VERSION 5.8 ;
BUSBITCHARS "[]" ;
DIVIDERCHAR "/" ;
UNITS
    DATABASE MICRONS 1000 ;
END UNITS

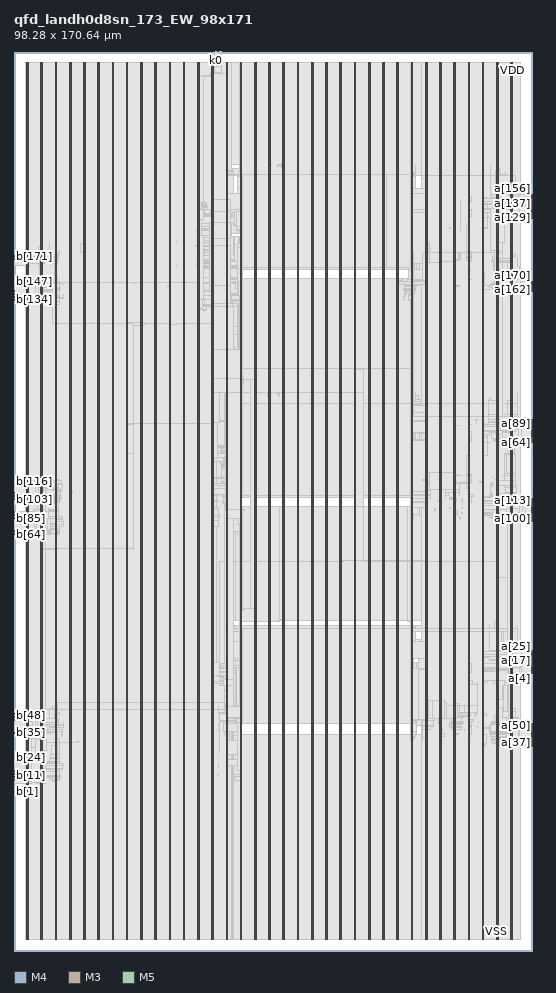
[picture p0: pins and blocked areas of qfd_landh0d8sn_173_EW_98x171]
MACRO qfd_landh0d8sn_173_EW_98x171
  FOREIGN qfd_landh0d8sn_173_EW_98x171 0 0 ;
  CLASS BLOCK ;
  SIZE 98.28 BY 170.64 ;
  PIN a[0]
    DIRECTION INPUT ;
    USE SIGNAL ;
    PORT
      LAYER M4 ;
        RECT  98.196 52.56 98.28 52.584 ;
    END
  END a[0]
  PIN a[100]
    DIRECTION INPUT ;
    USE SIGNAL ;
    PORT
      LAYER M4 ;
        RECT  98.196 81.936 98.28 81.96 ;
    END
  END a[100]
  PIN a[101]
    DIRECTION INPUT ;
    USE SIGNAL ;
    PORT
      LAYER M4 ;
        RECT  98.196 82.08 98.28 82.104 ;
    END
  END a[101]
  PIN a[102]
    DIRECTION INPUT ;
    USE SIGNAL ;
    PORT
      LAYER M4 ;
        RECT  98.196 82.224 98.28 82.248 ;
    END
  END a[102]
  PIN a[103]
    DIRECTION INPUT ;
    USE SIGNAL ;
    PORT
      LAYER M4 ;
        RECT  98.196 82.368 98.28 82.392 ;
    END
  END a[103]
  PIN a[104]
    DIRECTION INPUT ;
    USE SIGNAL ;
    PORT
      LAYER M4 ;
        RECT  98.196 82.512 98.28 82.536 ;
    END
  END a[104]
  PIN a[105]
    DIRECTION INPUT ;
    USE SIGNAL ;
    PORT
      LAYER M4 ;
        RECT  98.196 82.656 98.28 82.68 ;
    END
  END a[105]
  PIN a[106]
    DIRECTION INPUT ;
    USE SIGNAL ;
    PORT
      LAYER M4 ;
        RECT  98.196 82.8 98.28 82.824 ;
    END
  END a[106]
  PIN a[107]
    DIRECTION INPUT ;
    USE SIGNAL ;
    PORT
      LAYER M4 ;
        RECT  98.196 82.944 98.28 82.968 ;
    END
  END a[107]
  PIN a[108]
    DIRECTION INPUT ;
    USE SIGNAL ;
    PORT
      LAYER M4 ;
        RECT  98.196 83.088 98.28 83.112 ;
    END
  END a[108]
  PIN a[109]
    DIRECTION INPUT ;
    USE SIGNAL ;
    PORT
      LAYER M4 ;
        RECT  98.196 83.232 98.28 83.256 ;
    END
  END a[109]
  PIN a[10]
    DIRECTION INPUT ;
    USE SIGNAL ;
    PORT
      LAYER M4 ;
        RECT  98.196 54 98.28 54.024 ;
    END
  END a[10]
  PIN a[110]
    DIRECTION INPUT ;
    USE SIGNAL ;
    PORT
      LAYER M4 ;
        RECT  98.196 83.376 98.28 83.4 ;
    END
  END a[110]
  PIN a[111]
    DIRECTION INPUT ;
    USE SIGNAL ;
    PORT
      LAYER M4 ;
        RECT  98.196 83.52 98.28 83.544 ;
    END
  END a[111]
  PIN a[112]
    DIRECTION INPUT ;
    USE SIGNAL ;
    PORT
      LAYER M4 ;
        RECT  98.196 83.664 98.28 83.688 ;
    END
  END a[112]
  PIN a[113]
    DIRECTION INPUT ;
    USE SIGNAL ;
    PORT
      LAYER M4 ;
        RECT  98.196 83.808 98.28 83.832 ;
    END
  END a[113]
  PIN a[114]
    DIRECTION INPUT ;
    USE SIGNAL ;
    PORT
      LAYER M4 ;
        RECT  98.196 83.952 98.28 83.976 ;
    END
  END a[114]
  PIN a[115]
    DIRECTION INPUT ;
    USE SIGNAL ;
    PORT
      LAYER M4 ;
        RECT  98.196 84.096 98.28 84.12 ;
    END
  END a[115]
  PIN a[116]
    DIRECTION INPUT ;
    USE SIGNAL ;
    PORT
      LAYER M4 ;
        RECT  98.196 84.24 98.28 84.264 ;
    END
  END a[116]
  PIN a[117]
    DIRECTION INPUT ;
    USE SIGNAL ;
    PORT
      LAYER M4 ;
        RECT  98.196 84.384 98.28 84.408 ;
    END
  END a[117]
  PIN a[118]
    DIRECTION INPUT ;
    USE SIGNAL ;
    PORT
      LAYER M4 ;
        RECT  98.196 84.528 98.28 84.552 ;
    END
  END a[118]
  PIN a[119]
    DIRECTION INPUT ;
    USE SIGNAL ;
    PORT
      LAYER M4 ;
        RECT  98.196 84.672 98.28 84.696 ;
    END
  END a[119]
  PIN a[11]
    DIRECTION INPUT ;
    USE SIGNAL ;
    PORT
      LAYER M4 ;
        RECT  98.196 54.144 98.28 54.168 ;
    END
  END a[11]
  PIN a[120]
    DIRECTION INPUT ;
    USE SIGNAL ;
    PORT
      LAYER M4 ;
        RECT  98.196 84.816 98.28 84.84 ;
    END
  END a[120]
  PIN a[121]
    DIRECTION INPUT ;
    USE SIGNAL ;
    PORT
      LAYER M4 ;
        RECT  98.196 84.96 98.28 84.984 ;
    END
  END a[121]
  PIN a[122]
    DIRECTION INPUT ;
    USE SIGNAL ;
    PORT
      LAYER M4 ;
        RECT  98.196 85.104 98.28 85.128 ;
    END
  END a[122]
  PIN a[123]
    DIRECTION INPUT ;
    USE SIGNAL ;
    PORT
      LAYER M4 ;
        RECT  98.196 85.248 98.28 85.272 ;
    END
  END a[123]
  PIN a[124]
    DIRECTION INPUT ;
    USE SIGNAL ;
    PORT
      LAYER M4 ;
        RECT  98.196 85.392 98.28 85.416 ;
    END
  END a[124]
  PIN a[125]
    DIRECTION INPUT ;
    USE SIGNAL ;
    PORT
      LAYER M4 ;
        RECT  98.196 85.536 98.28 85.56 ;
    END
  END a[125]
  PIN a[126]
    DIRECTION INPUT ;
    USE SIGNAL ;
    PORT
      LAYER M4 ;
        RECT  98.196 85.68 98.28 85.704 ;
    END
  END a[126]
  PIN a[127]
    DIRECTION INPUT ;
    USE SIGNAL ;
    PORT
      LAYER M4 ;
        RECT  98.196 85.824 98.28 85.848 ;
    END
  END a[127]
  PIN a[128]
    DIRECTION INPUT ;
    USE SIGNAL ;
    PORT
      LAYER M4 ;
        RECT  98.196 138.96 98.28 138.984 ;
    END
  END a[128]
  PIN a[129]
    DIRECTION INPUT ;
    USE SIGNAL ;
    PORT
      LAYER M4 ;
        RECT  98.196 139.104 98.28 139.128 ;
    END
  END a[129]
  PIN a[12]
    DIRECTION INPUT ;
    USE SIGNAL ;
    PORT
      LAYER M4 ;
        RECT  98.196 54.288 98.28 54.312 ;
    END
  END a[12]
  PIN a[130]
    DIRECTION INPUT ;
    USE SIGNAL ;
    PORT
      LAYER M4 ;
        RECT  98.196 139.248 98.28 139.272 ;
    END
  END a[130]
  PIN a[131]
    DIRECTION INPUT ;
    USE SIGNAL ;
    PORT
      LAYER M4 ;
        RECT  98.196 139.392 98.28 139.416 ;
    END
  END a[131]
  PIN a[132]
    DIRECTION INPUT ;
    USE SIGNAL ;
    PORT
      LAYER M4 ;
        RECT  98.196 139.536 98.28 139.56 ;
    END
  END a[132]
  PIN a[133]
    DIRECTION INPUT ;
    USE SIGNAL ;
    PORT
      LAYER M4 ;
        RECT  98.196 139.68 98.28 139.704 ;
    END
  END a[133]
  PIN a[134]
    DIRECTION INPUT ;
    USE SIGNAL ;
    PORT
      LAYER M4 ;
        RECT  98.196 139.824 98.28 139.848 ;
    END
  END a[134]
  PIN a[135]
    DIRECTION INPUT ;
    USE SIGNAL ;
    PORT
      LAYER M4 ;
        RECT  98.196 139.968 98.28 139.992 ;
    END
  END a[135]
  PIN a[136]
    DIRECTION INPUT ;
    USE SIGNAL ;
    PORT
      LAYER M4 ;
        RECT  98.196 140.112 98.28 140.136 ;
    END
  END a[136]
  PIN a[137]
    DIRECTION INPUT ;
    USE SIGNAL ;
    PORT
      LAYER M4 ;
        RECT  98.196 140.256 98.28 140.28 ;
    END
  END a[137]
  PIN a[138]
    DIRECTION INPUT ;
    USE SIGNAL ;
    PORT
      LAYER M4 ;
        RECT  98.196 140.4 98.28 140.424 ;
    END
  END a[138]
  PIN a[139]
    DIRECTION INPUT ;
    USE SIGNAL ;
    PORT
      LAYER M4 ;
        RECT  98.196 140.544 98.28 140.568 ;
    END
  END a[139]
  PIN a[13]
    DIRECTION INPUT ;
    USE SIGNAL ;
    PORT
      LAYER M4 ;
        RECT  98.196 54.432 98.28 54.456 ;
    END
  END a[13]
  PIN a[140]
    DIRECTION INPUT ;
    USE SIGNAL ;
    PORT
      LAYER M4 ;
        RECT  98.196 140.688 98.28 140.712 ;
    END
  END a[140]
  PIN a[141]
    DIRECTION INPUT ;
    USE SIGNAL ;
    PORT
      LAYER M4 ;
        RECT  98.196 140.832 98.28 140.856 ;
    END
  END a[141]
  PIN a[142]
    DIRECTION INPUT ;
    USE SIGNAL ;
    PORT
      LAYER M4 ;
        RECT  98.196 140.976 98.28 141 ;
    END
  END a[142]
  PIN a[143]
    DIRECTION INPUT ;
    USE SIGNAL ;
    PORT
      LAYER M4 ;
        RECT  98.196 141.12 98.28 141.144 ;
    END
  END a[143]
  PIN a[144]
    DIRECTION INPUT ;
    USE SIGNAL ;
    PORT
      LAYER M4 ;
        RECT  98.196 141.264 98.28 141.288 ;
    END
  END a[144]
  PIN a[145]
    DIRECTION INPUT ;
    USE SIGNAL ;
    PORT
      LAYER M4 ;
        RECT  98.196 141.408 98.28 141.432 ;
    END
  END a[145]
  PIN a[146]
    DIRECTION INPUT ;
    USE SIGNAL ;
    PORT
      LAYER M4 ;
        RECT  98.196 141.552 98.28 141.576 ;
    END
  END a[146]
  PIN a[147]
    DIRECTION INPUT ;
    USE SIGNAL ;
    PORT
      LAYER M4 ;
        RECT  98.196 141.696 98.28 141.72 ;
    END
  END a[147]
  PIN a[148]
    DIRECTION INPUT ;
    USE SIGNAL ;
    PORT
      LAYER M4 ;
        RECT  98.196 141.84 98.28 141.864 ;
    END
  END a[148]
  PIN a[149]
    DIRECTION INPUT ;
    USE SIGNAL ;
    PORT
      LAYER M4 ;
        RECT  98.196 141.984 98.28 142.008 ;
    END
  END a[149]
  PIN a[14]
    DIRECTION INPUT ;
    USE SIGNAL ;
    PORT
      LAYER M4 ;
        RECT  98.196 54.576 98.28 54.6 ;
    END
  END a[14]
  PIN a[150]
    DIRECTION INPUT ;
    USE SIGNAL ;
    PORT
      LAYER M4 ;
        RECT  98.196 142.128 98.28 142.152 ;
    END
  END a[150]
  PIN a[151]
    DIRECTION INPUT ;
    USE SIGNAL ;
    PORT
      LAYER M4 ;
        RECT  98.196 142.272 98.28 142.296 ;
    END
  END a[151]
  PIN a[152]
    DIRECTION INPUT ;
    USE SIGNAL ;
    PORT
      LAYER M4 ;
        RECT  98.196 142.416 98.28 142.44 ;
    END
  END a[152]
  PIN a[153]
    DIRECTION INPUT ;
    USE SIGNAL ;
    PORT
      LAYER M4 ;
        RECT  98.196 142.56 98.28 142.584 ;
    END
  END a[153]
  PIN a[154]
    DIRECTION INPUT ;
    USE SIGNAL ;
    PORT
      LAYER M4 ;
        RECT  98.196 142.704 98.28 142.728 ;
    END
  END a[154]
  PIN a[155]
    DIRECTION INPUT ;
    USE SIGNAL ;
    PORT
      LAYER M4 ;
        RECT  98.196 142.848 98.28 142.872 ;
    END
  END a[155]
  PIN a[156]
    DIRECTION INPUT ;
    USE SIGNAL ;
    PORT
      LAYER M4 ;
        RECT  98.196 142.992 98.28 143.016 ;
    END
  END a[156]
  PIN a[157]
    DIRECTION INPUT ;
    USE SIGNAL ;
    PORT
      LAYER M4 ;
        RECT  98.196 143.136 98.28 143.16 ;
    END
  END a[157]
  PIN a[158]
    DIRECTION INPUT ;
    USE SIGNAL ;
    PORT
      LAYER M4 ;
        RECT  98.196 143.28 98.28 143.304 ;
    END
  END a[158]
  PIN a[159]
    DIRECTION INPUT ;
    USE SIGNAL ;
    PORT
      LAYER M4 ;
        RECT  98.196 143.424 98.28 143.448 ;
    END
  END a[159]
  PIN a[15]
    DIRECTION INPUT ;
    USE SIGNAL ;
    PORT
      LAYER M4 ;
        RECT  98.196 54.72 98.28 54.744 ;
    END
  END a[15]
  PIN a[160]
    DIRECTION INPUT ;
    USE SIGNAL ;
    PORT
      LAYER M4 ;
        RECT  98.196 125.136 98.28 125.16 ;
    END
  END a[160]
  PIN a[161]
    DIRECTION INPUT ;
    USE SIGNAL ;
    PORT
      LAYER M4 ;
        RECT  98.196 125.28 98.28 125.304 ;
    END
  END a[161]
  PIN a[162]
    DIRECTION INPUT ;
    USE SIGNAL ;
    PORT
      LAYER M4 ;
        RECT  98.196 125.424 98.28 125.448 ;
    END
  END a[162]
  PIN a[163]
    DIRECTION INPUT ;
    USE SIGNAL ;
    PORT
      LAYER M4 ;
        RECT  98.196 125.568 98.28 125.592 ;
    END
  END a[163]
  PIN a[164]
    DIRECTION INPUT ;
    USE SIGNAL ;
    PORT
      LAYER M4 ;
        RECT  98.196 125.712 98.28 125.736 ;
    END
  END a[164]
  PIN a[165]
    DIRECTION INPUT ;
    USE SIGNAL ;
    PORT
      LAYER M4 ;
        RECT  98.196 125.856 98.28 125.88 ;
    END
  END a[165]
  PIN a[166]
    DIRECTION INPUT ;
    USE SIGNAL ;
    PORT
      LAYER M4 ;
        RECT  98.196 126 98.28 126.024 ;
    END
  END a[166]
  PIN a[167]
    DIRECTION INPUT ;
    USE SIGNAL ;
    PORT
      LAYER M4 ;
        RECT  98.196 126.144 98.28 126.168 ;
    END
  END a[167]
  PIN a[168]
    DIRECTION INPUT ;
    USE SIGNAL ;
    PORT
      LAYER M4 ;
        RECT  98.196 126.288 98.28 126.312 ;
    END
  END a[168]
  PIN a[169]
    DIRECTION INPUT ;
    USE SIGNAL ;
    PORT
      LAYER M4 ;
        RECT  98.196 126.432 98.28 126.456 ;
    END
  END a[169]
  PIN a[16]
    DIRECTION INPUT ;
    USE SIGNAL ;
    PORT
      LAYER M4 ;
        RECT  98.196 54.864 98.28 54.888 ;
    END
  END a[16]
  PIN a[170]
    DIRECTION INPUT ;
    USE SIGNAL ;
    PORT
      LAYER M4 ;
        RECT  98.196 126.576 98.28 126.6 ;
    END
  END a[170]
  PIN a[171]
    DIRECTION INPUT ;
    USE SIGNAL ;
    PORT
      LAYER M4 ;
        RECT  98.196 126.72 98.28 126.744 ;
    END
  END a[171]
  PIN a[172]
    DIRECTION INPUT ;
    USE SIGNAL ;
    PORT
      LAYER M4 ;
        RECT  98.196 126.864 98.28 126.888 ;
    END
  END a[172]
  PIN a[17]
    DIRECTION INPUT ;
    USE SIGNAL ;
    PORT
      LAYER M4 ;
        RECT  98.196 55.008 98.28 55.032 ;
    END
  END a[17]
  PIN a[18]
    DIRECTION INPUT ;
    USE SIGNAL ;
    PORT
      LAYER M4 ;
        RECT  98.196 55.152 98.28 55.176 ;
    END
  END a[18]
  PIN a[19]
    DIRECTION INPUT ;
    USE SIGNAL ;
    PORT
      LAYER M4 ;
        RECT  98.196 55.296 98.28 55.32 ;
    END
  END a[19]
  PIN a[1]
    DIRECTION INPUT ;
    USE SIGNAL ;
    PORT
      LAYER M4 ;
        RECT  98.196 52.704 98.28 52.728 ;
    END
  END a[1]
  PIN a[20]
    DIRECTION INPUT ;
    USE SIGNAL ;
    PORT
      LAYER M4 ;
        RECT  98.196 55.44 98.28 55.464 ;
    END
  END a[20]
  PIN a[21]
    DIRECTION INPUT ;
    USE SIGNAL ;
    PORT
      LAYER M4 ;
        RECT  98.196 55.584 98.28 55.608 ;
    END
  END a[21]
  PIN a[22]
    DIRECTION INPUT ;
    USE SIGNAL ;
    PORT
      LAYER M4 ;
        RECT  98.196 55.728 98.28 55.752 ;
    END
  END a[22]
  PIN a[23]
    DIRECTION INPUT ;
    USE SIGNAL ;
    PORT
      LAYER M4 ;
        RECT  98.196 55.872 98.28 55.896 ;
    END
  END a[23]
  PIN a[24]
    DIRECTION INPUT ;
    USE SIGNAL ;
    PORT
      LAYER M4 ;
        RECT  98.196 56.016 98.28 56.04 ;
    END
  END a[24]
  PIN a[25]
    DIRECTION INPUT ;
    USE SIGNAL ;
    PORT
      LAYER M4 ;
        RECT  98.196 56.16 98.28 56.184 ;
    END
  END a[25]
  PIN a[26]
    DIRECTION INPUT ;
    USE SIGNAL ;
    PORT
      LAYER M4 ;
        RECT  98.196 56.304 98.28 56.328 ;
    END
  END a[26]
  PIN a[27]
    DIRECTION INPUT ;
    USE SIGNAL ;
    PORT
      LAYER M4 ;
        RECT  98.196 56.448 98.28 56.472 ;
    END
  END a[27]
  PIN a[28]
    DIRECTION INPUT ;
    USE SIGNAL ;
    PORT
      LAYER M4 ;
        RECT  98.196 56.592 98.28 56.616 ;
    END
  END a[28]
  PIN a[29]
    DIRECTION INPUT ;
    USE SIGNAL ;
    PORT
      LAYER M4 ;
        RECT  98.196 56.736 98.28 56.76 ;
    END
  END a[29]
  PIN a[2]
    DIRECTION INPUT ;
    USE SIGNAL ;
    PORT
      LAYER M4 ;
        RECT  98.196 52.848 98.28 52.872 ;
    END
  END a[2]
  PIN a[30]
    DIRECTION INPUT ;
    USE SIGNAL ;
    PORT
      LAYER M4 ;
        RECT  98.196 56.88 98.28 56.904 ;
    END
  END a[30]
  PIN a[31]
    DIRECTION INPUT ;
    USE SIGNAL ;
    PORT
      LAYER M4 ;
        RECT  98.196 57.024 98.28 57.048 ;
    END
  END a[31]
  PIN a[32]
    DIRECTION INPUT ;
    USE SIGNAL ;
    PORT
      LAYER M4 ;
        RECT  98.196 38.736 98.28 38.76 ;
    END
  END a[32]
  PIN a[33]
    DIRECTION INPUT ;
    USE SIGNAL ;
    PORT
      LAYER M4 ;
        RECT  98.196 38.88 98.28 38.904 ;
    END
  END a[33]
  PIN a[34]
    DIRECTION INPUT ;
    USE SIGNAL ;
    PORT
      LAYER M4 ;
        RECT  98.196 39.024 98.28 39.048 ;
    END
  END a[34]
  PIN a[35]
    DIRECTION INPUT ;
    USE SIGNAL ;
    PORT
      LAYER M4 ;
        RECT  98.196 39.168 98.28 39.192 ;
    END
  END a[35]
  PIN a[36]
    DIRECTION INPUT ;
    USE SIGNAL ;
    PORT
      LAYER M4 ;
        RECT  98.196 39.312 98.28 39.336 ;
    END
  END a[36]
  PIN a[37]
    DIRECTION INPUT ;
    USE SIGNAL ;
    PORT
      LAYER M4 ;
        RECT  98.196 39.456 98.28 39.48 ;
    END
  END a[37]
  PIN a[38]
    DIRECTION INPUT ;
    USE SIGNAL ;
    PORT
      LAYER M4 ;
        RECT  98.196 39.6 98.28 39.624 ;
    END
  END a[38]
  PIN a[39]
    DIRECTION INPUT ;
    USE SIGNAL ;
    PORT
      LAYER M4 ;
        RECT  98.196 39.744 98.28 39.768 ;
    END
  END a[39]
  PIN a[3]
    DIRECTION INPUT ;
    USE SIGNAL ;
    PORT
      LAYER M4 ;
        RECT  98.196 52.992 98.28 53.016 ;
    END
  END a[3]
  PIN a[40]
    DIRECTION INPUT ;
    USE SIGNAL ;
    PORT
      LAYER M4 ;
        RECT  98.196 39.888 98.28 39.912 ;
    END
  END a[40]
  PIN a[41]
    DIRECTION INPUT ;
    USE SIGNAL ;
    PORT
      LAYER M4 ;
        RECT  98.196 40.032 98.28 40.056 ;
    END
  END a[41]
  PIN a[42]
    DIRECTION INPUT ;
    USE SIGNAL ;
    PORT
      LAYER M4 ;
        RECT  98.196 40.176 98.28 40.2 ;
    END
  END a[42]
  PIN a[43]
    DIRECTION INPUT ;
    USE SIGNAL ;
    PORT
      LAYER M4 ;
        RECT  98.196 40.32 98.28 40.344 ;
    END
  END a[43]
  PIN a[44]
    DIRECTION INPUT ;
    USE SIGNAL ;
    PORT
      LAYER M4 ;
        RECT  98.196 40.464 98.28 40.488 ;
    END
  END a[44]
  PIN a[45]
    DIRECTION INPUT ;
    USE SIGNAL ;
    PORT
      LAYER M4 ;
        RECT  98.196 40.608 98.28 40.632 ;
    END
  END a[45]
  PIN a[46]
    DIRECTION INPUT ;
    USE SIGNAL ;
    PORT
      LAYER M4 ;
        RECT  98.196 40.752 98.28 40.776 ;
    END
  END a[46]
  PIN a[47]
    DIRECTION INPUT ;
    USE SIGNAL ;
    PORT
      LAYER M4 ;
        RECT  98.196 40.896 98.28 40.92 ;
    END
  END a[47]
  PIN a[48]
    DIRECTION INPUT ;
    USE SIGNAL ;
    PORT
      LAYER M4 ;
        RECT  98.196 41.04 98.28 41.064 ;
    END
  END a[48]
  PIN a[49]
    DIRECTION INPUT ;
    USE SIGNAL ;
    PORT
      LAYER M4 ;
        RECT  98.196 41.184 98.28 41.208 ;
    END
  END a[49]
  PIN a[4]
    DIRECTION INPUT ;
    USE SIGNAL ;
    PORT
      LAYER M4 ;
        RECT  98.196 53.136 98.28 53.16 ;
    END
  END a[4]
  PIN a[50]
    DIRECTION INPUT ;
    USE SIGNAL ;
    PORT
      LAYER M4 ;
        RECT  98.196 41.328 98.28 41.352 ;
    END
  END a[50]
  PIN a[51]
    DIRECTION INPUT ;
    USE SIGNAL ;
    PORT
      LAYER M4 ;
        RECT  98.196 41.472 98.28 41.496 ;
    END
  END a[51]
  PIN a[52]
    DIRECTION INPUT ;
    USE SIGNAL ;
    PORT
      LAYER M4 ;
        RECT  98.196 41.616 98.28 41.64 ;
    END
  END a[52]
  PIN a[53]
    DIRECTION INPUT ;
    USE SIGNAL ;
    PORT
      LAYER M4 ;
        RECT  98.196 41.76 98.28 41.784 ;
    END
  END a[53]
  PIN a[54]
    DIRECTION INPUT ;
    USE SIGNAL ;
    PORT
      LAYER M4 ;
        RECT  98.196 41.904 98.28 41.928 ;
    END
  END a[54]
  PIN a[55]
    DIRECTION INPUT ;
    USE SIGNAL ;
    PORT
      LAYER M4 ;
        RECT  98.196 42.048 98.28 42.072 ;
    END
  END a[55]
  PIN a[56]
    DIRECTION INPUT ;
    USE SIGNAL ;
    PORT
      LAYER M4 ;
        RECT  98.196 42.192 98.28 42.216 ;
    END
  END a[56]
  PIN a[57]
    DIRECTION INPUT ;
    USE SIGNAL ;
    PORT
      LAYER M4 ;
        RECT  98.196 42.336 98.28 42.36 ;
    END
  END a[57]
  PIN a[58]
    DIRECTION INPUT ;
    USE SIGNAL ;
    PORT
      LAYER M4 ;
        RECT  98.196 42.48 98.28 42.504 ;
    END
  END a[58]
  PIN a[59]
    DIRECTION INPUT ;
    USE SIGNAL ;
    PORT
      LAYER M4 ;
        RECT  98.196 42.624 98.28 42.648 ;
    END
  END a[59]
  PIN a[5]
    DIRECTION INPUT ;
    USE SIGNAL ;
    PORT
      LAYER M4 ;
        RECT  98.196 53.28 98.28 53.304 ;
    END
  END a[5]
  PIN a[60]
    DIRECTION INPUT ;
    USE SIGNAL ;
    PORT
      LAYER M4 ;
        RECT  98.196 42.768 98.28 42.792 ;
    END
  END a[60]
  PIN a[61]
    DIRECTION INPUT ;
    USE SIGNAL ;
    PORT
      LAYER M4 ;
        RECT  98.196 42.912 98.28 42.936 ;
    END
  END a[61]
  PIN a[62]
    DIRECTION INPUT ;
    USE SIGNAL ;
    PORT
      LAYER M4 ;
        RECT  98.196 43.056 98.28 43.08 ;
    END
  END a[62]
  PIN a[63]
    DIRECTION INPUT ;
    USE SIGNAL ;
    PORT
      LAYER M4 ;
        RECT  98.196 43.2 98.28 43.224 ;
    END
  END a[63]
  PIN a[64]
    DIRECTION INPUT ;
    USE SIGNAL ;
    PORT
      LAYER M4 ;
        RECT  98.196 96.336 98.28 96.36 ;
    END
  END a[64]
  PIN a[65]
    DIRECTION INPUT ;
    USE SIGNAL ;
    PORT
      LAYER M4 ;
        RECT  98.196 96.48 98.28 96.504 ;
    END
  END a[65]
  PIN a[66]
    DIRECTION INPUT ;
    USE SIGNAL ;
    PORT
      LAYER M4 ;
        RECT  98.196 96.624 98.28 96.648 ;
    END
  END a[66]
  PIN a[67]
    DIRECTION INPUT ;
    USE SIGNAL ;
    PORT
      LAYER M4 ;
        RECT  98.196 96.768 98.28 96.792 ;
    END
  END a[67]
  PIN a[68]
    DIRECTION INPUT ;
    USE SIGNAL ;
    PORT
      LAYER M4 ;
        RECT  98.196 96.912 98.28 96.936 ;
    END
  END a[68]
  PIN a[69]
    DIRECTION INPUT ;
    USE SIGNAL ;
    PORT
      LAYER M4 ;
        RECT  98.196 97.056 98.28 97.08 ;
    END
  END a[69]
  PIN a[6]
    DIRECTION INPUT ;
    USE SIGNAL ;
    PORT
      LAYER M4 ;
        RECT  98.196 53.424 98.28 53.448 ;
    END
  END a[6]
  PIN a[70]
    DIRECTION INPUT ;
    USE SIGNAL ;
    PORT
      LAYER M4 ;
        RECT  98.196 97.2 98.28 97.224 ;
    END
  END a[70]
  PIN a[71]
    DIRECTION INPUT ;
    USE SIGNAL ;
    PORT
      LAYER M4 ;
        RECT  98.196 97.344 98.28 97.368 ;
    END
  END a[71]
  PIN a[72]
    DIRECTION INPUT ;
    USE SIGNAL ;
    PORT
      LAYER M4 ;
        RECT  98.196 97.488 98.28 97.512 ;
    END
  END a[72]
  PIN a[73]
    DIRECTION INPUT ;
    USE SIGNAL ;
    PORT
      LAYER M4 ;
        RECT  98.196 97.632 98.28 97.656 ;
    END
  END a[73]
  PIN a[74]
    DIRECTION INPUT ;
    USE SIGNAL ;
    PORT
      LAYER M4 ;
        RECT  98.196 97.776 98.28 97.8 ;
    END
  END a[74]
  PIN a[75]
    DIRECTION INPUT ;
    USE SIGNAL ;
    PORT
      LAYER M4 ;
        RECT  98.196 97.92 98.28 97.944 ;
    END
  END a[75]
  PIN a[76]
    DIRECTION INPUT ;
    USE SIGNAL ;
    PORT
      LAYER M4 ;
        RECT  98.196 98.064 98.28 98.088 ;
    END
  END a[76]
  PIN a[77]
    DIRECTION INPUT ;
    USE SIGNAL ;
    PORT
      LAYER M4 ;
        RECT  98.196 98.208 98.28 98.232 ;
    END
  END a[77]
  PIN a[78]
    DIRECTION INPUT ;
    USE SIGNAL ;
    PORT
      LAYER M4 ;
        RECT  98.196 98.352 98.28 98.376 ;
    END
  END a[78]
  PIN a[79]
    DIRECTION INPUT ;
    USE SIGNAL ;
    PORT
      LAYER M4 ;
        RECT  98.196 98.496 98.28 98.52 ;
    END
  END a[79]
  PIN a[7]
    DIRECTION INPUT ;
    USE SIGNAL ;
    PORT
      LAYER M4 ;
        RECT  98.196 53.568 98.28 53.592 ;
    END
  END a[7]
  PIN a[80]
    DIRECTION INPUT ;
    USE SIGNAL ;
    PORT
      LAYER M4 ;
        RECT  98.196 98.64 98.28 98.664 ;
    END
  END a[80]
  PIN a[81]
    DIRECTION INPUT ;
    USE SIGNAL ;
    PORT
      LAYER M4 ;
        RECT  98.196 98.784 98.28 98.808 ;
    END
  END a[81]
  PIN a[82]
    DIRECTION INPUT ;
    USE SIGNAL ;
    PORT
      LAYER M4 ;
        RECT  98.196 98.928 98.28 98.952 ;
    END
  END a[82]
  PIN a[83]
    DIRECTION INPUT ;
    USE SIGNAL ;
    PORT
      LAYER M4 ;
        RECT  98.196 99.072 98.28 99.096 ;
    END
  END a[83]
  PIN a[84]
    DIRECTION INPUT ;
    USE SIGNAL ;
    PORT
      LAYER M4 ;
        RECT  98.196 99.216 98.28 99.24 ;
    END
  END a[84]
  PIN a[85]
    DIRECTION INPUT ;
    USE SIGNAL ;
    PORT
      LAYER M4 ;
        RECT  98.196 99.36 98.28 99.384 ;
    END
  END a[85]
  PIN a[86]
    DIRECTION INPUT ;
    USE SIGNAL ;
    PORT
      LAYER M4 ;
        RECT  98.196 99.504 98.28 99.528 ;
    END
  END a[86]
  PIN a[87]
    DIRECTION INPUT ;
    USE SIGNAL ;
    PORT
      LAYER M4 ;
        RECT  98.196 99.648 98.28 99.672 ;
    END
  END a[87]
  PIN a[88]
    DIRECTION INPUT ;
    USE SIGNAL ;
    PORT
      LAYER M4 ;
        RECT  98.196 99.792 98.28 99.816 ;
    END
  END a[88]
  PIN a[89]
    DIRECTION INPUT ;
    USE SIGNAL ;
    PORT
      LAYER M4 ;
        RECT  98.196 99.936 98.28 99.96 ;
    END
  END a[89]
  PIN a[8]
    DIRECTION INPUT ;
    USE SIGNAL ;
    PORT
      LAYER M4 ;
        RECT  98.196 53.712 98.28 53.736 ;
    END
  END a[8]
  PIN a[90]
    DIRECTION INPUT ;
    USE SIGNAL ;
    PORT
      LAYER M4 ;
        RECT  98.196 100.08 98.28 100.104 ;
    END
  END a[90]
  PIN a[91]
    DIRECTION INPUT ;
    USE SIGNAL ;
    PORT
      LAYER M4 ;
        RECT  98.196 100.224 98.28 100.248 ;
    END
  END a[91]
  PIN a[92]
    DIRECTION INPUT ;
    USE SIGNAL ;
    PORT
      LAYER M4 ;
        RECT  98.196 100.368 98.28 100.392 ;
    END
  END a[92]
  PIN a[93]
    DIRECTION INPUT ;
    USE SIGNAL ;
    PORT
      LAYER M4 ;
        RECT  98.196 100.512 98.28 100.536 ;
    END
  END a[93]
  PIN a[94]
    DIRECTION INPUT ;
    USE SIGNAL ;
    PORT
      LAYER M4 ;
        RECT  98.196 100.656 98.28 100.68 ;
    END
  END a[94]
  PIN a[95]
    DIRECTION INPUT ;
    USE SIGNAL ;
    PORT
      LAYER M4 ;
        RECT  98.196 100.8 98.28 100.824 ;
    END
  END a[95]
  PIN a[96]
    DIRECTION INPUT ;
    USE SIGNAL ;
    PORT
      LAYER M4 ;
        RECT  98.196 81.36 98.28 81.384 ;
    END
  END a[96]
  PIN a[97]
    DIRECTION INPUT ;
    USE SIGNAL ;
    PORT
      LAYER M4 ;
        RECT  98.196 81.504 98.28 81.528 ;
    END
  END a[97]
  PIN a[98]
    DIRECTION INPUT ;
    USE SIGNAL ;
    PORT
      LAYER M4 ;
        RECT  98.196 81.648 98.28 81.672 ;
    END
  END a[98]
  PIN a[99]
    DIRECTION INPUT ;
    USE SIGNAL ;
    PORT
      LAYER M4 ;
        RECT  98.196 81.792 98.28 81.816 ;
    END
  END a[99]
  PIN a[9]
    DIRECTION INPUT ;
    USE SIGNAL ;
    PORT
      LAYER M4 ;
        RECT  98.196 53.856 98.28 53.88 ;
    END
  END a[9]
  PIN b[0]
    DIRECTION OUTPUT ;
    USE SIGNAL ;
    PORT
      LAYER M4 ;
        RECT  0 31.68 0.084 31.704 ;
    END
  END b[0]
  PIN b[100]
    DIRECTION OUTPUT ;
    USE SIGNAL ;
    PORT
      LAYER M4 ;
        RECT  0 85.248 0.084 85.272 ;
    END
  END b[100]
  PIN b[101]
    DIRECTION OUTPUT ;
    USE SIGNAL ;
    PORT
      LAYER M4 ;
        RECT  0 85.392 0.084 85.416 ;
    END
  END b[101]
  PIN b[102]
    DIRECTION OUTPUT ;
    USE SIGNAL ;
    PORT
      LAYER M4 ;
        RECT  0 85.536 0.084 85.56 ;
    END
  END b[102]
  PIN b[103]
    DIRECTION OUTPUT ;
    USE SIGNAL ;
    PORT
      LAYER M4 ;
        RECT  0 85.68 0.084 85.704 ;
    END
  END b[103]
  PIN b[104]
    DIRECTION OUTPUT ;
    USE SIGNAL ;
    PORT
      LAYER M4 ;
        RECT  0 85.824 0.084 85.848 ;
    END
  END b[104]
  PIN b[105]
    DIRECTION OUTPUT ;
    USE SIGNAL ;
    PORT
      LAYER M4 ;
        RECT  0 85.968 0.084 85.992 ;
    END
  END b[105]
  PIN b[106]
    DIRECTION OUTPUT ;
    USE SIGNAL ;
    PORT
      LAYER M4 ;
        RECT  0 86.112 0.084 86.136 ;
    END
  END b[106]
  PIN b[107]
    DIRECTION OUTPUT ;
    USE SIGNAL ;
    PORT
      LAYER M4 ;
        RECT  0 86.256 0.084 86.28 ;
    END
  END b[107]
  PIN b[108]
    DIRECTION OUTPUT ;
    USE SIGNAL ;
    PORT
      LAYER M4 ;
        RECT  0 86.4 0.084 86.424 ;
    END
  END b[108]
  PIN b[109]
    DIRECTION OUTPUT ;
    USE SIGNAL ;
    PORT
      LAYER M4 ;
        RECT  0 86.544 0.084 86.568 ;
    END
  END b[109]
  PIN b[10]
    DIRECTION OUTPUT ;
    USE SIGNAL ;
    PORT
      LAYER M4 ;
        RECT  0 33.12 0.084 33.144 ;
    END
  END b[10]
  PIN b[110]
    DIRECTION OUTPUT ;
    USE SIGNAL ;
    PORT
      LAYER M4 ;
        RECT  0 86.688 0.084 86.712 ;
    END
  END b[110]
  PIN b[111]
    DIRECTION OUTPUT ;
    USE SIGNAL ;
    PORT
      LAYER M4 ;
        RECT  0 86.832 0.084 86.856 ;
    END
  END b[111]
  PIN b[112]
    DIRECTION OUTPUT ;
    USE SIGNAL ;
    PORT
      LAYER M4 ;
        RECT  0 86.976 0.084 87 ;
    END
  END b[112]
  PIN b[113]
    DIRECTION OUTPUT ;
    USE SIGNAL ;
    PORT
      LAYER M4 ;
        RECT  0 87.12 0.084 87.144 ;
    END
  END b[113]
  PIN b[114]
    DIRECTION OUTPUT ;
    USE SIGNAL ;
    PORT
      LAYER M4 ;
        RECT  0 87.264 0.084 87.288 ;
    END
  END b[114]
  PIN b[115]
    DIRECTION OUTPUT ;
    USE SIGNAL ;
    PORT
      LAYER M4 ;
        RECT  0 87.408 0.084 87.432 ;
    END
  END b[115]
  PIN b[116]
    DIRECTION OUTPUT ;
    USE SIGNAL ;
    PORT
      LAYER M4 ;
        RECT  0 87.552 0.084 87.576 ;
    END
  END b[116]
  PIN b[117]
    DIRECTION OUTPUT ;
    USE SIGNAL ;
    PORT
      LAYER M4 ;
        RECT  0 87.696 0.084 87.72 ;
    END
  END b[117]
  PIN b[118]
    DIRECTION OUTPUT ;
    USE SIGNAL ;
    PORT
      LAYER M4 ;
        RECT  0 87.84 0.084 87.864 ;
    END
  END b[118]
  PIN b[119]
    DIRECTION OUTPUT ;
    USE SIGNAL ;
    PORT
      LAYER M4 ;
        RECT  0 87.984 0.084 88.008 ;
    END
  END b[119]
  PIN b[11]
    DIRECTION OUTPUT ;
    USE SIGNAL ;
    PORT
      LAYER M4 ;
        RECT  0 33.264 0.084 33.288 ;
    END
  END b[11]
  PIN b[120]
    DIRECTION OUTPUT ;
    USE SIGNAL ;
    PORT
      LAYER M4 ;
        RECT  0 88.128 0.084 88.152 ;
    END
  END b[120]
  PIN b[121]
    DIRECTION OUTPUT ;
    USE SIGNAL ;
    PORT
      LAYER M4 ;
        RECT  0 88.272 0.084 88.296 ;
    END
  END b[121]
  PIN b[122]
    DIRECTION OUTPUT ;
    USE SIGNAL ;
    PORT
      LAYER M4 ;
        RECT  0 88.416 0.084 88.44 ;
    END
  END b[122]
  PIN b[123]
    DIRECTION OUTPUT ;
    USE SIGNAL ;
    PORT
      LAYER M4 ;
        RECT  0 88.56 0.084 88.584 ;
    END
  END b[123]
  PIN b[124]
    DIRECTION OUTPUT ;
    USE SIGNAL ;
    PORT
      LAYER M4 ;
        RECT  0 88.704 0.084 88.728 ;
    END
  END b[124]
  PIN b[125]
    DIRECTION OUTPUT ;
    USE SIGNAL ;
    PORT
      LAYER M4 ;
        RECT  0 88.848 0.084 88.872 ;
    END
  END b[125]
  PIN b[126]
    DIRECTION OUTPUT ;
    USE SIGNAL ;
    PORT
      LAYER M4 ;
        RECT  0 88.992 0.084 89.016 ;
    END
  END b[126]
  PIN b[127]
    DIRECTION OUTPUT ;
    USE SIGNAL ;
    PORT
      LAYER M4 ;
        RECT  0 89.136 0.084 89.16 ;
    END
  END b[127]
  PIN b[128]
    DIRECTION OUTPUT ;
    USE SIGNAL ;
    PORT
      LAYER M4 ;
        RECT  0 122.688 0.084 122.712 ;
    END
  END b[128]
  PIN b[129]
    DIRECTION OUTPUT ;
    USE SIGNAL ;
    PORT
      LAYER M4 ;
        RECT  0 122.832 0.084 122.856 ;
    END
  END b[129]
  PIN b[12]
    DIRECTION OUTPUT ;
    USE SIGNAL ;
    PORT
      LAYER M4 ;
        RECT  0 33.408 0.084 33.432 ;
    END
  END b[12]
  PIN b[130]
    DIRECTION OUTPUT ;
    USE SIGNAL ;
    PORT
      LAYER M4 ;
        RECT  0 122.976 0.084 123 ;
    END
  END b[130]
  PIN b[131]
    DIRECTION OUTPUT ;
    USE SIGNAL ;
    PORT
      LAYER M4 ;
        RECT  0 123.12 0.084 123.144 ;
    END
  END b[131]
  PIN b[132]
    DIRECTION OUTPUT ;
    USE SIGNAL ;
    PORT
      LAYER M4 ;
        RECT  0 123.264 0.084 123.288 ;
    END
  END b[132]
  PIN b[133]
    DIRECTION OUTPUT ;
    USE SIGNAL ;
    PORT
      LAYER M4 ;
        RECT  0 123.408 0.084 123.432 ;
    END
  END b[133]
  PIN b[134]
    DIRECTION OUTPUT ;
    USE SIGNAL ;
    PORT
      LAYER M4 ;
        RECT  0 123.552 0.084 123.576 ;
    END
  END b[134]
  PIN b[135]
    DIRECTION OUTPUT ;
    USE SIGNAL ;
    PORT
      LAYER M4 ;
        RECT  0 123.696 0.084 123.72 ;
    END
  END b[135]
  PIN b[136]
    DIRECTION OUTPUT ;
    USE SIGNAL ;
    PORT
      LAYER M4 ;
        RECT  0 123.84 0.084 123.864 ;
    END
  END b[136]
  PIN b[137]
    DIRECTION OUTPUT ;
    USE SIGNAL ;
    PORT
      LAYER M4 ;
        RECT  0 123.984 0.084 124.008 ;
    END
  END b[137]
  PIN b[138]
    DIRECTION OUTPUT ;
    USE SIGNAL ;
    PORT
      LAYER M4 ;
        RECT  0 124.128 0.084 124.152 ;
    END
  END b[138]
  PIN b[139]
    DIRECTION OUTPUT ;
    USE SIGNAL ;
    PORT
      LAYER M4 ;
        RECT  0 124.272 0.084 124.296 ;
    END
  END b[139]
  PIN b[13]
    DIRECTION OUTPUT ;
    USE SIGNAL ;
    PORT
      LAYER M4 ;
        RECT  0 33.552 0.084 33.576 ;
    END
  END b[13]
  PIN b[140]
    DIRECTION OUTPUT ;
    USE SIGNAL ;
    PORT
      LAYER M4 ;
        RECT  0 124.416 0.084 124.44 ;
    END
  END b[140]
  PIN b[141]
    DIRECTION OUTPUT ;
    USE SIGNAL ;
    PORT
      LAYER M4 ;
        RECT  0 124.56 0.084 124.584 ;
    END
  END b[141]
  PIN b[142]
    DIRECTION OUTPUT ;
    USE SIGNAL ;
    PORT
      LAYER M4 ;
        RECT  0 124.704 0.084 124.728 ;
    END
  END b[142]
  PIN b[143]
    DIRECTION OUTPUT ;
    USE SIGNAL ;
    PORT
      LAYER M4 ;
        RECT  0 124.848 0.084 124.872 ;
    END
  END b[143]
  PIN b[144]
    DIRECTION OUTPUT ;
    USE SIGNAL ;
    PORT
      LAYER M4 ;
        RECT  0 124.992 0.084 125.016 ;
    END
  END b[144]
  PIN b[145]
    DIRECTION OUTPUT ;
    USE SIGNAL ;
    PORT
      LAYER M4 ;
        RECT  0 125.136 0.084 125.16 ;
    END
  END b[145]
  PIN b[146]
    DIRECTION OUTPUT ;
    USE SIGNAL ;
    PORT
      LAYER M4 ;
        RECT  0 125.28 0.084 125.304 ;
    END
  END b[146]
  PIN b[147]
    DIRECTION OUTPUT ;
    USE SIGNAL ;
    PORT
      LAYER M4 ;
        RECT  0 125.424 0.084 125.448 ;
    END
  END b[147]
  PIN b[148]
    DIRECTION OUTPUT ;
    USE SIGNAL ;
    PORT
      LAYER M4 ;
        RECT  0 125.568 0.084 125.592 ;
    END
  END b[148]
  PIN b[149]
    DIRECTION OUTPUT ;
    USE SIGNAL ;
    PORT
      LAYER M4 ;
        RECT  0 125.712 0.084 125.736 ;
    END
  END b[149]
  PIN b[14]
    DIRECTION OUTPUT ;
    USE SIGNAL ;
    PORT
      LAYER M4 ;
        RECT  0 33.696 0.084 33.72 ;
    END
  END b[14]
  PIN b[150]
    DIRECTION OUTPUT ;
    USE SIGNAL ;
    PORT
      LAYER M4 ;
        RECT  0 125.856 0.084 125.88 ;
    END
  END b[150]
  PIN b[151]
    DIRECTION OUTPUT ;
    USE SIGNAL ;
    PORT
      LAYER M4 ;
        RECT  0 126 0.084 126.024 ;
    END
  END b[151]
  PIN b[152]
    DIRECTION OUTPUT ;
    USE SIGNAL ;
    PORT
      LAYER M4 ;
        RECT  0 126.144 0.084 126.168 ;
    END
  END b[152]
  PIN b[153]
    DIRECTION OUTPUT ;
    USE SIGNAL ;
    PORT
      LAYER M4 ;
        RECT  0 126.288 0.084 126.312 ;
    END
  END b[153]
  PIN b[154]
    DIRECTION OUTPUT ;
    USE SIGNAL ;
    PORT
      LAYER M4 ;
        RECT  0 126.432 0.084 126.456 ;
    END
  END b[154]
  PIN b[155]
    DIRECTION OUTPUT ;
    USE SIGNAL ;
    PORT
      LAYER M4 ;
        RECT  0 126.576 0.084 126.6 ;
    END
  END b[155]
  PIN b[156]
    DIRECTION OUTPUT ;
    USE SIGNAL ;
    PORT
      LAYER M4 ;
        RECT  0 126.72 0.084 126.744 ;
    END
  END b[156]
  PIN b[157]
    DIRECTION OUTPUT ;
    USE SIGNAL ;
    PORT
      LAYER M4 ;
        RECT  0 126.864 0.084 126.888 ;
    END
  END b[157]
  PIN b[158]
    DIRECTION OUTPUT ;
    USE SIGNAL ;
    PORT
      LAYER M4 ;
        RECT  0 127.008 0.084 127.032 ;
    END
  END b[158]
  PIN b[159]
    DIRECTION OUTPUT ;
    USE SIGNAL ;
    PORT
      LAYER M4 ;
        RECT  0 127.152 0.084 127.176 ;
    END
  END b[159]
  PIN b[15]
    DIRECTION OUTPUT ;
    USE SIGNAL ;
    PORT
      LAYER M4 ;
        RECT  0 33.84 0.084 33.864 ;
    END
  END b[15]
  PIN b[160]
    DIRECTION OUTPUT ;
    USE SIGNAL ;
    PORT
      LAYER M4 ;
        RECT  0 130.032 0.084 130.056 ;
    END
  END b[160]
  PIN b[161]
    DIRECTION OUTPUT ;
    USE SIGNAL ;
    PORT
      LAYER M4 ;
        RECT  0 130.176 0.084 130.2 ;
    END
  END b[161]
  PIN b[162]
    DIRECTION OUTPUT ;
    USE SIGNAL ;
    PORT
      LAYER M4 ;
        RECT  0 130.32 0.084 130.344 ;
    END
  END b[162]
  PIN b[163]
    DIRECTION OUTPUT ;
    USE SIGNAL ;
    PORT
      LAYER M4 ;
        RECT  0 130.464 0.084 130.488 ;
    END
  END b[163]
  PIN b[164]
    DIRECTION OUTPUT ;
    USE SIGNAL ;
    PORT
      LAYER M4 ;
        RECT  0 130.608 0.084 130.632 ;
    END
  END b[164]
  PIN b[165]
    DIRECTION OUTPUT ;
    USE SIGNAL ;
    PORT
      LAYER M4 ;
        RECT  0 130.752 0.084 130.776 ;
    END
  END b[165]
  PIN b[166]
    DIRECTION OUTPUT ;
    USE SIGNAL ;
    PORT
      LAYER M4 ;
        RECT  0 130.896 0.084 130.92 ;
    END
  END b[166]
  PIN b[167]
    DIRECTION OUTPUT ;
    USE SIGNAL ;
    PORT
      LAYER M4 ;
        RECT  0 131.04 0.084 131.064 ;
    END
  END b[167]
  PIN b[168]
    DIRECTION OUTPUT ;
    USE SIGNAL ;
    PORT
      LAYER M4 ;
        RECT  0 131.184 0.084 131.208 ;
    END
  END b[168]
  PIN b[169]
    DIRECTION OUTPUT ;
    USE SIGNAL ;
    PORT
      LAYER M4 ;
        RECT  0 131.328 0.084 131.352 ;
    END
  END b[169]
  PIN b[16]
    DIRECTION OUTPUT ;
    USE SIGNAL ;
    PORT
      LAYER M4 ;
        RECT  0 33.984 0.084 34.008 ;
    END
  END b[16]
  PIN b[170]
    DIRECTION OUTPUT ;
    USE SIGNAL ;
    PORT
      LAYER M4 ;
        RECT  0 131.472 0.084 131.496 ;
    END
  END b[170]
  PIN b[171]
    DIRECTION OUTPUT ;
    USE SIGNAL ;
    PORT
      LAYER M4 ;
        RECT  0 131.616 0.084 131.64 ;
    END
  END b[171]
  PIN b[172]
    DIRECTION OUTPUT ;
    USE SIGNAL ;
    PORT
      LAYER M4 ;
        RECT  0 131.76 0.084 131.784 ;
    END
  END b[172]
  PIN b[17]
    DIRECTION OUTPUT ;
    USE SIGNAL ;
    PORT
      LAYER M4 ;
        RECT  0 34.128 0.084 34.152 ;
    END
  END b[17]
  PIN b[18]
    DIRECTION OUTPUT ;
    USE SIGNAL ;
    PORT
      LAYER M4 ;
        RECT  0 34.272 0.084 34.296 ;
    END
  END b[18]
  PIN b[19]
    DIRECTION OUTPUT ;
    USE SIGNAL ;
    PORT
      LAYER M4 ;
        RECT  0 34.416 0.084 34.44 ;
    END
  END b[19]
  PIN b[1]
    DIRECTION OUTPUT ;
    USE SIGNAL ;
    PORT
      LAYER M4 ;
        RECT  0 31.824 0.084 31.848 ;
    END
  END b[1]
  PIN b[20]
    DIRECTION OUTPUT ;
    USE SIGNAL ;
    PORT
      LAYER M4 ;
        RECT  0 34.56 0.084 34.584 ;
    END
  END b[20]
  PIN b[21]
    DIRECTION OUTPUT ;
    USE SIGNAL ;
    PORT
      LAYER M4 ;
        RECT  0 34.704 0.084 34.728 ;
    END
  END b[21]
  PIN b[22]
    DIRECTION OUTPUT ;
    USE SIGNAL ;
    PORT
      LAYER M4 ;
        RECT  0 34.848 0.084 34.872 ;
    END
  END b[22]
  PIN b[23]
    DIRECTION OUTPUT ;
    USE SIGNAL ;
    PORT
      LAYER M4 ;
        RECT  0 34.992 0.084 35.016 ;
    END
  END b[23]
  PIN b[24]
    DIRECTION OUTPUT ;
    USE SIGNAL ;
    PORT
      LAYER M4 ;
        RECT  0 35.136 0.084 35.16 ;
    END
  END b[24]
  PIN b[25]
    DIRECTION OUTPUT ;
    USE SIGNAL ;
    PORT
      LAYER M4 ;
        RECT  0 35.28 0.084 35.304 ;
    END
  END b[25]
  PIN b[26]
    DIRECTION OUTPUT ;
    USE SIGNAL ;
    PORT
      LAYER M4 ;
        RECT  0 35.424 0.084 35.448 ;
    END
  END b[26]
  PIN b[27]
    DIRECTION OUTPUT ;
    USE SIGNAL ;
    PORT
      LAYER M4 ;
        RECT  0 35.568 0.084 35.592 ;
    END
  END b[27]
  PIN b[28]
    DIRECTION OUTPUT ;
    USE SIGNAL ;
    PORT
      LAYER M4 ;
        RECT  0 35.712 0.084 35.736 ;
    END
  END b[28]
  PIN b[29]
    DIRECTION OUTPUT ;
    USE SIGNAL ;
    PORT
      LAYER M4 ;
        RECT  0 35.856 0.084 35.88 ;
    END
  END b[29]
  PIN b[2]
    DIRECTION OUTPUT ;
    USE SIGNAL ;
    PORT
      LAYER M4 ;
        RECT  0 31.968 0.084 31.992 ;
    END
  END b[2]
  PIN b[30]
    DIRECTION OUTPUT ;
    USE SIGNAL ;
    PORT
      LAYER M4 ;
        RECT  0 36 0.084 36.024 ;
    END
  END b[30]
  PIN b[31]
    DIRECTION OUTPUT ;
    USE SIGNAL ;
    PORT
      LAYER M4 ;
        RECT  0 36.144 0.084 36.168 ;
    END
  END b[31]
  PIN b[32]
    DIRECTION OUTPUT ;
    USE SIGNAL ;
    PORT
      LAYER M4 ;
        RECT  0 40.896 0.084 40.92 ;
    END
  END b[32]
  PIN b[33]
    DIRECTION OUTPUT ;
    USE SIGNAL ;
    PORT
      LAYER M4 ;
        RECT  0 41.04 0.084 41.064 ;
    END
  END b[33]
  PIN b[34]
    DIRECTION OUTPUT ;
    USE SIGNAL ;
    PORT
      LAYER M4 ;
        RECT  0 41.184 0.084 41.208 ;
    END
  END b[34]
  PIN b[35]
    DIRECTION OUTPUT ;
    USE SIGNAL ;
    PORT
      LAYER M4 ;
        RECT  0 41.328 0.084 41.352 ;
    END
  END b[35]
  PIN b[36]
    DIRECTION OUTPUT ;
    USE SIGNAL ;
    PORT
      LAYER M4 ;
        RECT  0 41.472 0.084 41.496 ;
    END
  END b[36]
  PIN b[37]
    DIRECTION OUTPUT ;
    USE SIGNAL ;
    PORT
      LAYER M4 ;
        RECT  0 41.616 0.084 41.64 ;
    END
  END b[37]
  PIN b[38]
    DIRECTION OUTPUT ;
    USE SIGNAL ;
    PORT
      LAYER M4 ;
        RECT  0 41.76 0.084 41.784 ;
    END
  END b[38]
  PIN b[39]
    DIRECTION OUTPUT ;
    USE SIGNAL ;
    PORT
      LAYER M4 ;
        RECT  0 41.904 0.084 41.928 ;
    END
  END b[39]
  PIN b[3]
    DIRECTION OUTPUT ;
    USE SIGNAL ;
    PORT
      LAYER M4 ;
        RECT  0 32.112 0.084 32.136 ;
    END
  END b[3]
  PIN b[40]
    DIRECTION OUTPUT ;
    USE SIGNAL ;
    PORT
      LAYER M4 ;
        RECT  0 42.048 0.084 42.072 ;
    END
  END b[40]
  PIN b[41]
    DIRECTION OUTPUT ;
    USE SIGNAL ;
    PORT
      LAYER M4 ;
        RECT  0 42.192 0.084 42.216 ;
    END
  END b[41]
  PIN b[42]
    DIRECTION OUTPUT ;
    USE SIGNAL ;
    PORT
      LAYER M4 ;
        RECT  0 42.336 0.084 42.36 ;
    END
  END b[42]
  PIN b[43]
    DIRECTION OUTPUT ;
    USE SIGNAL ;
    PORT
      LAYER M4 ;
        RECT  0 42.48 0.084 42.504 ;
    END
  END b[43]
  PIN b[44]
    DIRECTION OUTPUT ;
    USE SIGNAL ;
    PORT
      LAYER M4 ;
        RECT  0 42.624 0.084 42.648 ;
    END
  END b[44]
  PIN b[45]
    DIRECTION OUTPUT ;
    USE SIGNAL ;
    PORT
      LAYER M4 ;
        RECT  0 42.768 0.084 42.792 ;
    END
  END b[45]
  PIN b[46]
    DIRECTION OUTPUT ;
    USE SIGNAL ;
    PORT
      LAYER M4 ;
        RECT  0 42.912 0.084 42.936 ;
    END
  END b[46]
  PIN b[47]
    DIRECTION OUTPUT ;
    USE SIGNAL ;
    PORT
      LAYER M4 ;
        RECT  0 43.056 0.084 43.08 ;
    END
  END b[47]
  PIN b[48]
    DIRECTION OUTPUT ;
    USE SIGNAL ;
    PORT
      LAYER M4 ;
        RECT  0 43.2 0.084 43.224 ;
    END
  END b[48]
  PIN b[49]
    DIRECTION OUTPUT ;
    USE SIGNAL ;
    PORT
      LAYER M4 ;
        RECT  0 43.344 0.084 43.368 ;
    END
  END b[49]
  PIN b[4]
    DIRECTION OUTPUT ;
    USE SIGNAL ;
    PORT
      LAYER M4 ;
        RECT  0 32.256 0.084 32.28 ;
    END
  END b[4]
  PIN b[50]
    DIRECTION OUTPUT ;
    USE SIGNAL ;
    PORT
      LAYER M4 ;
        RECT  0 43.488 0.084 43.512 ;
    END
  END b[50]
  PIN b[51]
    DIRECTION OUTPUT ;
    USE SIGNAL ;
    PORT
      LAYER M4 ;
        RECT  0 43.632 0.084 43.656 ;
    END
  END b[51]
  PIN b[52]
    DIRECTION OUTPUT ;
    USE SIGNAL ;
    PORT
      LAYER M4 ;
        RECT  0 43.776 0.084 43.8 ;
    END
  END b[52]
  PIN b[53]
    DIRECTION OUTPUT ;
    USE SIGNAL ;
    PORT
      LAYER M4 ;
        RECT  0 43.92 0.084 43.944 ;
    END
  END b[53]
  PIN b[54]
    DIRECTION OUTPUT ;
    USE SIGNAL ;
    PORT
      LAYER M4 ;
        RECT  0 44.064 0.084 44.088 ;
    END
  END b[54]
  PIN b[55]
    DIRECTION OUTPUT ;
    USE SIGNAL ;
    PORT
      LAYER M4 ;
        RECT  0 44.208 0.084 44.232 ;
    END
  END b[55]
  PIN b[56]
    DIRECTION OUTPUT ;
    USE SIGNAL ;
    PORT
      LAYER M4 ;
        RECT  0 44.352 0.084 44.376 ;
    END
  END b[56]
  PIN b[57]
    DIRECTION OUTPUT ;
    USE SIGNAL ;
    PORT
      LAYER M4 ;
        RECT  0 44.496 0.084 44.52 ;
    END
  END b[57]
  PIN b[58]
    DIRECTION OUTPUT ;
    USE SIGNAL ;
    PORT
      LAYER M4 ;
        RECT  0 44.64 0.084 44.664 ;
    END
  END b[58]
  PIN b[59]
    DIRECTION OUTPUT ;
    USE SIGNAL ;
    PORT
      LAYER M4 ;
        RECT  0 44.784 0.084 44.808 ;
    END
  END b[59]
  PIN b[5]
    DIRECTION OUTPUT ;
    USE SIGNAL ;
    PORT
      LAYER M4 ;
        RECT  0 32.4 0.084 32.424 ;
    END
  END b[5]
  PIN b[60]
    DIRECTION OUTPUT ;
    USE SIGNAL ;
    PORT
      LAYER M4 ;
        RECT  0 44.928 0.084 44.952 ;
    END
  END b[60]
  PIN b[61]
    DIRECTION OUTPUT ;
    USE SIGNAL ;
    PORT
      LAYER M4 ;
        RECT  0 45.072 0.084 45.096 ;
    END
  END b[61]
  PIN b[62]
    DIRECTION OUTPUT ;
    USE SIGNAL ;
    PORT
      LAYER M4 ;
        RECT  0 45.216 0.084 45.24 ;
    END
  END b[62]
  PIN b[63]
    DIRECTION OUTPUT ;
    USE SIGNAL ;
    PORT
      LAYER M4 ;
        RECT  0 45.36 0.084 45.384 ;
    END
  END b[63]
  PIN b[64]
    DIRECTION OUTPUT ;
    USE SIGNAL ;
    PORT
      LAYER M4 ;
        RECT  0 78.912 0.084 78.936 ;
    END
  END b[64]
  PIN b[65]
    DIRECTION OUTPUT ;
    USE SIGNAL ;
    PORT
      LAYER M4 ;
        RECT  0 79.056 0.084 79.08 ;
    END
  END b[65]
  PIN b[66]
    DIRECTION OUTPUT ;
    USE SIGNAL ;
    PORT
      LAYER M4 ;
        RECT  0 79.2 0.084 79.224 ;
    END
  END b[66]
  PIN b[67]
    DIRECTION OUTPUT ;
    USE SIGNAL ;
    PORT
      LAYER M4 ;
        RECT  0 79.344 0.084 79.368 ;
    END
  END b[67]
  PIN b[68]
    DIRECTION OUTPUT ;
    USE SIGNAL ;
    PORT
      LAYER M4 ;
        RECT  0 79.488 0.084 79.512 ;
    END
  END b[68]
  PIN b[69]
    DIRECTION OUTPUT ;
    USE SIGNAL ;
    PORT
      LAYER M4 ;
        RECT  0 79.632 0.084 79.656 ;
    END
  END b[69]
  PIN b[6]
    DIRECTION OUTPUT ;
    USE SIGNAL ;
    PORT
      LAYER M4 ;
        RECT  0 32.544 0.084 32.568 ;
    END
  END b[6]
  PIN b[70]
    DIRECTION OUTPUT ;
    USE SIGNAL ;
    PORT
      LAYER M4 ;
        RECT  0 79.776 0.084 79.8 ;
    END
  END b[70]
  PIN b[71]
    DIRECTION OUTPUT ;
    USE SIGNAL ;
    PORT
      LAYER M4 ;
        RECT  0 79.92 0.084 79.944 ;
    END
  END b[71]
  PIN b[72]
    DIRECTION OUTPUT ;
    USE SIGNAL ;
    PORT
      LAYER M4 ;
        RECT  0 80.064 0.084 80.088 ;
    END
  END b[72]
  PIN b[73]
    DIRECTION OUTPUT ;
    USE SIGNAL ;
    PORT
      LAYER M4 ;
        RECT  0 80.208 0.084 80.232 ;
    END
  END b[73]
  PIN b[74]
    DIRECTION OUTPUT ;
    USE SIGNAL ;
    PORT
      LAYER M4 ;
        RECT  0 80.352 0.084 80.376 ;
    END
  END b[74]
  PIN b[75]
    DIRECTION OUTPUT ;
    USE SIGNAL ;
    PORT
      LAYER M4 ;
        RECT  0 80.496 0.084 80.52 ;
    END
  END b[75]
  PIN b[76]
    DIRECTION OUTPUT ;
    USE SIGNAL ;
    PORT
      LAYER M4 ;
        RECT  0 80.64 0.084 80.664 ;
    END
  END b[76]
  PIN b[77]
    DIRECTION OUTPUT ;
    USE SIGNAL ;
    PORT
      LAYER M4 ;
        RECT  0 80.784 0.084 80.808 ;
    END
  END b[77]
  PIN b[78]
    DIRECTION OUTPUT ;
    USE SIGNAL ;
    PORT
      LAYER M4 ;
        RECT  0 80.928 0.084 80.952 ;
    END
  END b[78]
  PIN b[79]
    DIRECTION OUTPUT ;
    USE SIGNAL ;
    PORT
      LAYER M4 ;
        RECT  0 81.072 0.084 81.096 ;
    END
  END b[79]
  PIN b[7]
    DIRECTION OUTPUT ;
    USE SIGNAL ;
    PORT
      LAYER M4 ;
        RECT  0 32.688 0.084 32.712 ;
    END
  END b[7]
  PIN b[80]
    DIRECTION OUTPUT ;
    USE SIGNAL ;
    PORT
      LAYER M4 ;
        RECT  0 81.216 0.084 81.24 ;
    END
  END b[80]
  PIN b[81]
    DIRECTION OUTPUT ;
    USE SIGNAL ;
    PORT
      LAYER M4 ;
        RECT  0 81.36 0.084 81.384 ;
    END
  END b[81]
  PIN b[82]
    DIRECTION OUTPUT ;
    USE SIGNAL ;
    PORT
      LAYER M4 ;
        RECT  0 81.504 0.084 81.528 ;
    END
  END b[82]
  PIN b[83]
    DIRECTION OUTPUT ;
    USE SIGNAL ;
    PORT
      LAYER M4 ;
        RECT  0 81.648 0.084 81.672 ;
    END
  END b[83]
  PIN b[84]
    DIRECTION OUTPUT ;
    USE SIGNAL ;
    PORT
      LAYER M4 ;
        RECT  0 81.792 0.084 81.816 ;
    END
  END b[84]
  PIN b[85]
    DIRECTION OUTPUT ;
    USE SIGNAL ;
    PORT
      LAYER M4 ;
        RECT  0 81.936 0.084 81.96 ;
    END
  END b[85]
  PIN b[86]
    DIRECTION OUTPUT ;
    USE SIGNAL ;
    PORT
      LAYER M4 ;
        RECT  0 82.08 0.084 82.104 ;
    END
  END b[86]
  PIN b[87]
    DIRECTION OUTPUT ;
    USE SIGNAL ;
    PORT
      LAYER M4 ;
        RECT  0 82.224 0.084 82.248 ;
    END
  END b[87]
  PIN b[88]
    DIRECTION OUTPUT ;
    USE SIGNAL ;
    PORT
      LAYER M4 ;
        RECT  0 82.368 0.084 82.392 ;
    END
  END b[88]
  PIN b[89]
    DIRECTION OUTPUT ;
    USE SIGNAL ;
    PORT
      LAYER M4 ;
        RECT  0 82.512 0.084 82.536 ;
    END
  END b[89]
  PIN b[8]
    DIRECTION OUTPUT ;
    USE SIGNAL ;
    PORT
      LAYER M4 ;
        RECT  0 32.832 0.084 32.856 ;
    END
  END b[8]
  PIN b[90]
    DIRECTION OUTPUT ;
    USE SIGNAL ;
    PORT
      LAYER M4 ;
        RECT  0 82.656 0.084 82.68 ;
    END
  END b[90]
  PIN b[91]
    DIRECTION OUTPUT ;
    USE SIGNAL ;
    PORT
      LAYER M4 ;
        RECT  0 82.8 0.084 82.824 ;
    END
  END b[91]
  PIN b[92]
    DIRECTION OUTPUT ;
    USE SIGNAL ;
    PORT
      LAYER M4 ;
        RECT  0 82.944 0.084 82.968 ;
    END
  END b[92]
  PIN b[93]
    DIRECTION OUTPUT ;
    USE SIGNAL ;
    PORT
      LAYER M4 ;
        RECT  0 83.088 0.084 83.112 ;
    END
  END b[93]
  PIN b[94]
    DIRECTION OUTPUT ;
    USE SIGNAL ;
    PORT
      LAYER M4 ;
        RECT  0 83.232 0.084 83.256 ;
    END
  END b[94]
  PIN b[95]
    DIRECTION OUTPUT ;
    USE SIGNAL ;
    PORT
      LAYER M4 ;
        RECT  0 83.376 0.084 83.4 ;
    END
  END b[95]
  PIN b[96]
    DIRECTION OUTPUT ;
    USE SIGNAL ;
    PORT
      LAYER M4 ;
        RECT  0 84.672 0.084 84.696 ;
    END
  END b[96]
  PIN b[97]
    DIRECTION OUTPUT ;
    USE SIGNAL ;
    PORT
      LAYER M4 ;
        RECT  0 84.816 0.084 84.84 ;
    END
  END b[97]
  PIN b[98]
    DIRECTION OUTPUT ;
    USE SIGNAL ;
    PORT
      LAYER M4 ;
        RECT  0 84.96 0.084 84.984 ;
    END
  END b[98]
  PIN b[99]
    DIRECTION OUTPUT ;
    USE SIGNAL ;
    PORT
      LAYER M4 ;
        RECT  0 85.104 0.084 85.128 ;
    END
  END b[99]
  PIN b[9]
    DIRECTION OUTPUT ;
    USE SIGNAL ;
    PORT
      LAYER M4 ;
        RECT  0 32.976 0.084 33 ;
    END
  END b[9]
  PIN ck
    DIRECTION INPUT ;
    USE SIGNAL ;
    PORT
      LAYER M3 ;
        RECT  37.908 170.603 37.926 170.64 ;
    END
  END ck
  PIN ck_s
    DIRECTION INPUT ;
    USE SIGNAL ;
    PORT
      LAYER M3 ;
        RECT  38.016 170.603 38.034 170.64 ;
    END
  END ck_s
  PIN en
    DIRECTION INPUT ;
    USE SIGNAL ;
    PORT
      LAYER M3 ;
        RECT  38.124 170.603 38.142 170.64 ;
    END
  END en
  PIN fault
    DIRECTION OUTPUT ;
    USE SIGNAL ;
    PORT
      LAYER M3 ;
        RECT  38.232 170.603 38.25 170.64 ;
    END
  END fault
  PIN k0
    DIRECTION INPUT ;
    USE SIGNAL ;
    PORT
      LAYER M3 ;
        RECT  38.34 170.603 38.358 170.64 ;
    END
  END k0
  PIN k1
    DIRECTION INPUT ;
    USE SIGNAL ;
    PORT
      LAYER M3 ;
        RECT  38.448 170.603 38.466 170.64 ;
    END
  END k1
  PIN k2
    DIRECTION INPUT ;
    USE SIGNAL ;
    PORT
      LAYER M3 ;
        RECT  38.556 170.603 38.574 170.64 ;
    END
  END k2
  PIN k3
    DIRECTION INPUT ;
    USE SIGNAL ;
    PORT
      LAYER M3 ;
        RECT  38.664 170.603 38.682 170.64 ;
    END
  END k3
  PIN rs
    DIRECTION INPUT ;
    USE SIGNAL ;
    PORT
      LAYER M3 ;
        RECT  38.772 170.603 38.79 170.64 ;
    END
  END rs
  PIN tie_hi
    DIRECTION OUTPUT ;
    USE SIGNAL ;
    PORT
      LAYER M3 ;
        RECT  38.88 170.603 38.898 170.64 ;
    END
  END tie_hi
  PIN tie_lo
    DIRECTION OUTPUT ;
    USE SIGNAL ;
    PORT
      LAYER M3 ;
        RECT  38.988 170.603 39.006 170.64 ;
    END
  END tie_lo
  PIN VDD
    DIRECTION INOUT ;
    USE POWER ;
    PORT
      LAYER M5 ;
        RECT  94.392 2.151 94.512 168.489 ;
        RECT  91.692 2.151 91.812 168.489 ;
        RECT  88.992 2.151 89.112 168.489 ;
        RECT  86.292 2.151 86.412 168.489 ;
        RECT  83.592 2.151 83.712 168.489 ;
        RECT  80.892 2.151 81.012 168.489 ;
        RECT  78.192 2.151 78.312 168.489 ;
        RECT  75.492 2.151 75.612 168.489 ;
        RECT  72.792 2.151 72.912 168.489 ;
        RECT  70.092 2.151 70.212 168.489 ;
        RECT  67.392 2.151 67.512 168.489 ;
        RECT  64.692 2.151 64.812 168.489 ;
        RECT  61.992 2.151 62.112 168.489 ;
        RECT  59.292 2.151 59.412 168.489 ;
        RECT  56.592 2.151 56.712 168.489 ;
        RECT  53.892 2.151 54.012 168.489 ;
        RECT  51.192 2.151 51.312 168.489 ;
        RECT  48.492 2.151 48.612 168.489 ;
        RECT  45.792 2.151 45.912 168.489 ;
        RECT  43.092 2.151 43.212 168.489 ;
        RECT  40.392 2.151 40.512 168.489 ;
        RECT  37.692 2.151 37.812 168.489 ;
        RECT  34.992 2.151 35.112 168.489 ;
        RECT  32.292 2.151 32.412 168.489 ;
        RECT  29.592 2.151 29.712 168.489 ;
        RECT  26.892 2.151 27.012 168.489 ;
        RECT  24.192 2.151 24.312 168.489 ;
        RECT  21.492 2.151 21.612 168.489 ;
        RECT  18.792 2.151 18.912 168.489 ;
        RECT  16.092 2.151 16.212 168.489 ;
        RECT  13.392 2.151 13.512 168.489 ;
        RECT  10.692 2.151 10.812 168.489 ;
        RECT  7.992 2.151 8.112 168.489 ;
        RECT  5.292 2.151 5.412 168.489 ;
        RECT  2.592 2.151 2.712 168.489 ;
    END
  END VDD
  PIN VSS
    DIRECTION INOUT ;
    USE GROUND ;
    PORT
      LAYER M5 ;
        RECT  94.2 2.137 94.32 168.503 ;
        RECT  91.5 2.137 91.62 168.503 ;
        RECT  88.8 2.137 88.92 168.503 ;
        RECT  86.1 2.137 86.22 168.503 ;
        RECT  83.4 2.137 83.52 168.503 ;
        RECT  80.7 2.137 80.82 168.503 ;
        RECT  78 2.137 78.12 168.503 ;
        RECT  75.3 2.137 75.42 168.503 ;
        RECT  72.6 2.137 72.72 168.503 ;
        RECT  69.9 2.137 70.02 168.503 ;
        RECT  67.2 2.137 67.32 168.503 ;
        RECT  64.5 2.137 64.62 168.503 ;
        RECT  61.8 2.137 61.92 168.503 ;
        RECT  59.1 2.137 59.22 168.503 ;
        RECT  56.4 2.137 56.52 168.503 ;
        RECT  53.7 2.137 53.82 168.503 ;
        RECT  51 2.137 51.12 168.503 ;
        RECT  48.3 2.137 48.42 168.503 ;
        RECT  45.6 2.137 45.72 168.503 ;
        RECT  42.9 2.137 43.02 168.503 ;
        RECT  40.2 2.137 40.32 168.503 ;
        RECT  37.5 2.137 37.62 168.503 ;
        RECT  34.8 2.137 34.92 168.503 ;
        RECT  32.1 2.137 32.22 168.503 ;
        RECT  29.4 2.137 29.52 168.503 ;
        RECT  26.7 2.137 26.82 168.503 ;
        RECT  24 2.137 24.12 168.503 ;
        RECT  21.3 2.137 21.42 168.503 ;
        RECT  18.6 2.137 18.72 168.503 ;
        RECT  15.9 2.137 16.02 168.503 ;
        RECT  13.2 2.137 13.32 168.503 ;
        RECT  10.5 2.137 10.62 168.503 ;
        RECT  7.8 2.137 7.92 168.503 ;
        RECT  5.1 2.137 5.22 168.503 ;
        RECT  2.4 2.137 2.52 168.503 ;
    END
  END VSS
  OBS
    LAYER RVTN ;
     RECT  2.16 2.16 96.12 2.295 ;
     RECT  2.16 2.565 96.12 2.835 ;
     RECT  2.16 3.105 96.12 3.375 ;
     RECT  2.16 3.645 96.12 3.915 ;
     RECT  2.16 4.185 96.12 4.455 ;
     RECT  2.16 4.725 96.12 4.995 ;
     RECT  2.16 5.265 96.12 5.535 ;
     RECT  2.16 5.805 96.12 6.075 ;
     RECT  2.16 6.345 96.12 6.615 ;
     RECT  2.16 6.885 96.12 7.155 ;
     RECT  2.16 7.425 96.12 7.695 ;
     RECT  2.16 7.965 96.12 8.235 ;
     RECT  2.16 8.505 96.12 8.775 ;
     RECT  2.16 9.045 96.12 9.315 ;
     RECT  2.16 9.585 96.12 9.855 ;
     RECT  2.16 10.125 96.12 10.395 ;
     RECT  2.16 10.665 96.12 10.935 ;
     RECT  2.16 11.205 96.12 11.475 ;
     RECT  2.16 11.745 96.12 12.015 ;
     RECT  2.16 12.285 96.12 12.555 ;
     RECT  2.16 12.825 96.12 13.095 ;
     RECT  2.16 13.365 96.12 13.635 ;
     RECT  2.16 13.905 96.12 14.175 ;
     RECT  2.16 14.445 96.12 14.715 ;
     RECT  2.16 14.985 96.12 15.255 ;
     RECT  2.16 15.525 96.12 15.795 ;
     RECT  2.16 16.065 96.12 16.335 ;
     RECT  2.16 16.605 96.12 16.875 ;
     RECT  2.16 17.145 96.12 17.415 ;
     RECT  2.16 17.685 96.12 17.955 ;
     RECT  2.16 18.225 96.12 18.495 ;
     RECT  2.16 18.765 96.12 19.035 ;
     RECT  2.16 19.305 96.12 19.575 ;
     RECT  2.16 19.845 96.12 20.115 ;
     RECT  2.16 20.385 96.12 20.655 ;
     RECT  2.16 20.925 96.12 21.195 ;
     RECT  2.16 21.465 96.12 21.735 ;
     RECT  2.16 22.005 96.12 22.275 ;
     RECT  2.16 22.545 96.12 22.815 ;
     RECT  2.16 23.085 96.12 23.355 ;
     RECT  2.16 23.625 96.12 23.895 ;
     RECT  2.16 24.165 96.12 24.435 ;
     RECT  2.16 24.705 96.12 24.975 ;
     RECT  2.16 25.245 96.12 25.515 ;
     RECT  2.16 25.785 96.12 26.055 ;
     RECT  2.16 26.325 96.12 26.595 ;
     RECT  2.16 26.865 96.12 27.135 ;
     RECT  2.16 27.405 96.12 27.675 ;
     RECT  2.16 27.945 96.12 28.215 ;
     RECT  2.16 28.485 96.12 28.755 ;
     RECT  2.16 29.025 96.12 29.295 ;
     RECT  2.16 29.565 96.12 29.835 ;
     RECT  2.16 30.105 96.12 30.375 ;
     RECT  2.16 30.645 96.12 30.915 ;
     RECT  2.16 31.185 96.12 31.455 ;
     RECT  2.16 31.725 96.12 31.995 ;
     RECT  2.16 32.265 96.12 32.535 ;
     RECT  2.16 32.805 96.12 33.075 ;
     RECT  2.16 33.345 96.12 33.615 ;
     RECT  2.16 33.885 96.12 34.155 ;
     RECT  2.16 34.425 96.12 34.695 ;
     RECT  2.16 34.965 96.12 35.235 ;
     RECT  2.16 35.505 96.12 35.775 ;
     RECT  2.16 36.045 96.12 36.315 ;
     RECT  2.16 36.585 96.12 36.855 ;
     RECT  2.16 37.125 96.12 37.395 ;
     RECT  2.16 37.665 96.12 37.935 ;
     RECT  2.16 38.205 96.12 38.475 ;
     RECT  2.16 38.745 96.12 39.015 ;
     RECT  2.16 39.285 96.12 39.555 ;
     RECT  2.16 39.825 96.12 40.095 ;
     RECT  2.16 40.365 96.12 40.635 ;
     RECT  2.16 40.905 96.12 41.04 ;
     RECT  2.16 41.04 41.148 41.175 ;
     RECT  77.22 41.04 96.12 41.175 ;
     RECT  2.16 41.445 41.148 41.715 ;
     RECT  77.22 41.445 96.12 41.715 ;
     RECT  2.16 41.985 41.148 42.255 ;
     RECT  77.22 41.985 96.12 42.255 ;
     RECT  2.16 42.525 41.148 42.795 ;
     RECT  77.22 42.525 96.12 42.795 ;
     RECT  2.16 43.065 41.148 43.335 ;
     RECT  77.22 43.065 96.12 43.335 ;
     RECT  2.16 43.605 41.148 43.875 ;
     RECT  77.22 43.605 96.12 43.875 ;
     RECT  2.16 44.145 41.148 44.415 ;
     RECT  77.22 44.145 96.12 44.415 ;
     RECT  2.16 44.685 41.148 44.955 ;
     RECT  77.22 44.685 96.12 44.955 ;
     RECT  2.16 45.225 41.148 45.495 ;
     RECT  77.22 45.225 96.12 45.495 ;
     RECT  2.16 45.765 41.148 46.035 ;
     RECT  77.22 45.765 96.12 46.035 ;
     RECT  2.16 46.305 41.148 46.575 ;
     RECT  77.22 46.305 96.12 46.575 ;
     RECT  2.16 46.845 41.148 47.115 ;
     RECT  77.22 46.845 96.12 47.115 ;
     RECT  2.16 47.385 41.148 47.655 ;
     RECT  77.22 47.385 96.12 47.655 ;
     RECT  2.16 47.925 41.148 48.195 ;
     RECT  77.22 47.925 96.12 48.195 ;
     RECT  2.16 48.465 41.148 48.735 ;
     RECT  77.22 48.465 96.12 48.735 ;
     RECT  2.16 49.005 41.148 49.275 ;
     RECT  77.22 49.005 96.12 49.275 ;
     RECT  2.16 49.545 41.148 49.815 ;
     RECT  77.22 49.545 96.12 49.815 ;
     RECT  2.16 50.085 41.148 50.355 ;
     RECT  77.22 50.085 96.12 50.355 ;
     RECT  2.16 50.625 41.148 50.895 ;
     RECT  77.22 50.625 96.12 50.895 ;
     RECT  2.16 51.165 41.148 51.435 ;
     RECT  77.22 51.165 96.12 51.435 ;
     RECT  2.16 51.705 41.148 51.975 ;
     RECT  77.22 51.705 96.12 51.975 ;
     RECT  2.16 52.245 41.148 52.515 ;
     RECT  77.22 52.245 96.12 52.515 ;
     RECT  2.16 52.785 41.148 53.055 ;
     RECT  77.22 52.785 96.12 53.055 ;
     RECT  2.16 53.325 41.148 53.595 ;
     RECT  77.22 53.325 96.12 53.595 ;
     RECT  2.16 53.865 41.148 54.135 ;
     RECT  77.22 53.865 96.12 54.135 ;
     RECT  2.16 54.405 41.148 54.675 ;
     RECT  77.22 54.405 96.12 54.675 ;
     RECT  2.16 54.945 41.148 55.215 ;
     RECT  77.22 54.945 96.12 55.215 ;
     RECT  2.16 55.485 41.148 55.755 ;
     RECT  77.22 55.485 96.12 55.755 ;
     RECT  2.16 56.025 41.148 56.295 ;
     RECT  77.22 56.025 96.12 56.295 ;
     RECT  2.16 56.565 41.148 56.835 ;
     RECT  77.22 56.565 96.12 56.835 ;
     RECT  2.16 57.105 41.148 57.375 ;
     RECT  77.22 57.105 96.12 57.375 ;
     RECT  2.16 57.645 41.148 57.915 ;
     RECT  77.22 57.645 96.12 57.915 ;
     RECT  2.16 58.185 41.148 58.455 ;
     RECT  77.22 58.185 96.12 58.455 ;
     RECT  2.16 58.725 41.148 58.995 ;
     RECT  77.22 58.725 96.12 58.995 ;
     RECT  2.16 59.265 41.148 59.535 ;
     RECT  77.22 59.265 96.12 59.535 ;
     RECT  2.16 59.805 41.148 60.075 ;
     RECT  77.22 59.805 96.12 60.075 ;
     RECT  2.16 60.345 41.148 60.615 ;
     RECT  77.22 60.345 96.12 60.615 ;
     RECT  2.16 60.885 41.148 61.155 ;
     RECT  77.22 60.885 96.12 61.155 ;
     RECT  2.16 61.425 41.148 61.695 ;
     RECT  77.22 61.425 96.12 61.695 ;
     RECT  2.16 61.965 41.148 62.235 ;
     RECT  77.22 61.965 96.12 62.235 ;
     RECT  2.16 62.505 41.148 62.64 ;
     RECT  77.22 62.505 96.12 62.64 ;
     RECT  2.16 62.64 96.12 62.775 ;
     RECT  2.16 63.045 96.12 63.315 ;
     RECT  2.16 63.585 96.12 63.855 ;
     RECT  2.16 64.125 96.12 64.395 ;
     RECT  2.16 64.665 96.12 64.935 ;
     RECT  2.16 65.205 96.12 65.475 ;
     RECT  2.16 65.745 96.12 66.015 ;
     RECT  2.16 66.285 96.12 66.555 ;
     RECT  2.16 66.825 96.12 67.095 ;
     RECT  2.16 67.365 96.12 67.635 ;
     RECT  2.16 67.905 96.12 68.175 ;
     RECT  2.16 68.445 96.12 68.715 ;
     RECT  2.16 68.985 96.12 69.255 ;
     RECT  2.16 69.525 96.12 69.795 ;
     RECT  2.16 70.065 96.12 70.335 ;
     RECT  2.16 70.605 96.12 70.875 ;
     RECT  2.16 71.145 96.12 71.415 ;
     RECT  2.16 71.685 96.12 71.955 ;
     RECT  2.16 72.225 96.12 72.495 ;
     RECT  2.16 72.765 96.12 73.035 ;
     RECT  2.16 73.305 96.12 73.575 ;
     RECT  2.16 73.845 96.12 74.115 ;
     RECT  2.16 74.385 96.12 74.655 ;
     RECT  2.16 74.925 96.12 75.195 ;
     RECT  2.16 75.465 96.12 75.735 ;
     RECT  2.16 76.005 96.12 76.275 ;
     RECT  2.16 76.545 96.12 76.815 ;
     RECT  2.16 77.085 96.12 77.355 ;
     RECT  2.16 77.625 96.12 77.895 ;
     RECT  2.16 78.165 96.12 78.435 ;
     RECT  2.16 78.705 96.12 78.975 ;
     RECT  2.16 79.245 96.12 79.515 ;
     RECT  2.16 79.785 96.12 80.055 ;
     RECT  2.16 80.325 96.12 80.595 ;
     RECT  2.16 80.865 96.12 81.135 ;
     RECT  2.16 81.405 96.12 81.675 ;
     RECT  2.16 81.945 96.12 82.215 ;
     RECT  2.16 82.485 96.12 82.755 ;
     RECT  2.16 83.025 96.12 83.295 ;
     RECT  2.16 83.565 96.12 83.835 ;
     RECT  2.16 84.105 96.12 84.24 ;
     RECT  2.16 84.24 41.148 84.375 ;
     RECT  77.22 84.24 96.12 84.375 ;
     RECT  2.16 84.645 41.148 84.915 ;
     RECT  77.22 84.645 96.12 84.915 ;
     RECT  2.16 85.185 41.148 85.455 ;
     RECT  77.22 85.185 96.12 85.455 ;
     RECT  2.16 85.725 41.148 85.995 ;
     RECT  77.22 85.725 96.12 85.995 ;
     RECT  2.16 86.265 41.148 86.535 ;
     RECT  77.22 86.265 96.12 86.535 ;
     RECT  2.16 86.805 41.148 87.075 ;
     RECT  77.22 86.805 96.12 87.075 ;
     RECT  2.16 87.345 41.148 87.615 ;
     RECT  77.22 87.345 96.12 87.615 ;
     RECT  2.16 87.885 41.148 88.155 ;
     RECT  77.22 87.885 96.12 88.155 ;
     RECT  2.16 88.425 41.148 88.695 ;
     RECT  77.22 88.425 96.12 88.695 ;
     RECT  2.16 88.965 41.148 89.235 ;
     RECT  77.22 88.965 96.12 89.235 ;
     RECT  2.16 89.505 41.148 89.775 ;
     RECT  77.22 89.505 96.12 89.775 ;
     RECT  2.16 90.045 41.148 90.315 ;
     RECT  77.22 90.045 96.12 90.315 ;
     RECT  2.16 90.585 41.148 90.855 ;
     RECT  77.22 90.585 96.12 90.855 ;
     RECT  2.16 91.125 41.148 91.395 ;
     RECT  77.22 91.125 96.12 91.395 ;
     RECT  2.16 91.665 41.148 91.935 ;
     RECT  77.22 91.665 96.12 91.935 ;
     RECT  2.16 92.205 41.148 92.475 ;
     RECT  77.22 92.205 96.12 92.475 ;
     RECT  2.16 92.745 41.148 93.015 ;
     RECT  77.22 92.745 96.12 93.015 ;
     RECT  2.16 93.285 41.148 93.555 ;
     RECT  77.22 93.285 96.12 93.555 ;
     RECT  2.16 93.825 41.148 94.095 ;
     RECT  77.22 93.825 96.12 94.095 ;
     RECT  2.16 94.365 41.148 94.635 ;
     RECT  77.22 94.365 96.12 94.635 ;
     RECT  2.16 94.905 41.148 95.175 ;
     RECT  77.22 94.905 96.12 95.175 ;
     RECT  2.16 95.445 41.148 95.715 ;
     RECT  77.22 95.445 96.12 95.715 ;
     RECT  2.16 95.985 41.148 96.255 ;
     RECT  77.22 95.985 96.12 96.255 ;
     RECT  2.16 96.525 41.148 96.795 ;
     RECT  77.22 96.525 96.12 96.795 ;
     RECT  2.16 97.065 41.148 97.335 ;
     RECT  77.22 97.065 96.12 97.335 ;
     RECT  2.16 97.605 41.148 97.875 ;
     RECT  77.22 97.605 96.12 97.875 ;
     RECT  2.16 98.145 41.148 98.415 ;
     RECT  77.22 98.145 96.12 98.415 ;
     RECT  2.16 98.685 41.148 98.955 ;
     RECT  77.22 98.685 96.12 98.955 ;
     RECT  2.16 99.225 41.148 99.495 ;
     RECT  77.22 99.225 96.12 99.495 ;
     RECT  2.16 99.765 41.148 100.035 ;
     RECT  77.22 99.765 96.12 100.035 ;
     RECT  2.16 100.305 41.148 100.575 ;
     RECT  77.22 100.305 96.12 100.575 ;
     RECT  2.16 100.845 41.148 101.115 ;
     RECT  77.22 100.845 96.12 101.115 ;
     RECT  2.16 101.385 41.148 101.655 ;
     RECT  77.22 101.385 96.12 101.655 ;
     RECT  2.16 101.925 41.148 102.195 ;
     RECT  77.22 101.925 96.12 102.195 ;
     RECT  2.16 102.465 41.148 102.735 ;
     RECT  77.22 102.465 96.12 102.735 ;
     RECT  2.16 103.005 41.148 103.275 ;
     RECT  77.22 103.005 96.12 103.275 ;
     RECT  2.16 103.545 41.148 103.815 ;
     RECT  77.22 103.545 96.12 103.815 ;
     RECT  2.16 104.085 41.148 104.355 ;
     RECT  77.22 104.085 96.12 104.355 ;
     RECT  2.16 104.625 41.148 104.895 ;
     RECT  77.22 104.625 96.12 104.895 ;
     RECT  2.16 105.165 41.148 105.435 ;
     RECT  77.22 105.165 96.12 105.435 ;
     RECT  2.16 105.705 41.148 105.84 ;
     RECT  77.22 105.705 96.12 105.84 ;
     RECT  2.16 105.84 96.12 105.975 ;
     RECT  2.16 106.245 96.12 106.515 ;
     RECT  2.16 106.785 96.12 107.055 ;
     RECT  2.16 107.325 96.12 107.595 ;
     RECT  2.16 107.865 96.12 108.135 ;
     RECT  2.16 108.405 96.12 108.675 ;
     RECT  2.16 108.945 96.12 109.215 ;
     RECT  2.16 109.485 96.12 109.755 ;
     RECT  2.16 110.025 96.12 110.295 ;
     RECT  2.16 110.565 96.12 110.835 ;
     RECT  2.16 111.105 96.12 111.375 ;
     RECT  2.16 111.645 96.12 111.915 ;
     RECT  2.16 112.185 96.12 112.455 ;
     RECT  2.16 112.725 96.12 112.995 ;
     RECT  2.16 113.265 96.12 113.535 ;
     RECT  2.16 113.805 96.12 114.075 ;
     RECT  2.16 114.345 96.12 114.615 ;
     RECT  2.16 114.885 96.12 115.155 ;
     RECT  2.16 115.425 96.12 115.695 ;
     RECT  2.16 115.965 96.12 116.235 ;
     RECT  2.16 116.505 96.12 116.775 ;
     RECT  2.16 117.045 96.12 117.315 ;
     RECT  2.16 117.585 96.12 117.855 ;
     RECT  2.16 118.125 96.12 118.395 ;
     RECT  2.16 118.665 96.12 118.935 ;
     RECT  2.16 119.205 96.12 119.475 ;
     RECT  2.16 119.745 96.12 120.015 ;
     RECT  2.16 120.285 96.12 120.555 ;
     RECT  2.16 120.825 96.12 121.095 ;
     RECT  2.16 121.365 96.12 121.635 ;
     RECT  2.16 121.905 96.12 122.175 ;
     RECT  2.16 122.445 96.12 122.715 ;
     RECT  2.16 122.985 96.12 123.255 ;
     RECT  2.16 123.525 96.12 123.795 ;
     RECT  2.16 124.065 96.12 124.335 ;
     RECT  2.16 124.605 96.12 124.875 ;
     RECT  2.16 125.145 96.12 125.415 ;
     RECT  2.16 125.685 96.12 125.955 ;
     RECT  2.16 126.225 96.12 126.495 ;
     RECT  2.16 126.765 96.12 127.035 ;
     RECT  2.16 127.305 96.12 127.44 ;
     RECT  2.16 127.44 41.148 127.575 ;
     RECT  77.22 127.44 96.12 127.575 ;
     RECT  2.16 127.845 41.148 128.115 ;
     RECT  77.22 127.845 96.12 128.115 ;
     RECT  2.16 128.385 41.148 128.655 ;
     RECT  77.22 128.385 96.12 128.655 ;
     RECT  2.16 128.925 41.148 129.195 ;
     RECT  77.22 128.925 96.12 129.195 ;
     RECT  2.16 129.465 41.148 129.735 ;
     RECT  77.22 129.465 96.12 129.735 ;
     RECT  2.16 130.005 41.148 130.275 ;
     RECT  77.22 130.005 96.12 130.275 ;
     RECT  2.16 130.545 41.148 130.815 ;
     RECT  77.22 130.545 96.12 130.815 ;
     RECT  2.16 131.085 41.148 131.355 ;
     RECT  77.22 131.085 96.12 131.355 ;
     RECT  2.16 131.625 41.148 131.895 ;
     RECT  77.22 131.625 96.12 131.895 ;
     RECT  2.16 132.165 41.148 132.435 ;
     RECT  77.22 132.165 96.12 132.435 ;
     RECT  2.16 132.705 41.148 132.975 ;
     RECT  77.22 132.705 96.12 132.975 ;
     RECT  2.16 133.245 41.148 133.515 ;
     RECT  77.22 133.245 96.12 133.515 ;
     RECT  2.16 133.785 41.148 134.055 ;
     RECT  77.22 133.785 96.12 134.055 ;
     RECT  2.16 134.325 41.148 134.595 ;
     RECT  77.22 134.325 96.12 134.595 ;
     RECT  2.16 134.865 41.148 135.135 ;
     RECT  77.22 134.865 96.12 135.135 ;
     RECT  2.16 135.405 41.148 135.675 ;
     RECT  77.22 135.405 96.12 135.675 ;
     RECT  2.16 135.945 41.148 136.215 ;
     RECT  77.22 135.945 96.12 136.215 ;
     RECT  2.16 136.485 41.148 136.755 ;
     RECT  77.22 136.485 96.12 136.755 ;
     RECT  2.16 137.025 41.148 137.295 ;
     RECT  77.22 137.025 96.12 137.295 ;
     RECT  2.16 137.565 41.148 137.835 ;
     RECT  77.22 137.565 96.12 137.835 ;
     RECT  2.16 138.105 41.148 138.375 ;
     RECT  77.22 138.105 96.12 138.375 ;
     RECT  2.16 138.645 41.148 138.915 ;
     RECT  77.22 138.645 96.12 138.915 ;
     RECT  2.16 139.185 41.148 139.455 ;
     RECT  77.22 139.185 96.12 139.455 ;
     RECT  2.16 139.725 41.148 139.995 ;
     RECT  77.22 139.725 96.12 139.995 ;
     RECT  2.16 140.265 41.148 140.535 ;
     RECT  77.22 140.265 96.12 140.535 ;
     RECT  2.16 140.805 41.148 141.075 ;
     RECT  77.22 140.805 96.12 141.075 ;
     RECT  2.16 141.345 41.148 141.615 ;
     RECT  77.22 141.345 96.12 141.615 ;
     RECT  2.16 141.885 41.148 142.155 ;
     RECT  77.22 141.885 96.12 142.155 ;
     RECT  2.16 142.425 41.148 142.695 ;
     RECT  77.22 142.425 96.12 142.695 ;
     RECT  2.16 142.965 41.148 143.235 ;
     RECT  77.22 142.965 96.12 143.235 ;
     RECT  2.16 143.505 41.148 143.775 ;
     RECT  77.22 143.505 96.12 143.775 ;
     RECT  2.16 144.045 41.148 144.315 ;
     RECT  77.22 144.045 96.12 144.315 ;
     RECT  2.16 144.585 41.148 144.855 ;
     RECT  77.22 144.585 96.12 144.855 ;
     RECT  2.16 145.125 41.148 145.395 ;
     RECT  77.22 145.125 96.12 145.395 ;
     RECT  2.16 145.665 41.148 145.935 ;
     RECT  77.22 145.665 96.12 145.935 ;
     RECT  2.16 146.205 41.148 146.475 ;
     RECT  77.22 146.205 96.12 146.475 ;
     RECT  2.16 146.745 41.148 147.015 ;
     RECT  77.22 146.745 96.12 147.015 ;
     RECT  2.16 147.285 41.148 147.555 ;
     RECT  77.22 147.285 96.12 147.555 ;
     RECT  2.16 147.825 41.148 148.095 ;
     RECT  77.22 147.825 96.12 148.095 ;
     RECT  2.16 148.365 41.148 148.635 ;
     RECT  77.22 148.365 96.12 148.635 ;
     RECT  2.16 148.905 41.148 149.04 ;
     RECT  77.22 148.905 96.12 149.04 ;
     RECT  2.16 149.04 96.12 149.175 ;
     RECT  2.16 149.445 96.12 149.715 ;
     RECT  2.16 149.985 96.12 150.255 ;
     RECT  2.16 150.525 96.12 150.795 ;
     RECT  2.16 151.065 96.12 151.335 ;
     RECT  2.16 151.605 96.12 151.875 ;
     RECT  2.16 152.145 96.12 152.415 ;
     RECT  2.16 152.685 96.12 152.955 ;
     RECT  2.16 153.225 96.12 153.495 ;
     RECT  2.16 153.765 96.12 154.035 ;
     RECT  2.16 154.305 96.12 154.575 ;
     RECT  2.16 154.845 96.12 155.115 ;
     RECT  2.16 155.385 96.12 155.655 ;
     RECT  2.16 155.925 96.12 156.195 ;
     RECT  2.16 156.465 96.12 156.735 ;
     RECT  2.16 157.005 96.12 157.275 ;
     RECT  2.16 157.545 96.12 157.815 ;
     RECT  2.16 158.085 96.12 158.355 ;
     RECT  2.16 158.625 96.12 158.895 ;
     RECT  2.16 159.165 96.12 159.435 ;
     RECT  2.16 159.705 96.12 159.975 ;
     RECT  2.16 160.245 96.12 160.515 ;
     RECT  2.16 160.785 96.12 161.055 ;
     RECT  2.16 161.325 96.12 161.595 ;
     RECT  2.16 161.865 96.12 162.135 ;
     RECT  2.16 162.405 96.12 162.675 ;
     RECT  2.16 162.945 96.12 163.215 ;
     RECT  2.16 163.485 96.12 163.755 ;
     RECT  2.16 164.025 96.12 164.295 ;
     RECT  2.16 164.565 96.12 164.835 ;
     RECT  2.16 165.105 96.12 165.375 ;
     RECT  2.16 165.645 96.12 165.915 ;
     RECT  2.16 166.185 96.12 166.455 ;
     RECT  2.16 166.725 96.12 166.995 ;
     RECT  2.16 167.265 96.12 167.535 ;
     RECT  2.16 167.805 96.12 168.075 ;
     RECT  2.16 168.345 96.12 168.48 ;
    LAYER RVTP ;
     RECT  2.16 2.295 96.12 2.565 ;
     RECT  2.16 2.835 96.12 3.105 ;
     RECT  2.16 3.375 96.12 3.645 ;
     RECT  2.16 3.915 96.12 4.185 ;
     RECT  2.16 4.455 96.12 4.725 ;
     RECT  2.16 4.995 96.12 5.265 ;
     RECT  2.16 5.535 96.12 5.805 ;
     RECT  2.16 6.075 96.12 6.345 ;
     RECT  2.16 6.615 96.12 6.885 ;
     RECT  2.16 7.155 96.12 7.425 ;
     RECT  2.16 7.695 96.12 7.965 ;
     RECT  2.16 8.235 96.12 8.505 ;
     RECT  2.16 8.775 96.12 9.045 ;
     RECT  2.16 9.315 96.12 9.585 ;
     RECT  2.16 9.855 96.12 10.125 ;
     RECT  2.16 10.395 96.12 10.665 ;
     RECT  2.16 10.935 96.12 11.205 ;
     RECT  2.16 11.475 96.12 11.745 ;
     RECT  2.16 12.015 96.12 12.285 ;
     RECT  2.16 12.555 96.12 12.825 ;
     RECT  2.16 13.095 96.12 13.365 ;
     RECT  2.16 13.635 96.12 13.905 ;
     RECT  2.16 14.175 96.12 14.445 ;
     RECT  2.16 14.715 96.12 14.985 ;
     RECT  2.16 15.255 96.12 15.525 ;
     RECT  2.16 15.795 96.12 16.065 ;
     RECT  2.16 16.335 96.12 16.605 ;
     RECT  2.16 16.875 96.12 17.145 ;
     RECT  2.16 17.415 96.12 17.685 ;
     RECT  2.16 17.955 96.12 18.225 ;
     RECT  2.16 18.495 96.12 18.765 ;
     RECT  2.16 19.035 96.12 19.305 ;
     RECT  2.16 19.575 96.12 19.845 ;
     RECT  2.16 20.115 96.12 20.385 ;
     RECT  2.16 20.655 96.12 20.925 ;
     RECT  2.16 21.195 96.12 21.465 ;
     RECT  2.16 21.735 96.12 22.005 ;
     RECT  2.16 22.275 96.12 22.545 ;
     RECT  2.16 22.815 96.12 23.085 ;
     RECT  2.16 23.355 96.12 23.625 ;
     RECT  2.16 23.895 96.12 24.165 ;
     RECT  2.16 24.435 96.12 24.705 ;
     RECT  2.16 24.975 96.12 25.245 ;
     RECT  2.16 25.515 96.12 25.785 ;
     RECT  2.16 26.055 96.12 26.325 ;
     RECT  2.16 26.595 96.12 26.865 ;
     RECT  2.16 27.135 96.12 27.405 ;
     RECT  2.16 27.675 96.12 27.945 ;
     RECT  2.16 28.215 96.12 28.485 ;
     RECT  2.16 28.755 96.12 29.025 ;
     RECT  2.16 29.295 96.12 29.565 ;
     RECT  2.16 29.835 96.12 30.105 ;
     RECT  2.16 30.375 96.12 30.645 ;
     RECT  2.16 30.915 96.12 31.185 ;
     RECT  2.16 31.455 96.12 31.725 ;
     RECT  2.16 31.995 96.12 32.265 ;
     RECT  2.16 32.535 96.12 32.805 ;
     RECT  2.16 33.075 96.12 33.345 ;
     RECT  2.16 33.615 96.12 33.885 ;
     RECT  2.16 34.155 96.12 34.425 ;
     RECT  2.16 34.695 96.12 34.965 ;
     RECT  2.16 35.235 96.12 35.505 ;
     RECT  2.16 35.775 96.12 36.045 ;
     RECT  2.16 36.315 96.12 36.585 ;
     RECT  2.16 36.855 96.12 37.125 ;
     RECT  2.16 37.395 96.12 37.665 ;
     RECT  2.16 37.935 96.12 38.205 ;
     RECT  2.16 38.475 96.12 38.745 ;
     RECT  2.16 39.015 96.12 39.285 ;
     RECT  2.16 39.555 96.12 39.825 ;
     RECT  2.16 40.095 96.12 40.365 ;
     RECT  2.16 40.635 96.12 40.905 ;
     RECT  2.16 41.175 41.148 41.445 ;
     RECT  77.22 41.175 96.12 41.445 ;
     RECT  2.16 41.715 41.148 41.985 ;
     RECT  77.22 41.715 96.12 41.985 ;
     RECT  2.16 42.255 41.148 42.525 ;
     RECT  77.22 42.255 96.12 42.525 ;
     RECT  2.16 42.795 41.148 43.065 ;
     RECT  77.22 42.795 96.12 43.065 ;
     RECT  2.16 43.335 41.148 43.605 ;
     RECT  77.22 43.335 96.12 43.605 ;
     RECT  2.16 43.875 41.148 44.145 ;
     RECT  77.22 43.875 96.12 44.145 ;
     RECT  2.16 44.415 41.148 44.685 ;
     RECT  77.22 44.415 96.12 44.685 ;
     RECT  2.16 44.955 41.148 45.225 ;
     RECT  77.22 44.955 96.12 45.225 ;
     RECT  2.16 45.495 41.148 45.765 ;
     RECT  77.22 45.495 96.12 45.765 ;
     RECT  2.16 46.035 41.148 46.305 ;
     RECT  77.22 46.035 96.12 46.305 ;
     RECT  2.16 46.575 41.148 46.845 ;
     RECT  77.22 46.575 96.12 46.845 ;
     RECT  2.16 47.115 41.148 47.385 ;
     RECT  77.22 47.115 96.12 47.385 ;
     RECT  2.16 47.655 41.148 47.925 ;
     RECT  77.22 47.655 96.12 47.925 ;
     RECT  2.16 48.195 41.148 48.465 ;
     RECT  77.22 48.195 96.12 48.465 ;
     RECT  2.16 48.735 41.148 49.005 ;
     RECT  77.22 48.735 96.12 49.005 ;
     RECT  2.16 49.275 41.148 49.545 ;
     RECT  77.22 49.275 96.12 49.545 ;
     RECT  2.16 49.815 41.148 50.085 ;
     RECT  77.22 49.815 96.12 50.085 ;
     RECT  2.16 50.355 41.148 50.625 ;
     RECT  77.22 50.355 96.12 50.625 ;
     RECT  2.16 50.895 41.148 51.165 ;
     RECT  77.22 50.895 96.12 51.165 ;
     RECT  2.16 51.435 41.148 51.705 ;
     RECT  77.22 51.435 96.12 51.705 ;
     RECT  2.16 51.975 41.148 52.245 ;
     RECT  77.22 51.975 96.12 52.245 ;
     RECT  2.16 52.515 41.148 52.785 ;
     RECT  77.22 52.515 96.12 52.785 ;
     RECT  2.16 53.055 41.148 53.325 ;
     RECT  77.22 53.055 96.12 53.325 ;
     RECT  2.16 53.595 41.148 53.865 ;
     RECT  77.22 53.595 96.12 53.865 ;
     RECT  2.16 54.135 41.148 54.405 ;
     RECT  77.22 54.135 96.12 54.405 ;
     RECT  2.16 54.675 41.148 54.945 ;
     RECT  77.22 54.675 96.12 54.945 ;
     RECT  2.16 55.215 41.148 55.485 ;
     RECT  77.22 55.215 96.12 55.485 ;
     RECT  2.16 55.755 41.148 56.025 ;
     RECT  77.22 55.755 96.12 56.025 ;
     RECT  2.16 56.295 41.148 56.565 ;
     RECT  77.22 56.295 96.12 56.565 ;
     RECT  2.16 56.835 41.148 57.105 ;
     RECT  77.22 56.835 96.12 57.105 ;
     RECT  2.16 57.375 41.148 57.645 ;
     RECT  77.22 57.375 96.12 57.645 ;
     RECT  2.16 57.915 41.148 58.185 ;
     RECT  77.22 57.915 96.12 58.185 ;
     RECT  2.16 58.455 41.148 58.725 ;
     RECT  77.22 58.455 96.12 58.725 ;
     RECT  2.16 58.995 41.148 59.265 ;
     RECT  77.22 58.995 96.12 59.265 ;
     RECT  2.16 59.535 41.148 59.805 ;
     RECT  77.22 59.535 96.12 59.805 ;
     RECT  2.16 60.075 41.148 60.345 ;
     RECT  77.22 60.075 96.12 60.345 ;
     RECT  2.16 60.615 41.148 60.885 ;
     RECT  77.22 60.615 96.12 60.885 ;
     RECT  2.16 61.155 41.148 61.425 ;
     RECT  77.22 61.155 96.12 61.425 ;
     RECT  2.16 61.695 41.148 61.965 ;
     RECT  77.22 61.695 96.12 61.965 ;
     RECT  2.16 62.235 41.148 62.505 ;
     RECT  77.22 62.235 96.12 62.505 ;
     RECT  2.16 62.775 96.12 63.045 ;
     RECT  2.16 63.315 96.12 63.585 ;
     RECT  2.16 63.855 96.12 64.125 ;
     RECT  2.16 64.395 96.12 64.665 ;
     RECT  2.16 64.935 96.12 65.205 ;
     RECT  2.16 65.475 96.12 65.745 ;
     RECT  2.16 66.015 96.12 66.285 ;
     RECT  2.16 66.555 96.12 66.825 ;
     RECT  2.16 67.095 96.12 67.365 ;
     RECT  2.16 67.635 96.12 67.905 ;
     RECT  2.16 68.175 96.12 68.445 ;
     RECT  2.16 68.715 96.12 68.985 ;
     RECT  2.16 69.255 96.12 69.525 ;
     RECT  2.16 69.795 96.12 70.065 ;
     RECT  2.16 70.335 96.12 70.605 ;
     RECT  2.16 70.875 96.12 71.145 ;
     RECT  2.16 71.415 96.12 71.685 ;
     RECT  2.16 71.955 96.12 72.225 ;
     RECT  2.16 72.495 96.12 72.765 ;
     RECT  2.16 73.035 96.12 73.305 ;
     RECT  2.16 73.575 96.12 73.845 ;
     RECT  2.16 74.115 96.12 74.385 ;
     RECT  2.16 74.655 96.12 74.925 ;
     RECT  2.16 75.195 96.12 75.465 ;
     RECT  2.16 75.735 96.12 76.005 ;
     RECT  2.16 76.275 96.12 76.545 ;
     RECT  2.16 76.815 96.12 77.085 ;
     RECT  2.16 77.355 96.12 77.625 ;
     RECT  2.16 77.895 96.12 78.165 ;
     RECT  2.16 78.435 96.12 78.705 ;
     RECT  2.16 78.975 96.12 79.245 ;
     RECT  2.16 79.515 96.12 79.785 ;
     RECT  2.16 80.055 96.12 80.325 ;
     RECT  2.16 80.595 96.12 80.865 ;
     RECT  2.16 81.135 96.12 81.405 ;
     RECT  2.16 81.675 96.12 81.945 ;
     RECT  2.16 82.215 96.12 82.485 ;
     RECT  2.16 82.755 96.12 83.025 ;
     RECT  2.16 83.295 96.12 83.565 ;
     RECT  2.16 83.835 96.12 84.105 ;
     RECT  2.16 84.375 41.148 84.645 ;
     RECT  77.22 84.375 96.12 84.645 ;
     RECT  2.16 84.915 41.148 85.185 ;
     RECT  77.22 84.915 96.12 85.185 ;
     RECT  2.16 85.455 41.148 85.725 ;
     RECT  77.22 85.455 96.12 85.725 ;
     RECT  2.16 85.995 41.148 86.265 ;
     RECT  77.22 85.995 96.12 86.265 ;
     RECT  2.16 86.535 41.148 86.805 ;
     RECT  77.22 86.535 96.12 86.805 ;
     RECT  2.16 87.075 41.148 87.345 ;
     RECT  77.22 87.075 96.12 87.345 ;
     RECT  2.16 87.615 41.148 87.885 ;
     RECT  77.22 87.615 96.12 87.885 ;
     RECT  2.16 88.155 41.148 88.425 ;
     RECT  77.22 88.155 96.12 88.425 ;
     RECT  2.16 88.695 41.148 88.965 ;
     RECT  77.22 88.695 96.12 88.965 ;
     RECT  2.16 89.235 41.148 89.505 ;
     RECT  77.22 89.235 96.12 89.505 ;
     RECT  2.16 89.775 41.148 90.045 ;
     RECT  77.22 89.775 96.12 90.045 ;
     RECT  2.16 90.315 41.148 90.585 ;
     RECT  77.22 90.315 96.12 90.585 ;
     RECT  2.16 90.855 41.148 91.125 ;
     RECT  77.22 90.855 96.12 91.125 ;
     RECT  2.16 91.395 41.148 91.665 ;
     RECT  77.22 91.395 96.12 91.665 ;
     RECT  2.16 91.935 41.148 92.205 ;
     RECT  77.22 91.935 96.12 92.205 ;
     RECT  2.16 92.475 41.148 92.745 ;
     RECT  77.22 92.475 96.12 92.745 ;
     RECT  2.16 93.015 41.148 93.285 ;
     RECT  77.22 93.015 96.12 93.285 ;
     RECT  2.16 93.555 41.148 93.825 ;
     RECT  77.22 93.555 96.12 93.825 ;
     RECT  2.16 94.095 41.148 94.365 ;
     RECT  77.22 94.095 96.12 94.365 ;
     RECT  2.16 94.635 41.148 94.905 ;
     RECT  77.22 94.635 96.12 94.905 ;
     RECT  2.16 95.175 41.148 95.445 ;
     RECT  77.22 95.175 96.12 95.445 ;
     RECT  2.16 95.715 41.148 95.985 ;
     RECT  77.22 95.715 96.12 95.985 ;
     RECT  2.16 96.255 41.148 96.525 ;
     RECT  77.22 96.255 96.12 96.525 ;
     RECT  2.16 96.795 41.148 97.065 ;
     RECT  77.22 96.795 96.12 97.065 ;
     RECT  2.16 97.335 41.148 97.605 ;
     RECT  77.22 97.335 96.12 97.605 ;
     RECT  2.16 97.875 41.148 98.145 ;
     RECT  77.22 97.875 96.12 98.145 ;
     RECT  2.16 98.415 41.148 98.685 ;
     RECT  77.22 98.415 96.12 98.685 ;
     RECT  2.16 98.955 41.148 99.225 ;
     RECT  77.22 98.955 96.12 99.225 ;
     RECT  2.16 99.495 41.148 99.765 ;
     RECT  77.22 99.495 96.12 99.765 ;
     RECT  2.16 100.035 41.148 100.305 ;
     RECT  77.22 100.035 96.12 100.305 ;
     RECT  2.16 100.575 41.148 100.845 ;
     RECT  77.22 100.575 96.12 100.845 ;
     RECT  2.16 101.115 41.148 101.385 ;
     RECT  77.22 101.115 96.12 101.385 ;
     RECT  2.16 101.655 41.148 101.925 ;
     RECT  77.22 101.655 96.12 101.925 ;
     RECT  2.16 102.195 41.148 102.465 ;
     RECT  77.22 102.195 96.12 102.465 ;
     RECT  2.16 102.735 41.148 103.005 ;
     RECT  77.22 102.735 96.12 103.005 ;
     RECT  2.16 103.275 41.148 103.545 ;
     RECT  77.22 103.275 96.12 103.545 ;
     RECT  2.16 103.815 41.148 104.085 ;
     RECT  77.22 103.815 96.12 104.085 ;
     RECT  2.16 104.355 41.148 104.625 ;
     RECT  77.22 104.355 96.12 104.625 ;
     RECT  2.16 104.895 41.148 105.165 ;
     RECT  77.22 104.895 96.12 105.165 ;
     RECT  2.16 105.435 41.148 105.705 ;
     RECT  77.22 105.435 96.12 105.705 ;
     RECT  2.16 105.975 96.12 106.245 ;
     RECT  2.16 106.515 96.12 106.785 ;
     RECT  2.16 107.055 96.12 107.325 ;
     RECT  2.16 107.595 96.12 107.865 ;
     RECT  2.16 108.135 96.12 108.405 ;
     RECT  2.16 108.675 96.12 108.945 ;
     RECT  2.16 109.215 96.12 109.485 ;
     RECT  2.16 109.755 96.12 110.025 ;
     RECT  2.16 110.295 96.12 110.565 ;
     RECT  2.16 110.835 96.12 111.105 ;
     RECT  2.16 111.375 96.12 111.645 ;
     RECT  2.16 111.915 96.12 112.185 ;
     RECT  2.16 112.455 96.12 112.725 ;
     RECT  2.16 112.995 96.12 113.265 ;
     RECT  2.16 113.535 96.12 113.805 ;
     RECT  2.16 114.075 96.12 114.345 ;
     RECT  2.16 114.615 96.12 114.885 ;
     RECT  2.16 115.155 96.12 115.425 ;
     RECT  2.16 115.695 96.12 115.965 ;
     RECT  2.16 116.235 96.12 116.505 ;
     RECT  2.16 116.775 96.12 117.045 ;
     RECT  2.16 117.315 96.12 117.585 ;
     RECT  2.16 117.855 96.12 118.125 ;
     RECT  2.16 118.395 96.12 118.665 ;
     RECT  2.16 118.935 96.12 119.205 ;
     RECT  2.16 119.475 96.12 119.745 ;
     RECT  2.16 120.015 96.12 120.285 ;
     RECT  2.16 120.555 96.12 120.825 ;
     RECT  2.16 121.095 96.12 121.365 ;
     RECT  2.16 121.635 96.12 121.905 ;
     RECT  2.16 122.175 96.12 122.445 ;
     RECT  2.16 122.715 96.12 122.985 ;
     RECT  2.16 123.255 96.12 123.525 ;
     RECT  2.16 123.795 96.12 124.065 ;
     RECT  2.16 124.335 96.12 124.605 ;
     RECT  2.16 124.875 96.12 125.145 ;
     RECT  2.16 125.415 96.12 125.685 ;
     RECT  2.16 125.955 96.12 126.225 ;
     RECT  2.16 126.495 96.12 126.765 ;
     RECT  2.16 127.035 96.12 127.305 ;
     RECT  2.16 127.575 41.148 127.845 ;
     RECT  77.22 127.575 96.12 127.845 ;
     RECT  2.16 128.115 41.148 128.385 ;
     RECT  77.22 128.115 96.12 128.385 ;
     RECT  2.16 128.655 41.148 128.925 ;
     RECT  77.22 128.655 96.12 128.925 ;
     RECT  2.16 129.195 41.148 129.465 ;
     RECT  77.22 129.195 96.12 129.465 ;
     RECT  2.16 129.735 41.148 130.005 ;
     RECT  77.22 129.735 96.12 130.005 ;
     RECT  2.16 130.275 41.148 130.545 ;
     RECT  77.22 130.275 96.12 130.545 ;
     RECT  2.16 130.815 41.148 131.085 ;
     RECT  77.22 130.815 96.12 131.085 ;
     RECT  2.16 131.355 41.148 131.625 ;
     RECT  77.22 131.355 96.12 131.625 ;
     RECT  2.16 131.895 41.148 132.165 ;
     RECT  77.22 131.895 96.12 132.165 ;
     RECT  2.16 132.435 41.148 132.705 ;
     RECT  77.22 132.435 96.12 132.705 ;
     RECT  2.16 132.975 41.148 133.245 ;
     RECT  77.22 132.975 96.12 133.245 ;
     RECT  2.16 133.515 41.148 133.785 ;
     RECT  77.22 133.515 96.12 133.785 ;
     RECT  2.16 134.055 41.148 134.325 ;
     RECT  77.22 134.055 96.12 134.325 ;
     RECT  2.16 134.595 41.148 134.865 ;
     RECT  77.22 134.595 96.12 134.865 ;
     RECT  2.16 135.135 41.148 135.405 ;
     RECT  77.22 135.135 96.12 135.405 ;
     RECT  2.16 135.675 41.148 135.945 ;
     RECT  77.22 135.675 96.12 135.945 ;
     RECT  2.16 136.215 41.148 136.485 ;
     RECT  77.22 136.215 96.12 136.485 ;
     RECT  2.16 136.755 41.148 137.025 ;
     RECT  77.22 136.755 96.12 137.025 ;
     RECT  2.16 137.295 41.148 137.565 ;
     RECT  77.22 137.295 96.12 137.565 ;
     RECT  2.16 137.835 41.148 138.105 ;
     RECT  77.22 137.835 96.12 138.105 ;
     RECT  2.16 138.375 41.148 138.645 ;
     RECT  77.22 138.375 96.12 138.645 ;
     RECT  2.16 138.915 41.148 139.185 ;
     RECT  77.22 138.915 96.12 139.185 ;
     RECT  2.16 139.455 41.148 139.725 ;
     RECT  77.22 139.455 96.12 139.725 ;
     RECT  2.16 139.995 41.148 140.265 ;
     RECT  77.22 139.995 96.12 140.265 ;
     RECT  2.16 140.535 41.148 140.805 ;
     RECT  77.22 140.535 96.12 140.805 ;
     RECT  2.16 141.075 41.148 141.345 ;
     RECT  77.22 141.075 96.12 141.345 ;
     RECT  2.16 141.615 41.148 141.885 ;
     RECT  77.22 141.615 96.12 141.885 ;
     RECT  2.16 142.155 41.148 142.425 ;
     RECT  77.22 142.155 96.12 142.425 ;
     RECT  2.16 142.695 41.148 142.965 ;
     RECT  77.22 142.695 96.12 142.965 ;
     RECT  2.16 143.235 41.148 143.505 ;
     RECT  77.22 143.235 96.12 143.505 ;
     RECT  2.16 143.775 41.148 144.045 ;
     RECT  77.22 143.775 96.12 144.045 ;
     RECT  2.16 144.315 41.148 144.585 ;
     RECT  77.22 144.315 96.12 144.585 ;
     RECT  2.16 144.855 41.148 145.125 ;
     RECT  77.22 144.855 96.12 145.125 ;
     RECT  2.16 145.395 41.148 145.665 ;
     RECT  77.22 145.395 96.12 145.665 ;
     RECT  2.16 145.935 41.148 146.205 ;
     RECT  77.22 145.935 96.12 146.205 ;
     RECT  2.16 146.475 41.148 146.745 ;
     RECT  77.22 146.475 96.12 146.745 ;
     RECT  2.16 147.015 41.148 147.285 ;
     RECT  77.22 147.015 96.12 147.285 ;
     RECT  2.16 147.555 41.148 147.825 ;
     RECT  77.22 147.555 96.12 147.825 ;
     RECT  2.16 148.095 41.148 148.365 ;
     RECT  77.22 148.095 96.12 148.365 ;
     RECT  2.16 148.635 41.148 148.905 ;
     RECT  77.22 148.635 96.12 148.905 ;
     RECT  2.16 149.175 96.12 149.445 ;
     RECT  2.16 149.715 96.12 149.985 ;
     RECT  2.16 150.255 96.12 150.525 ;
     RECT  2.16 150.795 96.12 151.065 ;
     RECT  2.16 151.335 96.12 151.605 ;
     RECT  2.16 151.875 96.12 152.145 ;
     RECT  2.16 152.415 96.12 152.685 ;
     RECT  2.16 152.955 96.12 153.225 ;
     RECT  2.16 153.495 96.12 153.765 ;
     RECT  2.16 154.035 96.12 154.305 ;
     RECT  2.16 154.575 96.12 154.845 ;
     RECT  2.16 155.115 96.12 155.385 ;
     RECT  2.16 155.655 96.12 155.925 ;
     RECT  2.16 156.195 96.12 156.465 ;
     RECT  2.16 156.735 96.12 157.005 ;
     RECT  2.16 157.275 96.12 157.545 ;
     RECT  2.16 157.815 96.12 158.085 ;
     RECT  2.16 158.355 96.12 158.625 ;
     RECT  2.16 158.895 96.12 159.165 ;
     RECT  2.16 159.435 96.12 159.705 ;
     RECT  2.16 159.975 96.12 160.245 ;
     RECT  2.16 160.515 96.12 160.785 ;
     RECT  2.16 161.055 96.12 161.325 ;
     RECT  2.16 161.595 96.12 161.865 ;
     RECT  2.16 162.135 96.12 162.405 ;
     RECT  2.16 162.675 96.12 162.945 ;
     RECT  2.16 163.215 96.12 163.485 ;
     RECT  2.16 163.755 96.12 164.025 ;
     RECT  2.16 164.295 96.12 164.565 ;
     RECT  2.16 164.835 96.12 165.105 ;
     RECT  2.16 165.375 96.12 165.645 ;
     RECT  2.16 165.915 96.12 166.185 ;
     RECT  2.16 166.455 96.12 166.725 ;
     RECT  2.16 166.995 96.12 167.265 ;
     RECT  2.16 167.535 96.12 167.805 ;
     RECT  2.16 168.075 96.12 168.345 ;
    LAYER M1 ;
     RECT  2.16 2.151 96.12 41.049 ;
     RECT  43.2 43.2 75.192 60.504 ;
     RECT  2.16 41.049 41.148 62.631 ;
     RECT  77.22 41.049 96.12 62.631 ;
     RECT  2.16 62.631 96.12 84.249 ;
     RECT  43.2 86.4 75.192 103.704 ;
     RECT  2.16 84.249 41.148 105.831 ;
     RECT  77.22 84.249 96.12 105.831 ;
     RECT  2.16 105.831 96.12 127.449 ;
     RECT  43.2 129.6 75.192 146.904 ;
     RECT  2.16 127.449 41.148 149.031 ;
     RECT  77.22 127.449 96.12 149.031 ;
     RECT  2.16 149.031 96.12 168.489 ;
    LAYER M2 ;
     RECT  0.103 79.056 0.139 79.074 ;
     RECT  0.103 84.888 0.139 85.446 ;
     RECT  0.103 122.796 0.211 122.814 ;
     RECT  0.139 84.888 0.239 85.824 ;
     RECT  0.103 42.336 0.535 43.326 ;
     RECT  0.103 44.388 0.535 44.406 ;
     RECT  0.103 45.306 0.535 45.324 ;
     RECT  0.103 31.806 2.16 33.984 ;
     RECT  0.535 35.046 2.16 35.064 ;
     RECT  0.103 35.856 2.16 35.874 ;
     RECT  0.103 40.986 2.16 41.364 ;
     RECT  0.535 42.336 2.16 45.324 ;
     RECT  0.139 78.984 2.16 79.074 ;
     RECT  0.103 80.838 2.16 81.504 ;
     RECT  0.103 82.566 2.16 82.584 ;
     RECT  0.239 84.888 2.16 85.446 ;
     RECT  0.103 87.156 2.16 87.714 ;
     RECT  0.103 88.776 2.16 88.794 ;
     RECT  0.211 122.796 2.16 123.354 ;
     RECT  0.103 124.146 2.16 124.164 ;
     RECT  0.103 125.226 2.16 126.324 ;
     RECT  0.103 131.976 2.16 131.994 ;
     RECT  37.831 170.586 37.903 170.604 ;
     RECT  37.903 170.514 38.219 170.604 ;
     RECT  2.16 2.151 41.148 168.489 ;
     RECT  41.148 45.198 41.279 46.296 ;
     RECT  41.148 62.631 41.315 90.036 ;
     RECT  41.315 85.698 41.351 90.036 ;
     RECT  41.148 97.506 41.351 101.214 ;
     RECT  41.351 85.698 41.387 86.49 ;
     RECT  41.148 94.446 41.387 96.318 ;
     RECT  41.148 2.151 41.423 44.136 ;
     RECT  41.351 97.506 41.423 100.224 ;
     RECT  41.351 101.016 41.423 101.214 ;
     RECT  41.423 97.506 41.459 99.756 ;
     RECT  41.351 87.354 41.531 90.036 ;
     RECT  41.387 94.446 41.531 96.174 ;
     RECT  41.148 142.056 41.531 143.874 ;
     RECT  41.423 2.151 41.567 41.742 ;
     RECT  41.531 94.446 41.567 95.904 ;
     RECT  41.531 142.056 41.567 142.488 ;
     RECT  41.148 50.904 41.603 54.054 ;
     RECT  41.531 143.406 41.603 143.874 ;
     RECT  41.603 50.904 41.639 53.964 ;
     RECT  41.567 94.446 41.639 95.706 ;
     RECT  41.423 42.651 41.819 44.136 ;
     RECT  41.387 85.77 41.819 86.49 ;
     RECT  41.819 42.651 41.891 43.866 ;
     RECT  41.148 102.096 41.891 102.114 ;
     RECT  41.603 143.586 41.891 143.694 ;
     RECT  41.148 60.426 41.899 61.614 ;
     RECT  41.148 54.846 41.927 56.394 ;
     RECT  41.315 62.631 41.927 84.942 ;
     RECT  41.148 130.518 41.963 132.696 ;
     RECT  41.148 58.896 41.999 59.094 ;
     RECT  41.899 60.426 41.999 61.65 ;
     RECT  41.531 87.354 41.999 89.496 ;
     RECT  41.819 86.04 42.079 86.49 ;
     RECT  41.999 87.354 42.079 88.92 ;
     RECT  41.639 50.904 42.179 50.994 ;
     RECT  41.639 51.786 42.179 53.964 ;
     RECT  41.927 54.846 42.179 56.214 ;
     RECT  41.999 59.076 42.179 59.094 ;
     RECT  42.079 86.04 42.179 88.92 ;
     RECT  41.148 136.026 42.179 140.994 ;
     RECT  41.639 94.536 42.215 95.706 ;
     RECT  41.963 130.518 42.223 130.536 ;
     RECT  41.148 133.56 42.287 133.578 ;
     RECT  41.148 105.831 42.295 127.494 ;
     RECT  42.223 130.482 42.295 130.536 ;
     RECT  41.963 131.292 42.323 132.696 ;
     RECT  42.323 131.292 42.359 131.958 ;
     RECT  42.295 105.831 42.403 127.566 ;
     RECT  42.179 52.794 42.467 53.964 ;
     RECT  42.215 95.076 42.467 95.706 ;
     RECT  41.459 97.506 42.475 98.874 ;
     RECT  41.459 99.666 42.475 99.756 ;
     RECT  41.891 42.651 42.503 43.164 ;
     RECT  42.403 105.831 42.619 127.674 ;
     RECT  41.567 142.056 42.655 142.344 ;
     RECT  42.503 42.732 42.683 43.164 ;
     RECT  41.148 103.752 42.691 104.616 ;
     RECT  42.619 105.444 42.691 127.674 ;
     RECT  41.148 147.06 42.691 148.284 ;
     RECT  41.148 149.031 42.691 168.489 ;
     RECT  41.927 62.631 42.727 84.249 ;
     RECT  42.691 103.752 42.899 127.674 ;
     RECT  41.279 45.27 42.979 46.296 ;
     RECT  42.179 55.116 43.051 56.214 ;
     RECT  42.683 43.11 43.2 43.164 ;
     RECT  42.979 45.27 43.2 46.764 ;
     RECT  41.148 50.058 43.2 50.148 ;
     RECT  42.179 51.786 43.2 51.804 ;
     RECT  42.467 52.956 43.2 53.964 ;
     RECT  43.051 54.72 43.2 56.214 ;
     RECT  41.999 60.552 43.2 61.65 ;
     RECT  42.179 86.04 43.2 86.058 ;
     RECT  42.179 87.786 43.2 88.686 ;
     RECT  41.148 92.286 43.2 93.474 ;
     RECT  42.467 95.076 43.2 95.634 ;
     RECT  42.475 97.506 43.2 99.756 ;
     RECT  41.423 101.016 43.2 101.034 ;
     RECT  42.899 103.752 43.2 127.494 ;
     RECT  41.148 129.24 43.2 129.294 ;
     RECT  42.295 130.401 43.2 130.536 ;
     RECT  42.359 131.292 43.2 131.652 ;
     RECT  42.179 136.026 43.2 138.024 ;
     RECT  42.179 139.086 43.2 140.994 ;
     RECT  42.655 142.056 43.2 142.488 ;
     RECT  41.891 143.586 43.2 143.604 ;
     RECT  42.691 147.06 43.2 168.489 ;
     RECT  43.2 86.04 43.367 127.494 ;
     RECT  42.727 62.514 50.351 84.249 ;
     RECT  50.351 62.586 74.659 84.249 ;
     RECT  43.2 43.11 75.192 61.65 ;
     RECT  43.367 86.04 75.192 127.449 ;
     RECT  43.2 129.24 75.192 168.489 ;
     RECT  74.659 62.478 75.263 84.249 ;
     RECT  75.263 62.55 75.271 84.249 ;
     RECT  75.192 129.24 75.271 130.77 ;
     RECT  75.192 52.29 75.335 54.738 ;
     RECT  75.271 62.55 75.335 84.942 ;
     RECT  75.192 96.876 75.335 98.064 ;
     RECT  75.192 134.136 75.335 136.71 ;
     RECT  75.192 142.506 75.335 142.524 ;
     RECT  75.192 58.698 75.371 58.986 ;
     RECT  75.335 62.631 75.371 84.942 ;
     RECT  75.192 146.448 75.371 168.489 ;
     RECT  75.192 43.11 75.487 43.29 ;
     RECT  75.271 129.204 75.631 130.77 ;
     RECT  75.192 86.04 75.703 86.364 ;
     RECT  75.192 60.516 75.767 61.65 ;
     RECT  75.192 131.706 75.803 131.724 ;
     RECT  75.703 85.932 75.991 86.364 ;
     RECT  75.335 97.074 76.063 98.064 ;
     RECT  76.063 97.074 76.099 98.37 ;
     RECT  76.063 55.494 76.135 55.512 ;
     RECT  75.192 101.286 76.135 101.304 ;
     RECT  76.099 97.074 76.171 98.91 ;
     RECT  76.063 142.776 76.171 142.794 ;
     RECT  75.631 128.466 76.243 130.77 ;
     RECT  75.487 42.696 76.315 43.29 ;
     RECT  76.099 44.352 76.315 44.37 ;
     RECT  75.192 50.13 76.351 50.148 ;
     RECT  76.315 91.476 76.351 91.494 ;
     RECT  75.192 94.032 76.351 94.626 ;
     RECT  75.192 133.146 76.351 133.164 ;
     RECT  75.192 48.672 76.387 49.374 ;
     RECT  76.351 50.13 76.387 50.688 ;
     RECT  75.335 52.29 76.387 54.63 ;
     RECT  76.351 91.476 76.387 91.728 ;
     RECT  76.351 93.798 76.387 94.626 ;
     RECT  76.243 128.322 76.387 130.77 ;
     RECT  75.335 135.072 76.387 136.71 ;
     RECT  76.423 88.056 76.459 88.074 ;
     RECT  75.991 85.932 76.531 86.49 ;
     RECT  75.371 58.968 76.639 58.986 ;
     RECT  76.063 144.594 76.639 144.612 ;
     RECT  76.135 55.494 76.675 55.944 ;
     RECT  76.387 48.672 76.927 54.63 ;
     RECT  76.531 85.662 76.927 86.49 ;
     RECT  76.387 91.476 76.927 92.268 ;
     RECT  76.387 93.096 76.927 96.21 ;
     RECT  76.927 85.662 76.963 86.904 ;
     RECT  76.171 97.074 76.963 98.946 ;
     RECT  76.927 131.706 76.963 131.724 ;
     RECT  76.351 132.714 76.963 133.164 ;
     RECT  75.335 134.136 76.963 134.154 ;
     RECT  76.387 128.322 76.999 130.914 ;
     RECT  76.963 131.706 76.999 133.164 ;
     RECT  76.927 91.476 77.215 96.21 ;
     RECT  76.963 96.966 77.215 98.946 ;
     RECT  76.387 135.072 77.215 138.87 ;
     RECT  41.567 2.151 77.22 41.049 ;
     RECT  76.315 42.696 77.22 44.37 ;
     RECT  75.192 46.656 77.22 46.674 ;
     RECT  76.927 48.366 77.22 54.63 ;
     RECT  76.675 55.494 77.22 56.484 ;
     RECT  76.639 58.626 77.22 58.986 ;
     RECT  75.767 60.552 77.22 61.65 ;
     RECT  75.371 62.631 77.22 84.249 ;
     RECT  76.963 85.662 77.22 87.03 ;
     RECT  76.459 87.786 77.22 88.074 ;
     RECT  76.423 90.126 77.22 90.144 ;
     RECT  77.215 91.476 77.22 98.946 ;
     RECT  76.135 101.286 77.22 101.754 ;
     RECT  75.192 103.752 77.22 127.449 ;
     RECT  76.999 128.322 77.22 133.164 ;
     RECT  76.963 133.956 77.22 134.154 ;
     RECT  77.215 135.072 77.22 139.176 ;
     RECT  75.192 139.932 77.22 141.174 ;
     RECT  76.171 142.056 77.22 142.794 ;
     RECT  76.639 144.486 77.22 144.612 ;
     RECT  75.371 147.06 77.22 168.489 ;
     RECT  77.22 2.151 96.12 168.489 ;
     RECT  96.12 38.988 96.323 43.704 ;
     RECT  96.12 52.758 96.323 55.206 ;
     RECT  96.12 81.378 96.323 84.906 ;
     RECT  96.12 96.498 96.323 101.106 ;
     RECT  96.12 125.658 96.323 127.062 ;
     RECT  96.12 138.384 96.323 143.532 ;
     RECT  96.323 43.308 96.359 43.704 ;
     RECT  96.323 96.606 96.359 100.134 ;
     RECT  96.323 138.384 96.359 142.524 ;
     RECT  96.323 38.988 96.935 42.552 ;
     RECT  96.359 43.308 96.935 43.632 ;
     RECT  96.323 52.758 96.935 55.008 ;
     RECT  96.359 96.606 96.935 100.062 ;
     RECT  96.323 125.856 96.935 127.062 ;
     RECT  96.359 138.384 96.935 138.942 ;
     RECT  96.359 140.166 96.935 142.524 ;
     RECT  96.323 143.316 96.935 143.532 ;
     RECT  96.935 54.108 96.971 55.008 ;
     RECT  96.12 85.734 96.971 86.256 ;
     RECT  96.12 56.106 97.475 57.474 ;
     RECT  96.935 39.096 97.511 39.384 ;
     RECT  96.935 40.176 97.511 42.552 ;
     RECT  96.935 43.614 97.511 43.632 ;
     RECT  96.935 52.758 97.511 52.884 ;
     RECT  96.971 54.216 97.511 55.008 ;
     RECT  97.475 56.106 97.511 57.132 ;
     RECT  96.323 81.684 97.511 84.906 ;
     RECT  96.971 85.734 97.511 85.752 ;
     RECT  96.935 98.496 97.511 100.062 ;
     RECT  96.935 125.856 97.511 126.486 ;
     RECT  96.935 138.384 97.511 138.402 ;
     RECT  96.935 140.166 97.511 140.184 ;
     RECT  96.935 141.282 97.511 142.524 ;
     RECT  96.935 143.514 97.511 143.532 ;
     RECT  97.511 40.644 97.547 40.662 ;
     RECT  97.511 42.534 97.547 42.552 ;
     RECT  97.511 56.304 97.547 56.322 ;
     RECT  97.511 82.962 97.547 83.394 ;
     RECT  97.511 84.186 97.547 84.744 ;
     RECT  96.935 97.686 97.547 97.704 ;
     RECT  96.323 101.088 97.547 101.106 ;
     RECT  97.511 39.294 97.583 39.312 ;
     RECT  97.511 81.918 97.583 81.936 ;
     RECT  97.547 84.186 97.583 84.204 ;
     RECT  96.935 96.606 97.583 96.894 ;
     RECT  97.583 96.606 98.267 96.624 ;
     RECT  98.167 139.5 98.267 139.518 ;
    LAYER M3 ;
     RECT  2.415 2.143 2.505 2.413 ;
     RECT  5.115 2.143 5.205 2.413 ;
     RECT  7.815 2.143 7.905 2.413 ;
     RECT  10.515 2.143 10.605 2.413 ;
     RECT  13.215 2.143 13.305 2.413 ;
     RECT  15.915 2.143 16.005 2.413 ;
     RECT  18.615 2.143 18.705 2.413 ;
     RECT  21.315 2.143 21.405 2.413 ;
     RECT  24.015 2.143 24.105 2.413 ;
     RECT  26.715 2.143 26.805 2.413 ;
     RECT  29.415 2.143 29.505 2.413 ;
     RECT  32.115 2.143 32.205 2.413 ;
     RECT  34.815 2.143 34.905 2.413 ;
     RECT  37.515 2.143 37.605 2.413 ;
     RECT  40.215 2.143 40.305 2.413 ;
     RECT  42.915 2.143 43.005 2.413 ;
     RECT  45.615 2.143 45.705 2.413 ;
     RECT  48.315 2.143 48.405 2.413 ;
     RECT  51.015 2.143 51.105 2.413 ;
     RECT  53.715 2.143 53.805 2.413 ;
     RECT  56.415 2.143 56.505 2.413 ;
     RECT  59.115 2.143 59.205 2.413 ;
     RECT  61.815 2.143 61.905 2.413 ;
     RECT  64.515 2.143 64.605 2.413 ;
     RECT  67.215 2.143 67.305 2.413 ;
     RECT  69.915 2.143 70.005 2.413 ;
     RECT  72.615 2.143 72.705 2.413 ;
     RECT  75.315 2.143 75.405 2.413 ;
     RECT  78.015 2.143 78.105 2.413 ;
     RECT  80.715 2.143 80.805 2.413 ;
     RECT  83.415 2.143 83.505 2.413 ;
     RECT  86.115 2.143 86.205 2.413 ;
     RECT  88.815 2.143 88.905 2.413 ;
     RECT  91.515 2.143 91.605 2.413 ;
     RECT  94.215 2.143 94.305 2.413 ;
     RECT  2.415 2.413 2.697 31.693 ;
     RECT  2.415 31.693 3.078 31.723 ;
     RECT  4.212 31.693 4.23 31.729 ;
     RECT  5.115 2.413 5.397 31.729 ;
     RECT  2.304 31.723 3.294 31.891 ;
     RECT  4.212 31.729 6.066 31.919 ;
     RECT  4.5 31.919 6.066 32.189 ;
     RECT  7.815 2.413 8.097 32.197 ;
     RECT  42.915 2.413 43.197 32.269 ;
     RECT  42.372 32.269 43.197 32.305 ;
     RECT  2.304 31.891 3.474 32.341 ;
     RECT  7.272 32.197 8.097 32.341 ;
     RECT  2.304 32.341 3.618 32.459 ;
     RECT  7.272 32.341 8.658 32.467 ;
     RECT  6.84 32.467 8.658 32.611 ;
     RECT  0.108 31.675 0.126 32.683 ;
     RECT  0.108 32.683 0.162 32.813 ;
     RECT  2.415 32.459 3.618 32.881 ;
     RECT  4.5 32.189 5.994 32.881 ;
     RECT  6.804 32.611 8.658 32.881 ;
     RECT  2.415 32.881 5.994 32.971 ;
     RECT  6.768 32.881 8.874 32.971 ;
     RECT  2.415 32.971 8.874 32.999 ;
     RECT  42.048 32.305 43.197 33.043 ;
     RECT  2.415 32.999 8.766 33.269 ;
     RECT  38.772 33.349 38.79 33.449 ;
     RECT  41.616 33.043 43.197 33.547 ;
     RECT  0.108 32.813 0.126 33.979 ;
     RECT  0.108 33.979 0.162 33.989 ;
     RECT  2.415 33.269 8.658 34.123 ;
     RECT  2.304 34.123 8.658 34.501 ;
     RECT  2.304 34.501 9.234 34.529 ;
     RECT  0.144 33.989 0.162 34.685 ;
     RECT  0.18 34.843 0.198 34.973 ;
     RECT  38.808 34.771 38.826 35.032 ;
     RECT  0.54 35.041 0.558 35.165 ;
     RECT  40.215 2.413 40.497 35.203 ;
     RECT  41.58 33.547 43.197 35.203 ;
     RECT  2.415 34.529 9.234 35.239 ;
     RECT  38.808 35.032 38.862 35.303 ;
     RECT  2.415 35.239 9.306 35.501 ;
     RECT  10.515 2.413 10.797 35.509 ;
     RECT  2.415 35.501 8.658 35.563 ;
     RECT  38.808 35.303 38.826 35.573 ;
     RECT  10.515 35.509 10.854 35.609 ;
     RECT  2.304 35.563 8.658 35.645 ;
     RECT  6.264 35.645 8.658 35.843 ;
     RECT  0.108 35.707 0.126 35.879 ;
     RECT  2.304 35.645 5.397 36.269 ;
     RECT  40.215 35.203 43.197 36.383 ;
     RECT  6.732 35.843 8.658 36.509 ;
     RECT  2.415 36.269 5.397 36.625 ;
     RECT  6.84 36.509 8.658 36.689 ;
     RECT  2.415 36.625 5.886 36.701 ;
     RECT  38.772 36.751 38.79 36.887 ;
     RECT  2.415 36.701 5.397 36.959 ;
     RECT  6.984 36.689 8.658 37.229 ;
     RECT  40.215 36.383 40.497 37.327 ;
     RECT  41.58 36.383 43.197 37.327 ;
     RECT  5.04 36.959 5.397 38.039 ;
     RECT  5.115 38.039 5.397 38.101 ;
     RECT  5.115 38.101 6.174 38.141 ;
     RECT  2.415 36.959 4.05 38.579 ;
     RECT  94.215 2.413 94.497 38.821 ;
     RECT  93.6 38.821 94.497 38.947 ;
     RECT  93.492 38.947 94.497 38.983 ;
     RECT  91.515 2.413 91.797 39.019 ;
     RECT  92.628 38.785 92.646 39.019 ;
     RECT  7.2 37.229 8.658 39.047 ;
     RECT  88.815 2.413 89.097 39.055 ;
     RECT  91.515 39.019 92.646 39.091 ;
     RECT  96.912 38.983 96.93 39.091 ;
     RECT  88.815 39.055 89.37 39.181 ;
     RECT  93.492 38.983 94.554 39.217 ;
     RECT  88.815 39.181 89.442 39.289 ;
     RECT  96.912 39.091 97.506 39.289 ;
     RECT  93.492 39.217 95.022 39.325 ;
     RECT  95.76 38.551 95.85 39.325 ;
     RECT  91.332 39.091 92.646 39.341 ;
     RECT  91.332 39.341 92.07 39.361 ;
     RECT  2.415 38.579 2.898 39.389 ;
     RECT  93.492 39.325 95.85 39.485 ;
     RECT  12.132 39.451 12.15 39.499 ;
     RECT  96.912 39.289 97.578 39.551 ;
     RECT  90.864 39.361 92.07 39.595 ;
     RECT  75.315 2.413 75.597 39.631 ;
     RECT  10.515 35.609 10.797 39.721 ;
     RECT  12.06 39.499 12.15 39.721 ;
     RECT  4.032 38.579 4.05 39.749 ;
     RECT  12.06 39.721 12.222 39.749 ;
     RECT  86.115 2.413 86.397 39.757 ;
     RECT  10.515 39.721 10.854 39.821 ;
     RECT  12.204 39.749 12.222 39.821 ;
     RECT  86.115 39.757 86.634 39.857 ;
     RECT  90.468 39.595 92.07 39.857 ;
     RECT  75.276 39.631 75.597 39.865 ;
     RECT  93.492 39.485 95.382 39.865 ;
     RECT  40.215 37.327 43.197 39.893 ;
     RECT  83.415 2.413 83.697 40.027 ;
     RECT  75.24 39.865 75.597 40.171 ;
     RECT  78.015 2.413 78.297 40.171 ;
     RECT  90.54 39.857 92.07 40.171 ;
     RECT  92.952 39.865 95.382 40.171 ;
     RECT  7.815 39.047 8.658 40.199 ;
     RECT  80.715 2.413 80.997 40.261 ;
     RECT  4.14 39.991 4.158 40.289 ;
     RECT  83.415 40.027 83.754 40.289 ;
     RECT  90.54 40.171 95.382 40.289 ;
     RECT  75.24 40.171 75.654 40.441 ;
     RECT  95.364 40.289 95.382 40.441 ;
     RECT  96.3 39.739 96.318 40.441 ;
     RECT  97.488 39.551 97.578 40.493 ;
     RECT  90.54 40.289 94.626 40.603 ;
     RECT  97.488 40.493 97.542 40.667 ;
     RECT  95.364 40.441 96.318 40.675 ;
     RECT  97.488 40.667 97.506 40.675 ;
     RECT  75.24 40.441 76.014 40.711 ;
     RECT  80.715 40.261 81.054 40.711 ;
     RECT  95.364 40.675 97.506 40.781 ;
     RECT  41.58 39.893 43.197 40.787 ;
     RECT  45.615 2.413 45.897 40.787 ;
     RECT  48.315 2.413 48.597 40.787 ;
     RECT  51.015 2.413 51.297 40.787 ;
     RECT  53.715 2.413 53.997 40.787 ;
     RECT  56.415 2.413 56.697 40.787 ;
     RECT  59.115 2.413 59.397 40.787 ;
     RECT  61.815 2.413 62.097 40.787 ;
     RECT  64.515 2.413 64.797 40.787 ;
     RECT  67.215 2.413 67.497 40.787 ;
     RECT  69.915 2.413 70.197 40.787 ;
     RECT  72.615 2.413 72.897 40.787 ;
     RECT  5.115 38.141 5.397 40.801 ;
     RECT  5.076 40.801 5.397 40.981 ;
     RECT  40.215 39.893 40.842 40.981 ;
     RECT  75.168 40.711 76.05 40.981 ;
     RECT  0.108 40.891 0.126 41.035 ;
     RECT  45.615 40.787 45.705 41.057 ;
     RECT  48.315 40.787 48.405 41.057 ;
     RECT  51.015 40.787 51.105 41.057 ;
     RECT  53.715 40.787 53.805 41.057 ;
     RECT  56.415 40.787 56.505 41.057 ;
     RECT  59.115 40.787 59.205 41.057 ;
     RECT  61.815 40.787 61.905 41.057 ;
     RECT  64.515 40.787 64.605 41.057 ;
     RECT  67.215 40.787 67.305 41.057 ;
     RECT  69.915 40.787 70.005 41.057 ;
     RECT  72.615 40.787 72.705 41.057 ;
     RECT  3.96 40.711 3.978 41.071 ;
     RECT  83.415 40.289 83.697 41.071 ;
     RECT  86.115 39.857 86.397 41.071 ;
     RECT  90.288 40.603 94.626 41.071 ;
     RECT  95.364 40.781 96.354 41.071 ;
     RECT  3.42 41.071 3.978 41.083 ;
     RECT  4.716 40.981 5.397 41.083 ;
     RECT  88.815 39.289 89.514 41.099 ;
     RECT  39.996 40.981 40.842 41.107 ;
     RECT  86.115 41.071 86.562 41.107 ;
     RECT  0.108 41.035 0.162 41.165 ;
     RECT  3.42 41.083 5.397 41.179 ;
     RECT  80.715 40.711 81.594 41.243 ;
     RECT  83.415 41.071 84.294 41.243 ;
     RECT  3.42 41.179 5.634 41.251 ;
     RECT  6.84 41.071 6.858 41.251 ;
     RECT  90.288 41.071 96.354 41.251 ;
     RECT  0.108 41.165 0.126 41.369 ;
     RECT  3.42 41.251 6.858 41.411 ;
     RECT  6.444 41.411 6.858 41.449 ;
     RECT  7.815 40.199 8.097 41.449 ;
     RECT  90.144 41.251 96.354 41.521 ;
     RECT  90.144 41.521 96.39 41.597 ;
     RECT  2.415 39.389 2.697 41.611 ;
     RECT  6.444 41.449 8.097 41.611 ;
     RECT  9.036 40.711 9.126 41.611 ;
     RECT  3.42 41.411 5.634 41.639 ;
     RECT  75.168 40.981 76.338 41.645 ;
     RECT  90.54 41.597 96.39 41.645 ;
     RECT  2.304 41.611 2.697 41.647 ;
     RECT  39.024 37.903 39.042 41.647 ;
     RECT  6.444 41.611 9.126 41.683 ;
     RECT  39.924 41.107 40.842 41.683 ;
     RECT  41.58 40.787 43.074 41.683 ;
     RECT  38.808 41.647 39.042 41.747 ;
     RECT  90.54 41.645 96.354 41.747 ;
     RECT  85.356 41.611 85.374 41.909 ;
     RECT  77.364 40.171 78.297 41.989 ;
     RECT  80.715 41.243 80.997 41.989 ;
     RECT  6.444 41.683 9.198 42.053 ;
     RECT  77.364 41.989 78.678 42.061 ;
     RECT  83.415 41.243 83.79 42.061 ;
     RECT  84.672 42.025 84.834 42.061 ;
     RECT  80.715 41.989 81.306 42.089 ;
     RECT  80.715 42.089 81.234 42.179 ;
     RECT  88.815 41.099 89.097 42.187 ;
     RECT  97.488 40.781 97.506 42.331 ;
     RECT  6.732 42.053 9.198 42.421 ;
     RECT  88.815 42.187 89.658 42.421 ;
     RECT  90.54 41.747 95.994 42.421 ;
     RECT  2.304 41.647 3.33 42.449 ;
     RECT  88.815 42.421 95.994 42.449 ;
     RECT  82.98 42.061 84.834 42.457 ;
     RECT  86.115 41.107 86.67 42.457 ;
     RECT  87.84 42.331 87.858 42.485 ;
     RECT  82.728 42.457 84.834 42.493 ;
     RECT  77.364 42.061 78.93 42.529 ;
     RECT  97.488 42.331 97.542 42.557 ;
     RECT  77.364 42.529 79.506 42.601 ;
     RECT  86.115 42.457 86.706 42.601 ;
     RECT  97.488 42.557 97.506 42.619 ;
     RECT  2.304 42.449 2.862 42.629 ;
     RECT  82.62 42.493 84.834 42.629 ;
     RECT  4.428 41.639 5.634 42.667 ;
     RECT  4.428 42.667 5.958 42.691 ;
     RECT  86.115 42.601 86.742 42.719 ;
     RECT  3.78 42.691 5.958 42.749 ;
     RECT  77.364 42.601 79.578 42.755 ;
     RECT  90.108 42.449 95.994 42.755 ;
     RECT  6.732 42.421 9.414 42.763 ;
     RECT  38.88 41.747 39.042 42.763 ;
     RECT  3.816 42.749 5.958 42.871 ;
     RECT  6.732 42.763 9.45 42.871 ;
     RECT  82.656 42.629 84.834 42.871 ;
     RECT  88.815 42.449 89.097 42.871 ;
     RECT  3.816 42.871 9.45 42.899 ;
     RECT  90.432 42.755 95.994 42.907 ;
     RECT  96.912 42.619 97.506 42.907 ;
     RECT  3.816 42.899 8.478 42.989 ;
     RECT  9.36 42.899 9.45 42.989 ;
     RECT  88.812 42.871 89.097 43.025 ;
     RECT  90.432 42.907 97.506 43.037 ;
     RECT  80.715 42.179 80.997 43.105 ;
     RECT  38.772 42.763 39.042 43.133 ;
     RECT  82.656 42.871 84.906 43.141 ;
     RECT  82.656 43.141 85.23 43.169 ;
     RECT  90.54 43.037 97.506 43.169 ;
     RECT  39.78 41.683 43.074 43.2 ;
     RECT  75.24 41.645 76.338 43.2 ;
     RECT  2.415 42.629 2.862 43.231 ;
     RECT  3.816 42.989 8.37 43.259 ;
     RECT  82.728 43.169 85.23 43.259 ;
     RECT  7.776 43.259 8.37 43.295 ;
     RECT  9.36 42.989 9.378 43.295 ;
     RECT  0.108 42.187 0.126 43.331 ;
     RECT  82.8 43.259 85.23 43.331 ;
     RECT  90.612 43.169 97.506 43.331 ;
     RECT  90.612 43.331 96.354 43.367 ;
     RECT  82.908 43.331 85.23 43.439 ;
     RECT  92.988 43.367 96.354 43.439 ;
     RECT  2.415 43.231 3.078 43.483 ;
     RECT  3.816 43.259 6.966 43.483 ;
     RECT  86.115 42.719 86.706 43.501 ;
     RECT  0.144 43.387 0.162 43.517 ;
     RECT  90.612 43.367 91.797 43.529 ;
     RECT  88.056 43.411 88.074 43.565 ;
     RECT  39.024 43.133 39.042 43.573 ;
     RECT  39.78 43.2 76.338 43.573 ;
     RECT  97.488 43.331 97.506 43.637 ;
     RECT  39.024 43.573 76.338 43.645 ;
     RECT  77.436 42.755 79.578 43.681 ;
     RECT  93.42 43.439 96.354 43.709 ;
     RECT  2.415 43.483 6.966 43.799 ;
     RECT  86.115 43.501 87.066 43.799 ;
     RECT  0.54 43.681 0.558 43.805 ;
     RECT  7.812 43.295 8.37 43.843 ;
     RECT  6.948 43.799 6.966 43.871 ;
     RECT  7.812 43.843 8.55 43.979 ;
     RECT  2.415 43.799 6.102 44.069 ;
     RECT  93.42 43.709 95.742 44.069 ;
     RECT  2.415 44.069 5.598 44.203 ;
     RECT  82.908 43.439 84.906 44.221 ;
     RECT  93.42 44.069 95.562 44.221 ;
     RECT  2.304 44.203 5.598 44.249 ;
     RECT  92.7 44.221 95.562 44.249 ;
     RECT  4.392 44.249 5.598 44.375 ;
     RECT  82.908 44.221 85.302 44.383 ;
     RECT  86.115 43.799 86.397 44.383 ;
     RECT  77.436 43.681 79.794 44.411 ;
     RECT  80.568 43.105 80.997 44.443 ;
     RECT  6.984 44.059 7.002 44.581 ;
     RECT  82.908 44.383 86.397 44.617 ;
     RECT  91.152 43.529 91.797 44.645 ;
     RECT  88.815 43.025 89.097 44.653 ;
     RECT  79.488 44.411 79.794 44.681 ;
     RECT  80.568 44.443 81.054 44.683 ;
     RECT  6.984 44.581 7.038 44.761 ;
     RECT  7.812 43.979 8.298 44.761 ;
     RECT  80.568 44.683 81.522 44.761 ;
     RECT  0.108 44.347 0.126 44.779 ;
     RECT  6.444 44.761 8.298 44.875 ;
     RECT  6.192 44.875 8.298 44.879 ;
     RECT  87.48 44.311 87.498 44.887 ;
     RECT  6.192 44.879 6.21 44.915 ;
     RECT  0.108 44.779 0.162 44.917 ;
     RECT  7.02 44.879 8.298 44.923 ;
     RECT  0.108 44.917 0.558 44.957 ;
     RECT  4.392 44.375 5.397 44.971 ;
     RECT  2.415 44.249 3.438 45.023 ;
     RECT  4.356 44.971 5.397 45.023 ;
     RECT  79.56 44.681 79.794 45.023 ;
     RECT  39.024 43.645 76.662 45.031 ;
     RECT  82.908 44.617 86.634 45.059 ;
     RECT  88.815 44.653 89.514 45.059 ;
     RECT  4.5 45.023 5.397 45.121 ;
     RECT  34.815 2.413 35.097 45.193 ;
     RECT  84.888 45.059 86.634 45.193 ;
     RECT  87.48 44.887 87.858 45.193 ;
     RECT  7.02 44.923 8.586 45.221 ;
     RECT  79.632 45.023 79.794 45.221 ;
     RECT  4.5 45.121 6.138 45.245 ;
     RECT  34.776 45.193 35.097 45.293 ;
     RECT  38.772 45.031 76.662 45.293 ;
     RECT  77.436 44.411 78.678 45.293 ;
     RECT  84.888 45.193 87.858 45.293 ;
     RECT  0.108 44.957 0.126 45.329 ;
     RECT  2.415 45.023 2.697 45.355 ;
     RECT  2.304 45.355 2.697 45.419 ;
     RECT  4.5 45.245 5.397 45.419 ;
     RECT  92.7 44.249 95.094 45.419 ;
     RECT  80.568 44.761 82.062 45.437 ;
     RECT  3.42 45.023 3.438 45.455 ;
     RECT  7.02 45.221 8.298 45.455 ;
     RECT  91.515 44.645 91.797 45.571 ;
     RECT  77.436 45.293 78.642 45.629 ;
     RECT  80.604 45.437 82.062 45.697 ;
     RECT  82.908 45.059 84.006 45.697 ;
     RECT  77.472 45.629 78.642 45.725 ;
     RECT  80.604 45.697 84.006 45.725 ;
     RECT  6.12 45.245 6.138 45.761 ;
     RECT  79.776 45.221 79.794 45.761 ;
     RECT  7.02 45.455 8.118 45.769 ;
     RECT  9.036 45.661 9.054 45.769 ;
     RECT  80.604 45.725 82.674 45.773 ;
     RECT  83.415 45.725 84.006 45.787 ;
     RECT  4.536 45.419 5.397 45.869 ;
     RECT  6.444 45.769 8.118 45.869 ;
     RECT  80.604 45.773 80.997 45.869 ;
     RECT  83.415 45.787 84.402 45.869 ;
     RECT  6.804 45.869 8.118 45.917 ;
     RECT  3.744 45.571 3.762 45.959 ;
     RECT  9.036 45.769 9.09 45.959 ;
     RECT  93.492 45.419 95.094 45.959 ;
     RECT  6.804 45.917 8.097 46.031 ;
     RECT  9.036 45.959 9.054 46.031 ;
     RECT  38.772 45.293 38.826 46.067 ;
     RECT  91.515 45.571 91.854 46.111 ;
     RECT  92.7 45.419 92.718 46.111 ;
     RECT  7.272 46.031 8.097 46.301 ;
     RECT  82.044 45.773 82.674 46.301 ;
     RECT  83.415 45.869 84.366 46.301 ;
     RECT  38.772 46.067 38.79 46.373 ;
     RECT  39.816 45.293 76.662 46.397 ;
     RECT  85.5 45.293 87.858 46.589 ;
     RECT  93.492 45.959 94.554 46.769 ;
     RECT  82.044 46.301 82.062 46.813 ;
     RECT  83.415 46.301 84.186 46.949 ;
     RECT  80.715 45.869 80.997 47.011 ;
     RECT  82.008 46.813 82.062 47.011 ;
     RECT  77.508 45.725 78.642 47.117 ;
     RECT  80.715 47.011 82.062 47.165 ;
     RECT  80.715 47.165 81.522 47.579 ;
     RECT  91.515 46.111 92.718 47.615 ;
     RECT  77.508 47.117 78.606 47.645 ;
     RECT  77.508 47.645 78.297 47.965 ;
     RECT  76.644 46.397 76.662 48.361 ;
     RECT  77.4 47.965 78.297 48.361 ;
     RECT  76.644 48.361 78.297 48.413 ;
     RECT  76.932 48.413 78.297 48.509 ;
     RECT  39.816 46.397 75.798 48.667 ;
     RECT  76.968 48.509 78.297 48.893 ;
     RECT  77.544 48.893 78.297 49.181 ;
     RECT  39.816 48.667 75.834 49.277 ;
     RECT  77.58 49.181 78.297 49.277 ;
     RECT  39.996 49.277 75.834 49.351 ;
     RECT  39.996 49.351 75.87 49.441 ;
     RECT  39.996 49.441 76.41 49.565 ;
     RECT  77.616 49.277 78.297 50.107 ;
     RECT  77.58 50.107 78.297 50.153 ;
     RECT  42.48 49.565 76.41 50.237 ;
     RECT  92.7 47.615 92.718 50.279 ;
     RECT  39.996 49.565 41.274 50.333 ;
     RECT  39.996 50.333 41.202 50.389 ;
     RECT  93.492 46.769 94.497 50.395 ;
     RECT  39.672 50.389 41.202 50.429 ;
     RECT  38.88 50.395 38.898 50.431 ;
     RECT  39.672 50.429 41.166 50.431 ;
     RECT  86.115 46.589 87.858 50.549 ;
     RECT  91.515 47.615 91.797 50.665 ;
     RECT  37.515 2.413 37.797 50.731 ;
     RECT  38.88 50.431 41.166 50.731 ;
     RECT  76.356 50.237 76.41 50.813 ;
     RECT  87.84 50.549 87.858 50.819 ;
     RECT  42.48 50.237 75.192 50.875 ;
     RECT  88.815 45.059 89.097 50.935 ;
     RECT  93.024 50.395 94.497 50.935 ;
     RECT  37.515 50.731 41.166 51.089 ;
     RECT  42.156 50.875 75.192 51.101 ;
     RECT  77.616 50.153 78.297 51.205 ;
     RECT  88.815 50.935 89.766 51.205 ;
     RECT  90.9 50.665 91.797 51.205 ;
     RECT  39.024 51.089 41.166 51.241 ;
     RECT  39.024 51.241 41.634 51.269 ;
     RECT  77.58 51.205 78.297 51.293 ;
     RECT  86.115 50.549 86.994 51.359 ;
     RECT  88.815 51.205 91.797 51.367 ;
     RECT  93.024 50.935 94.554 51.367 ;
     RECT  77.616 51.293 78.297 51.395 ;
     RECT  42.768 51.101 75.192 51.677 ;
     RECT  39.06 51.269 41.634 51.871 ;
     RECT  39.06 51.871 42.174 52.051 ;
     RECT  37.515 51.089 37.797 52.177 ;
     RECT  38.52 52.051 42.174 52.177 ;
     RECT  77.652 51.395 78.297 52.219 ;
     RECT  37.515 52.177 42.174 52.253 ;
     RECT  43.092 51.677 75.192 52.285 ;
     RECT  76.392 50.813 76.41 52.285 ;
     RECT  77.58 52.219 78.297 52.315 ;
     RECT  77.4 52.315 78.297 52.475 ;
     RECT  95.76 52.411 95.778 52.589 ;
     RECT  38.7 52.253 42.174 52.781 ;
     RECT  43.092 52.285 76.41 52.789 ;
     RECT  86.115 51.359 86.397 52.789 ;
     RECT  38.7 52.781 41.598 52.979 ;
     RECT  97.488 52.699 97.506 53.021 ;
     RECT  42.444 52.789 76.41 53.024 ;
     RECT  88.815 51.367 94.554 53.131 ;
     RECT  88.815 53.131 95.238 53.365 ;
     RECT  77.508 52.475 78.297 53.371 ;
     RECT  88.815 53.365 95.778 53.453 ;
     RECT  38.736 52.979 41.598 53.549 ;
     RECT  39.24 53.549 41.598 53.563 ;
     RECT  42.444 53.024 75.834 53.563 ;
     RECT  76.644 53.467 76.698 53.563 ;
     RECT  77.436 53.371 78.297 53.563 ;
     RECT  88.815 53.453 95.238 53.591 ;
     RECT  39.24 53.563 75.834 53.789 ;
     RECT  88.815 53.591 95.202 53.789 ;
     RECT  96.912 53.401 96.93 53.851 ;
     RECT  96.912 53.851 96.966 53.995 ;
     RECT  39.24 53.789 75.762 54.059 ;
     RECT  96.912 53.995 97.506 54.139 ;
     RECT  96.336 54.139 97.506 54.283 ;
     RECT  96.3 54.283 97.506 54.401 ;
     RECT  37.515 52.253 37.797 54.445 ;
     RECT  39.24 54.059 41.166 54.445 ;
     RECT  86.115 52.789 86.67 54.473 ;
     RECT  88.815 53.789 95.166 54.571 ;
     RECT  37.515 54.445 41.166 54.599 ;
     RECT  37.515 54.599 38.646 54.743 ;
     RECT  39.996 54.599 41.166 55.021 ;
     RECT  41.976 54.059 75.762 55.021 ;
     RECT  96.336 54.401 97.506 55.147 ;
     RECT  96.3 55.147 97.506 55.211 ;
     RECT  39.996 55.021 75.762 55.489 ;
     RECT  76.644 53.563 78.297 55.489 ;
     RECT  88.815 54.571 95.382 55.831 ;
     RECT  96.912 55.211 97.506 56.155 ;
     RECT  96.912 56.155 97.542 56.291 ;
     RECT  88.815 55.831 95.454 56.299 ;
     RECT  97.452 56.291 97.542 56.327 ;
     RECT  88.815 56.299 95.742 56.759 ;
     RECT  90.144 56.759 95.742 56.831 ;
     RECT  93.6 56.831 95.742 56.911 ;
     RECT  90.144 56.831 92.826 57.029 ;
     RECT  92.52 57.029 92.826 57.101 ;
     RECT  97.452 56.327 97.506 57.137 ;
     RECT  97.452 57.137 97.47 57.479 ;
     RECT  93.6 56.911 95.994 57.569 ;
     RECT  39.996 55.489 78.297 58.649 ;
     RECT  39.996 58.649 76.158 60.504 ;
     RECT  90.144 57.029 91.797 60.511 ;
     RECT  92.52 57.101 92.754 60.511 ;
     RECT  90.144 60.511 92.754 60.539 ;
     RECT  90.144 60.539 92.538 60.611 ;
     RECT  70.776 60.504 70.866 60.647 ;
     RECT  74.736 60.504 76.158 60.647 ;
     RECT  92.52 60.611 92.538 60.647 ;
     RECT  70.776 60.647 70.794 60.881 ;
     RECT  74.808 60.647 76.158 60.881 ;
     RECT  77.22 58.649 78.297 61.051 ;
     RECT  86.115 54.473 86.397 61.051 ;
     RECT  93.6 57.569 95.454 61.079 ;
     RECT  93.6 61.079 94.497 61.115 ;
     RECT  77.22 61.051 78.678 61.181 ;
     RECT  86.115 61.051 86.67 61.181 ;
     RECT  94.068 61.115 94.497 61.181 ;
     RECT  39.996 60.504 43.146 61.187 ;
     RECT  90.144 60.611 91.797 61.187 ;
     RECT  77.22 61.181 78.354 61.223 ;
     RECT  75.204 60.881 76.158 61.259 ;
     RECT  77.796 61.223 78.354 61.349 ;
     RECT  75.204 61.259 76.086 61.385 ;
     RECT  77.796 61.349 78.297 61.421 ;
     RECT  76.068 61.385 76.086 61.457 ;
     RECT  39.996 61.187 41.922 61.619 ;
     RECT  95.436 61.079 95.454 61.619 ;
     RECT  41.904 61.619 41.922 61.655 ;
     RECT  90.144 61.187 90.162 61.655 ;
     RECT  75.204 61.385 75.33 62.473 ;
     RECT  42.732 61.187 43.146 62.537 ;
     RECT  50.328 62.509 50.346 62.545 ;
     RECT  49.788 62.545 50.346 62.581 ;
     RECT  74.664 62.473 75.33 62.609 ;
     RECT  49.716 62.581 50.346 62.623 ;
     RECT  75.204 62.609 75.33 62.623 ;
     RECT  49.716 62.623 51.105 62.699 ;
     RECT  91.152 61.187 91.797 62.699 ;
     RECT  75.204 62.623 75.405 62.735 ;
     RECT  50.328 62.699 51.105 62.879 ;
     RECT  42.915 62.537 43.146 62.893 ;
     RECT  45.615 62.623 45.705 62.893 ;
     RECT  48.315 62.623 48.405 62.893 ;
     RECT  51.015 62.879 51.105 62.893 ;
     RECT  53.715 62.623 53.805 62.893 ;
     RECT  56.415 62.623 56.505 62.893 ;
     RECT  59.115 62.623 59.205 62.893 ;
     RECT  61.815 62.623 61.905 62.893 ;
     RECT  64.515 62.623 64.605 62.893 ;
     RECT  67.215 62.623 67.305 62.893 ;
     RECT  69.915 62.623 70.005 62.893 ;
     RECT  72.615 62.623 72.705 62.893 ;
     RECT  75.24 62.735 75.405 62.893 ;
     RECT  75.24 62.893 75.597 62.969 ;
     RECT  42.915 62.893 43.197 64.561 ;
     RECT  42.915 64.561 43.542 64.637 ;
     RECT  42.915 64.637 43.326 64.877 ;
     RECT  42.915 64.877 43.254 64.973 ;
     RECT  94.215 61.181 94.497 70.795 ;
     RECT  93.492 70.795 94.497 70.835 ;
     RECT  93.528 70.835 94.497 71.219 ;
     RECT  77.076 73.771 77.094 73.813 ;
     RECT  61.815 62.893 62.097 73.915 ;
     RECT  69.915 62.893 70.197 73.915 ;
     RECT  46.764 73.819 46.782 73.949 ;
     RECT  54.72 73.819 54.738 73.949 ;
     RECT  61.815 73.915 62.73 74.093 ;
     RECT  69.915 73.915 70.722 74.093 ;
     RECT  76.752 73.813 77.094 74.093 ;
     RECT  76.752 74.093 76.77 74.309 ;
     RECT  10.515 39.821 10.797 76.171 ;
     RECT  13.215 2.413 13.497 76.207 ;
     RECT  6.84 76.171 6.858 76.301 ;
     RECT  13.215 76.207 13.59 76.315 ;
     RECT  10.515 76.171 10.854 76.349 ;
     RECT  13.215 76.315 13.914 76.379 ;
     RECT  2.415 45.419 2.697 78.511 ;
     RECT  2.415 78.511 2.898 78.601 ;
     RECT  4.212 78.511 4.23 78.601 ;
     RECT  2.415 78.601 4.23 78.629 ;
     RECT  7.815 46.301 8.097 78.943 ;
     RECT  0.108 78.907 0.126 78.979 ;
     RECT  5.115 45.869 5.397 79.015 ;
     RECT  6.84 78.943 6.858 79.015 ;
     RECT  42.915 64.973 43.197 79.015 ;
     RECT  5.115 79.015 5.85 79.051 ;
     RECT  6.84 79.015 6.966 79.051 ;
     RECT  7.815 78.943 8.154 79.051 ;
     RECT  0.108 78.979 0.162 79.079 ;
     RECT  0.144 79.079 0.162 79.085 ;
     RECT  5.115 79.051 6.966 79.177 ;
     RECT  7.815 79.051 8.514 79.177 ;
     RECT  2.415 78.629 3.618 79.213 ;
     RECT  5.115 79.177 8.514 79.213 ;
     RECT  2.304 79.213 3.618 79.373 ;
     RECT  5.115 79.213 8.586 79.439 ;
     RECT  42.336 79.015 43.197 79.447 ;
     RECT  5.115 79.439 8.55 79.579 ;
     RECT  39.996 61.619 41.166 79.591 ;
     RECT  42.3 79.447 43.197 79.591 ;
     RECT  2.415 79.373 3.618 79.619 ;
     RECT  3.42 79.619 3.618 79.753 ;
     RECT  4.5 79.579 8.55 79.753 ;
     RECT  3.42 79.753 8.55 80.159 ;
     RECT  3.42 80.159 3.906 80.249 ;
     RECT  2.415 79.619 2.697 80.491 ;
     RECT  5.004 80.159 8.55 80.563 ;
     RECT  37.515 54.743 38.394 80.563 ;
     RECT  0.144 79.819 0.162 80.635 ;
     RECT  5.004 80.563 9.45 80.789 ;
     RECT  2.304 80.491 2.697 80.869 ;
     RECT  3.42 80.249 3.654 80.869 ;
     RECT  2.304 80.869 3.654 80.969 ;
     RECT  2.415 80.969 3.654 80.971 ;
     RECT  2.415 80.971 4.122 81.005 ;
     RECT  94.215 71.219 94.497 81.031 ;
     RECT  1.116 80.923 1.134 81.053 ;
     RECT  4.104 81.005 4.122 81.211 ;
     RECT  5.004 80.789 6.93 81.211 ;
     RECT  94.215 81.031 94.878 81.211 ;
     RECT  94.104 81.211 95.382 81.307 ;
     RECT  4.104 81.211 6.93 81.329 ;
     RECT  2.415 81.005 3.186 81.437 ;
     RECT  0.108 80.635 0.162 81.509 ;
     RECT  7.815 80.789 9.414 81.509 ;
     RECT  6.408 81.329 6.93 81.571 ;
     RECT  37.515 80.563 38.79 81.643 ;
     RECT  93.924 81.307 95.382 81.643 ;
     RECT  96.3 81.355 96.318 81.68 ;
     RECT  91.515 62.699 91.797 81.715 ;
     RECT  93.024 81.607 93.042 81.715 ;
     RECT  93.78 81.643 95.382 81.715 ;
     RECT  6.408 81.571 6.966 81.751 ;
     RECT  7.815 81.509 9.162 81.751 ;
     RECT  2.415 81.437 2.697 81.787 ;
     RECT  93.024 81.715 95.382 81.787 ;
     RECT  90.684 81.571 90.702 81.869 ;
     RECT  93.024 81.787 95.922 81.869 ;
     RECT  10.515 76.349 10.797 81.913 ;
     RECT  97.488 81.499 97.506 81.913 ;
     RECT  4.104 81.329 5.634 81.931 ;
     RECT  97.488 81.913 97.578 81.931 ;
     RECT  91.515 81.715 91.998 81.949 ;
     RECT  93.024 81.869 93.042 81.949 ;
     RECT  10.515 81.913 10.818 82.013 ;
     RECT  75.315 62.969 75.597 82.021 ;
     RECT  6.408 81.751 9.162 82.061 ;
     RECT  2.304 81.787 2.697 82.075 ;
     RECT  2.268 82.075 2.697 82.139 ;
     RECT  84.564 81.877 84.582 82.139 ;
     RECT  90.54 81.976 90.63 82.147 ;
     RECT  90.072 82.147 90.63 82.175 ;
     RECT  2.304 82.139 2.697 82.219 ;
     RECT  3.636 81.931 5.634 82.219 ;
     RECT  2.304 82.219 2.754 82.255 ;
     RECT  3.636 82.219 5.814 82.255 ;
     RECT  37.515 81.643 38.826 82.255 ;
     RECT  75.315 82.021 75.654 82.291 ;
     RECT  84.492 82.147 84.51 82.319 ;
     RECT  0.144 81.509 0.162 82.363 ;
     RECT  6.552 82.061 9.162 82.409 ;
     RECT  0.144 82.363 0.234 82.493 ;
     RECT  37.515 82.255 38.898 82.517 ;
     RECT  88.815 56.759 89.097 82.561 ;
     RECT  90.072 82.175 90.162 82.561 ;
     RECT  0.108 82.507 0.126 82.589 ;
     RECT  91.515 81.949 93.042 82.651 ;
     RECT  2.304 82.255 5.814 82.679 ;
     RECT  93.78 81.869 95.382 82.723 ;
     RECT  75.168 82.291 75.654 82.831 ;
     RECT  76.86 82.291 76.878 82.831 ;
     RECT  83.415 46.949 83.697 82.831 ;
     RECT  93.78 82.723 95.886 82.831 ;
     RECT  96.912 81.931 97.578 82.831 ;
     RECT  88.815 82.561 90.162 82.921 ;
     RECT  91.26 82.651 93.042 82.921 ;
     RECT  93.78 82.831 97.578 82.921 ;
     RECT  83.415 82.831 84.078 82.949 ;
     RECT  3.528 82.679 5.814 82.973 ;
     RECT  91.26 82.921 97.578 82.973 ;
     RECT  88.815 82.921 90.45 83.065 ;
     RECT  91.26 82.973 95.994 83.065 ;
     RECT  84.924 82.957 84.978 83.093 ;
     RECT  10.515 82.013 10.797 83.101 ;
     RECT  2.304 82.679 2.697 83.129 ;
     RECT  3.672 82.973 5.814 83.219 ;
     RECT  84.96 83.093 84.978 83.219 ;
     RECT  96.912 82.973 97.578 83.261 ;
     RECT  6.552 82.409 8.37 83.371 ;
     RECT  3.672 83.219 5.397 83.399 ;
     RECT  0.144 83.275 0.162 83.405 ;
     RECT  6.552 83.371 8.514 83.489 ;
     RECT  83.415 82.949 84.042 83.489 ;
     RECT  39.996 79.591 43.197 83.515 ;
     RECT  39.996 83.515 43.29 83.611 ;
     RECT  37.515 82.517 38.862 83.633 ;
     RECT  83.415 83.489 83.79 83.641 ;
     RECT  10.515 83.101 10.926 83.669 ;
     RECT  6.552 83.489 8.37 83.759 ;
     RECT  39.996 83.611 43.614 83.759 ;
     RECT  88.815 83.065 95.994 83.759 ;
     RECT  3.744 83.399 5.397 83.789 ;
     RECT  7.815 83.759 8.37 83.789 ;
     RECT  83.34 83.641 83.79 83.795 ;
     RECT  3.744 83.789 3.762 83.831 ;
     RECT  79.812 83.533 79.83 83.903 ;
     RECT  6.552 83.759 6.57 83.939 ;
     RECT  45.615 62.893 45.897 83.987 ;
     RECT  48.315 62.893 48.597 83.987 ;
     RECT  51.015 62.893 51.297 83.987 ;
     RECT  53.715 62.893 53.997 83.987 ;
     RECT  56.415 62.893 56.697 83.987 ;
     RECT  59.115 62.893 59.397 83.987 ;
     RECT  61.815 74.093 62.097 83.987 ;
     RECT  64.515 62.893 64.797 83.987 ;
     RECT  67.215 62.893 67.497 83.987 ;
     RECT  69.915 74.093 70.197 83.987 ;
     RECT  72.615 62.893 72.897 83.987 ;
     RECT  37.515 83.633 38.79 84.029 ;
     RECT  84.924 83.911 84.942 84.029 ;
     RECT  83.415 83.795 83.79 84.065 ;
     RECT  96.912 83.261 97.542 84.091 ;
     RECT  96.912 84.091 97.578 84.101 ;
     RECT  75.168 82.831 76.878 84.109 ;
     RECT  44.784 84.073 44.802 84.125 ;
     RECT  66.168 84.073 66.186 84.125 ;
     RECT  82.656 83.875 82.674 84.173 ;
     RECT  75.168 84.109 76.986 84.181 ;
     RECT  78.015 61.421 78.297 84.181 ;
     RECT  97.488 84.101 97.578 84.209 ;
     RECT  45.615 83.987 45.705 84.257 ;
     RECT  48.315 83.987 48.405 84.257 ;
     RECT  51.015 83.987 51.105 84.257 ;
     RECT  53.715 83.987 53.805 84.257 ;
     RECT  56.415 83.987 56.505 84.257 ;
     RECT  59.115 83.987 59.205 84.257 ;
     RECT  61.815 83.987 61.905 84.257 ;
     RECT  64.515 83.987 64.746 84.257 ;
     RECT  67.215 83.987 67.305 84.257 ;
     RECT  69.915 83.987 70.005 84.257 ;
     RECT  72.615 83.987 72.705 84.257 ;
     RECT  83.415 84.065 83.718 84.299 ;
     RECT  39.996 83.759 43.218 84.365 ;
     RECT  64.728 84.257 64.746 84.365 ;
     RECT  4.5 83.789 5.397 84.407 ;
     RECT  88.815 83.759 95.814 84.523 ;
     RECT  2.415 83.129 2.697 84.721 ;
     RECT  97.488 84.209 97.542 84.749 ;
     RECT  5.115 84.407 5.397 84.763 ;
     RECT  0.108 84.667 0.126 84.811 ;
     RECT  88.815 84.523 95.922 84.847 ;
     RECT  3.996 84.811 4.014 84.848 ;
     RECT  39.996 84.365 42.894 84.883 ;
     RECT  6.768 84.721 6.786 84.919 ;
     RECT  7.815 83.789 8.097 84.919 ;
     RECT  75.168 84.181 78.297 84.989 ;
     RECT  85.032 84.649 85.05 84.991 ;
     RECT  86.115 61.181 86.397 84.991 ;
     RECT  7.56 84.919 8.097 85.051 ;
     RECT  39.528 84.883 42.894 85.109 ;
     RECT  88.815 84.847 96.354 85.133 ;
     RECT  39.6 85.109 42.894 85.181 ;
     RECT  6.624 84.919 6.786 85.189 ;
     RECT  7.56 85.051 8.622 85.189 ;
     RECT  83.415 84.299 83.697 85.189 ;
     RECT  75.204 84.989 78.297 85.225 ;
     RECT  84.96 84.991 85.05 85.225 ;
     RECT  6.624 85.189 8.622 85.261 ;
     RECT  37.515 84.029 38.394 85.261 ;
     RECT  80.715 47.579 80.997 85.261 ;
     RECT  83.415 85.189 83.862 85.261 ;
     RECT  84.924 85.225 85.05 85.261 ;
     RECT  5.115 84.763 5.634 85.351 ;
     RECT  88.815 85.133 95.922 85.379 ;
     RECT  80.424 85.261 80.997 85.387 ;
     RECT  97.488 84.749 97.506 85.387 ;
     RECT  84.816 85.261 85.05 85.415 ;
     RECT  0.108 84.811 0.162 85.451 ;
     RECT  6.552 85.261 8.622 85.459 ;
     RECT  37.515 85.261 38.79 85.487 ;
     RECT  80.244 85.387 80.997 85.487 ;
     RECT  82.584 85.387 82.602 85.487 ;
     RECT  2.415 84.721 3.222 85.517 ;
     RECT  4.572 85.351 5.634 85.531 ;
     RECT  6.552 85.459 8.766 85.559 ;
     RECT  83.376 85.261 83.862 85.621 ;
     RECT  2.415 85.517 2.826 85.649 ;
     RECT  4.572 85.531 5.706 85.723 ;
     RECT  3.564 85.531 3.582 85.729 ;
     RECT  6.732 85.559 8.766 85.729 ;
     RECT  96.912 85.387 97.506 85.757 ;
     RECT  0.144 85.451 0.162 85.771 ;
     RECT  3.564 85.729 3.654 85.771 ;
     RECT  4.5 85.723 5.706 85.771 ;
     RECT  75.204 85.225 78.354 85.801 ;
     RECT  0.144 85.771 0.234 85.829 ;
     RECT  82.656 85.621 83.862 85.829 ;
     RECT  85.032 85.415 85.05 85.829 ;
     RECT  6.732 85.729 9.09 85.919 ;
     RECT  88.815 85.379 95.85 85.919 ;
     RECT  88.815 85.919 95.814 85.991 ;
     RECT  96.912 85.757 96.966 85.991 ;
     RECT  88.815 85.991 90.702 86.027 ;
     RECT  91.44 85.991 95.814 86.027 ;
     RECT  82.656 85.829 83.79 86.063 ;
     RECT  39.672 85.181 42.894 86.071 ;
     RECT  86.115 84.991 86.706 86.197 ;
     RECT  6.732 85.919 8.91 86.225 ;
     RECT  88.815 86.027 90.666 86.225 ;
     RECT  39.636 86.071 42.894 86.233 ;
     RECT  96.948 85.991 96.966 86.261 ;
     RECT  90.144 86.225 90.666 86.297 ;
     RECT  37.515 85.487 38.394 86.305 ;
     RECT  7.128 86.225 8.91 86.333 ;
     RECT  39.564 86.233 42.894 86.4 ;
     RECT  75.204 85.801 78.93 86.4 ;
     RECT  2.415 85.649 2.79 86.431 ;
     RECT  3.564 85.771 5.706 86.431 ;
     RECT  81.756 86.035 81.774 86.431 ;
     RECT  86.115 86.197 87.21 86.459 ;
     RECT  0.144 85.829 0.162 86.525 ;
     RECT  7.38 86.333 8.91 86.531 ;
     RECT  90.396 86.297 90.666 86.531 ;
     RECT  86.115 86.459 86.67 86.567 ;
     RECT  91.44 86.027 95.31 86.603 ;
     RECT  37.515 86.305 38.79 86.611 ;
     RECT  39.564 86.4 78.93 86.611 ;
     RECT  2.415 86.431 6.174 86.717 ;
     RECT  2.415 86.717 2.79 86.729 ;
     RECT  91.44 86.603 95.238 86.729 ;
     RECT  92.952 86.729 95.238 86.801 ;
     RECT  3.6 86.717 6.174 86.837 ;
     RECT  90.396 86.531 90.486 86.837 ;
     RECT  10.515 83.669 10.797 86.881 ;
     RECT  83.304 86.063 83.79 86.881 ;
     RECT  84.528 86.305 84.546 86.881 ;
     RECT  4.212 86.837 6.174 86.909 ;
     RECT  92.952 86.801 95.202 86.909 ;
     RECT  81.756 86.431 82.386 86.971 ;
     RECT  83.16 86.881 84.546 86.971 ;
     RECT  91.44 86.729 91.797 87.035 ;
     RECT  7.815 86.531 8.91 87.043 ;
     RECT  10.515 86.881 10.998 87.179 ;
     RECT  7.815 87.043 8.982 87.349 ;
     RECT  2.415 86.729 2.697 87.403 ;
     RECT  2.304 87.403 2.697 87.449 ;
     RECT  6.408 87.241 6.426 87.511 ;
     RECT  7.38 87.349 8.982 87.539 ;
     RECT  81.756 86.971 84.546 87.539 ;
     RECT  6.408 87.511 6.498 87.583 ;
     RECT  7.38 87.539 8.406 87.583 ;
     RECT  34.815 45.293 35.097 87.583 ;
     RECT  0.108 86.971 0.126 87.595 ;
     RECT  37.515 86.611 78.93 87.619 ;
     RECT  86.115 86.567 86.397 87.619 ;
     RECT  6.408 87.583 8.406 87.647 ;
     RECT  34.776 87.583 35.097 87.683 ;
     RECT  4.212 86.909 5.634 87.691 ;
     RECT  0.108 87.595 0.198 87.719 ;
     RECT  37.515 87.619 79.362 87.719 ;
     RECT  0.18 87.719 0.198 87.725 ;
     RECT  2.415 87.449 2.697 87.781 ;
     RECT  3.78 87.691 5.634 87.781 ;
     RECT  6.408 87.647 8.37 87.781 ;
     RECT  3.78 87.781 8.37 87.821 ;
     RECT  6.156 87.821 8.37 87.845 ;
     RECT  6.192 87.845 8.37 87.917 ;
     RECT  2.415 87.781 2.79 87.925 ;
     RECT  93.132 86.909 95.202 87.961 ;
     RECT  3.78 87.821 5.397 88.051 ;
     RECT  90.396 86.837 90.414 88.051 ;
     RECT  2.415 87.925 2.862 88.075 ;
     RECT  3.672 88.051 5.397 88.075 ;
     RECT  10.515 87.179 10.818 88.115 ;
     RECT  2.415 88.075 5.397 88.157 ;
     RECT  91.476 87.035 91.797 88.195 ;
     RECT  92.988 87.961 95.202 88.195 ;
     RECT  37.515 87.719 78.93 88.223 ;
     RECT  91.476 88.195 95.202 88.349 ;
     RECT  9.144 87.619 9.162 88.429 ;
     RECT  81.756 87.539 83.79 88.493 ;
     RECT  6.228 87.917 8.37 88.501 ;
     RECT  9.144 88.429 9.234 88.501 ;
     RECT  90.396 88.051 90.666 88.501 ;
     RECT  2.415 88.157 3.258 88.555 ;
     RECT  2.304 88.555 3.258 88.619 ;
     RECT  6.228 88.501 9.234 88.619 ;
     RECT  90.396 88.501 90.702 88.619 ;
     RECT  84.528 87.539 84.546 88.699 ;
     RECT  85.752 87.619 86.397 88.699 ;
     RECT  37.515 88.223 78.786 88.727 ;
     RECT  39.312 88.727 78.786 88.733 ;
     RECT  84.528 88.699 86.397 88.733 ;
     RECT  0.108 88.699 0.126 88.747 ;
     RECT  82.584 88.493 83.79 88.771 ;
     RECT  85.248 88.733 86.397 88.771 ;
     RECT  88.815 86.225 89.097 88.771 ;
     RECT  0.108 88.747 0.198 88.877 ;
     RECT  85.248 88.771 86.67 88.889 ;
     RECT  39.312 88.733 78.678 88.925 ;
     RECT  82.584 88.771 83.898 88.925 ;
     RECT  90.684 88.619 90.702 88.925 ;
     RECT  2.415 88.619 3.258 89.041 ;
     RECT  4.032 88.157 5.397 89.041 ;
     RECT  77.364 88.925 78.678 89.069 ;
     RECT  88.344 88.771 89.097 89.069 ;
     RECT  2.415 89.041 5.397 89.131 ;
     RECT  2.415 89.131 5.706 89.159 ;
     RECT  6.768 88.619 9.054 89.159 ;
     RECT  82.584 88.925 83.79 89.195 ;
     RECT  7.815 89.159 8.982 89.231 ;
     RECT  0.108 88.877 0.126 89.261 ;
     RECT  3.888 89.159 3.906 89.267 ;
     RECT  91.476 88.349 95.022 89.267 ;
     RECT  91.476 89.267 91.797 89.311 ;
     RECT  77.364 89.069 78.354 89.312 ;
     RECT  7.815 89.231 8.586 89.339 ;
     RECT  4.752 89.159 5.706 89.429 ;
     RECT  82.62 89.195 83.79 89.453 ;
     RECT  91.224 89.311 91.797 89.465 ;
     RECT  6.768 89.159 6.858 89.515 ;
     RECT  82.62 89.453 83.697 89.549 ;
     RECT  2.415 89.159 3.078 89.573 ;
     RECT  37.515 88.727 38.394 89.581 ;
     RECT  39.312 88.925 76.482 89.581 ;
     RECT  77.472 89.312 78.354 89.597 ;
     RECT  6.48 89.515 6.858 89.699 ;
     RECT  34.815 87.683 35.097 89.707 ;
     RECT  37.515 89.581 76.482 89.807 ;
     RECT  34.776 89.707 35.097 89.843 ;
     RECT  90.648 89.851 90.666 90.005 ;
     RECT  39.312 89.807 76.482 90.091 ;
     RECT  84.888 90.091 84.906 90.121 ;
     RECT  92.916 89.267 95.022 90.121 ;
     RECT  39.312 90.091 76.518 90.149 ;
     RECT  84.456 90.121 84.906 90.149 ;
     RECT  39.312 90.149 76.446 90.173 ;
     RECT  83.415 89.549 83.697 90.211 ;
     RECT  84.456 90.149 84.474 90.211 ;
     RECT  85.752 88.889 86.67 90.211 ;
     RECT  82.62 89.549 82.638 90.235 ;
     RECT  83.415 90.211 84.474 90.239 ;
     RECT  92.664 90.121 95.022 90.239 ;
     RECT  82.08 90.235 82.638 90.311 ;
     RECT  83.415 90.239 84.078 90.311 ;
     RECT  85.752 90.211 86.706 90.383 ;
     RECT  92.988 90.239 95.022 90.545 ;
     RECT  82.62 90.311 82.638 90.557 ;
     RECT  83.415 90.311 83.79 90.653 ;
     RECT  77.508 89.597 78.354 91.085 ;
     RECT  39.312 90.173 75.762 91.325 ;
     RECT  39.312 91.325 75.51 91.613 ;
     RECT  76.32 91.471 76.338 91.705 ;
     RECT  76.32 91.705 76.374 91.805 ;
     RECT  76.356 91.805 76.374 91.901 ;
     RECT  77.508 91.085 78.297 92.011 ;
     RECT  76.392 92.011 78.297 92.273 ;
     RECT  39.312 91.613 75.192 92.515 ;
     RECT  76.932 92.273 78.297 92.669 ;
     RECT  37.515 89.807 38.394 92.821 ;
     RECT  39.168 92.515 75.192 92.821 ;
     RECT  77.544 92.669 78.297 93.245 ;
     RECT  37.515 92.821 75.192 93.533 ;
     RECT  80.715 85.487 80.997 93.595 ;
     RECT  76.392 93.091 76.41 93.793 ;
     RECT  85.752 90.383 86.397 94.019 ;
     RECT  42.768 93.533 75.192 94.027 ;
     RECT  76.356 93.793 76.41 94.027 ;
     RECT  88.815 89.069 89.097 94.027 ;
     RECT  92.988 90.545 93.294 94.135 ;
     RECT  94.215 90.545 95.022 94.135 ;
     RECT  92.988 94.135 95.022 94.289 ;
     RECT  22.644 94.261 22.662 94.301 ;
     RECT  37.515 93.533 41.526 94.363 ;
     RECT  80.676 93.595 80.997 94.405 ;
     RECT  37.515 94.363 41.598 94.441 ;
     RECT  22.32 94.405 22.338 94.445 ;
     RECT  37.515 94.441 41.634 94.469 ;
     RECT  77.58 93.245 78.297 94.493 ;
     RECT  39.276 94.469 41.634 94.531 ;
     RECT  42.768 94.027 76.41 94.531 ;
     RECT  77.652 94.493 78.297 94.559 ;
     RECT  39.276 94.531 76.41 94.685 ;
     RECT  39.276 94.685 75.192 95.251 ;
     RECT  77.688 94.559 78.297 95.515 ;
     RECT  37.515 94.469 38.286 95.521 ;
     RECT  39.132 95.251 75.192 95.521 ;
     RECT  37.515 95.521 75.192 95.675 ;
     RECT  37.515 95.675 41.598 95.783 ;
     RECT  37.515 95.783 38.61 95.789 ;
     RECT  91.515 89.465 91.797 95.881 ;
     RECT  77.58 95.515 78.297 95.899 ;
     RECT  39.816 95.783 41.598 95.945 ;
     RECT  93.564 94.289 94.878 96.061 ;
     RECT  93.492 96.061 94.878 96.151 ;
     RECT  91.515 95.881 92.322 96.187 ;
     RECT  93.276 96.151 94.878 96.187 ;
     RECT  76.392 94.685 76.41 96.215 ;
     RECT  77.436 95.899 78.297 96.259 ;
     RECT  88.815 94.027 89.766 96.331 ;
     RECT  77.22 96.259 78.297 96.379 ;
     RECT  88.815 96.331 90.162 96.449 ;
     RECT  42.444 95.675 75.192 96.475 ;
     RECT  96.3 96.331 96.318 96.475 ;
     RECT  86.115 94.019 86.397 96.529 ;
     RECT  91.515 96.187 94.878 96.565 ;
     RECT  91.08 96.565 94.878 96.601 ;
     RECT  96.3 96.475 96.93 96.601 ;
     RECT  98.244 96.571 98.262 96.601 ;
     RECT  96.3 96.601 98.262 96.629 ;
     RECT  96.3 96.629 98.19 96.653 ;
     RECT  90.936 96.601 94.878 96.691 ;
     RECT  39.852 95.945 41.598 96.859 ;
     RECT  42.444 96.475 75.834 96.859 ;
     RECT  76.968 96.379 78.297 96.989 ;
     RECT  96.3 96.653 97.578 97.061 ;
     RECT  86.115 96.529 86.67 97.069 ;
     RECT  90.936 96.691 95.274 97.169 ;
     RECT  90.936 97.169 91.854 97.231 ;
     RECT  86.115 97.069 86.742 97.331 ;
     RECT  92.628 97.169 95.274 97.339 ;
     RECT  96.912 97.061 97.578 98.093 ;
     RECT  77.22 96.989 78.297 98.149 ;
     RECT  39.852 96.859 75.834 98.347 ;
     RECT  76.644 98.149 78.297 98.347 ;
     RECT  90.504 97.231 91.854 98.347 ;
     RECT  92.628 97.339 95.778 98.347 ;
     RECT  88.815 96.449 89.766 98.383 ;
     RECT  90.504 98.347 95.778 98.383 ;
     RECT  86.115 97.331 86.67 98.519 ;
     RECT  88.815 98.383 95.778 98.581 ;
     RECT  96.912 98.093 97.506 98.581 ;
     RECT  88.815 98.581 97.506 98.609 ;
     RECT  93.348 98.609 97.506 98.987 ;
     RECT  93.348 98.987 96.318 99.185 ;
     RECT  88.815 98.609 92.286 99.463 ;
     RECT  93.348 99.185 95.922 99.463 ;
     RECT  97.488 98.987 97.506 99.499 ;
     RECT  83.415 90.653 83.697 99.571 ;
     RECT  83.415 99.571 84.258 99.689 ;
     RECT  86.115 98.519 86.397 99.733 ;
     RECT  88.815 99.463 95.922 99.797 ;
     RECT  86.115 99.733 86.67 99.869 ;
     RECT  22.464 99.835 22.482 99.959 ;
     RECT  87.732 99.841 87.75 99.959 ;
     RECT  88.815 99.797 89.19 99.959 ;
     RECT  21.315 2.413 21.597 99.967 ;
     RECT  21.315 99.967 22.158 100.013 ;
     RECT  97.488 99.499 97.542 100.067 ;
     RECT  89.964 99.797 95.922 100.111 ;
     RECT  37.515 95.789 38.286 100.267 ;
     RECT  37.515 100.267 38.862 100.307 ;
     RECT  39.852 98.347 78.297 100.381 ;
     RECT  89.964 100.111 96.354 100.397 ;
     RECT  39.168 100.381 78.297 100.541 ;
     RECT  87.624 99.967 87.642 100.651 ;
     RECT  87.516 100.651 87.642 100.805 ;
     RECT  80.64 94.405 80.997 100.841 ;
     RECT  89.964 100.397 96.318 100.841 ;
     RECT  88.02 100.849 88.038 101.039 ;
     RECT  97.524 100.067 97.542 101.111 ;
     RECT  89.964 100.841 95.742 101.309 ;
     RECT  89.964 101.309 95.454 101.759 ;
     RECT  39.852 100.541 78.297 102.119 ;
     RECT  42.444 102.119 78.297 103.469 ;
     RECT  42.444 103.469 77.238 103.704 ;
     RECT  93.6 101.759 95.454 103.805 ;
     RECT  89.964 101.759 92.43 103.847 ;
     RECT  75.24 103.704 77.238 104.117 ;
     RECT  76.068 104.117 77.238 104.153 ;
     RECT  39.852 102.119 41.454 104.387 ;
     RECT  93.6 103.805 94.497 104.387 ;
     RECT  42.444 103.704 43.146 104.423 ;
     RECT  39.852 104.387 41.31 104.459 ;
     RECT  89.964 103.847 92.286 104.459 ;
     RECT  89.964 104.459 90.414 104.549 ;
     RECT  76.104 104.153 77.238 104.585 ;
     RECT  76.14 104.585 77.238 104.621 ;
     RECT  91.515 104.459 92.286 105.161 ;
     RECT  48.276 105.133 48.294 105.169 ;
     RECT  90.396 104.549 90.414 105.197 ;
     RECT  76.14 104.621 76.662 105.233 ;
     RECT  50.292 105.205 50.31 105.241 ;
     RECT  42.624 104.423 43.146 105.467 ;
     RECT  50.184 105.241 50.31 105.637 ;
     RECT  48.096 105.169 48.294 105.745 ;
     RECT  95.436 103.805 95.454 105.773 ;
     RECT  49.788 105.637 50.31 105.781 ;
     RECT  42.66 105.467 43.146 105.809 ;
     RECT  76.14 105.233 76.158 105.809 ;
     RECT  49.716 105.781 50.31 105.823 ;
     RECT  75.24 104.117 75.294 105.823 ;
     RECT  64.515 105.823 64.605 105.871 ;
     RECT  42.732 105.809 43.146 105.899 ;
     RECT  46.764 105.637 46.782 105.899 ;
     RECT  48.024 105.745 48.798 105.899 ;
     RECT  49.716 105.823 51.105 105.899 ;
     RECT  64.515 105.871 65.25 105.917 ;
     RECT  48.276 105.899 48.597 105.971 ;
     RECT  50.184 105.899 50.202 105.971 ;
     RECT  42.915 105.899 43.146 106.093 ;
     RECT  45.615 105.823 45.705 106.093 ;
     RECT  51.015 105.899 51.105 106.093 ;
     RECT  53.715 105.823 53.805 106.093 ;
     RECT  56.415 105.823 56.505 106.093 ;
     RECT  59.115 105.823 59.205 106.093 ;
     RECT  61.815 105.823 61.905 106.093 ;
     RECT  67.215 105.823 67.305 106.093 ;
     RECT  69.915 105.823 70.005 106.093 ;
     RECT  72.615 105.823 72.705 106.093 ;
     RECT  75.24 105.823 75.405 106.093 ;
     RECT  75.24 106.093 75.597 106.169 ;
     RECT  39.852 104.459 41.274 107.365 ;
     RECT  42.915 106.093 43.197 107.401 ;
     RECT  42.915 107.401 43.578 107.467 ;
     RECT  42.228 107.467 43.578 107.519 ;
     RECT  39.816 107.365 41.274 107.599 ;
     RECT  39.816 107.599 41.922 107.645 ;
     RECT  42.915 107.519 43.578 108.239 ;
     RECT  42.915 108.239 43.542 108.283 ;
     RECT  42.66 108.283 43.542 108.515 ;
     RECT  64.515 105.917 64.797 110.461 ;
     RECT  64.515 110.461 64.926 110.525 ;
     RECT  39.816 107.645 41.274 113.995 ;
     RECT  39.816 113.995 41.778 114.539 ;
     RECT  39.816 114.539 41.454 114.575 ;
     RECT  39.816 114.575 41.274 118.315 ;
     RECT  42.66 108.515 43.197 118.315 ;
     RECT  39.816 118.315 43.197 118.355 ;
     RECT  24.015 2.413 24.297 118.651 ;
     RECT  26.715 2.413 26.997 118.831 ;
     RECT  24.015 118.651 24.822 118.859 ;
     RECT  26.676 118.831 26.997 118.925 ;
     RECT  30.78 118.843 30.798 118.973 ;
     RECT  10.515 88.115 10.797 118.987 ;
     RECT  21.315 100.013 21.597 118.987 ;
     RECT  14.724 118.987 14.85 119.117 ;
     RECT  21.315 118.987 21.69 119.117 ;
     RECT  10.515 118.987 10.854 119.129 ;
     RECT  25.128 118.891 25.146 119.129 ;
     RECT  42.66 118.355 43.197 119.947 ;
     RECT  35.928 120.991 35.946 121.135 ;
     RECT  42.66 119.947 43.254 121.289 ;
     RECT  35.928 121.135 35.982 121.369 ;
     RECT  35.928 121.369 36.162 121.441 ;
     RECT  34.815 89.843 35.097 121.675 ;
     RECT  35.928 121.441 36.486 121.675 ;
     RECT  42.66 121.289 43.197 121.711 ;
     RECT  39.816 118.355 41.274 121.819 ;
     RECT  39.816 121.819 41.418 121.865 ;
     RECT  37.515 100.307 38.286 121.945 ;
     RECT  37.332 121.945 38.286 122.179 ;
     RECT  42.588 121.711 43.197 122.179 ;
     RECT  34.815 121.675 36.486 122.215 ;
     RECT  37.332 122.179 38.826 122.215 ;
     RECT  34.815 122.215 38.826 122.449 ;
     RECT  7.815 89.339 8.097 122.485 ;
     RECT  34.776 122.449 38.826 122.513 ;
     RECT  42.516 122.179 43.197 122.521 ;
     RECT  34.776 122.513 38.718 122.549 ;
     RECT  39.816 121.865 41.166 122.611 ;
     RECT  2.415 89.573 2.697 122.755 ;
     RECT  3.42 122.521 3.438 122.755 ;
     RECT  39.816 122.611 41.49 122.755 ;
     RECT  42.444 122.521 43.197 122.755 ;
     RECT  2.415 122.755 3.438 122.779 ;
     RECT  0.108 122.683 0.126 122.819 ;
     RECT  2.415 122.779 4.014 122.971 ;
     RECT  5.115 89.429 5.397 122.971 ;
     RECT  30.852 122.917 30.87 123.017 ;
     RECT  6.768 122.989 6.786 123.089 ;
     RECT  7.815 122.485 8.622 123.151 ;
     RECT  2.415 122.971 5.397 123.211 ;
     RECT  39.816 122.755 43.197 123.223 ;
     RECT  0.144 123.115 0.162 123.259 ;
     RECT  34.776 122.549 38.646 123.331 ;
     RECT  39.78 123.223 43.197 123.331 ;
     RECT  75.315 106.169 75.597 123.331 ;
     RECT  0.144 123.259 0.234 123.359 ;
     RECT  6.624 123.331 6.75 123.421 ;
     RECT  74.844 123.331 75.597 123.485 ;
     RECT  34.776 123.331 43.197 123.521 ;
     RECT  6.588 123.421 6.75 123.565 ;
     RECT  2.415 123.211 5.526 123.643 ;
     RECT  6.552 123.565 6.75 123.643 ;
     RECT  2.415 123.643 6.75 123.691 ;
     RECT  7.815 123.151 8.694 123.763 ;
     RECT  2.304 123.691 6.75 123.835 ;
     RECT  7.815 123.763 9.342 123.961 ;
     RECT  7.815 123.961 9.414 123.989 ;
     RECT  2.304 123.835 6.858 124.061 ;
     RECT  9.324 123.989 9.414 124.061 ;
     RECT  73.908 123.295 73.926 124.105 ;
     RECT  7.815 123.989 8.586 124.141 ;
     RECT  73.908 124.105 74.07 124.141 ;
     RECT  0.108 123.835 0.126 124.169 ;
     RECT  73.908 124.141 74.142 124.169 ;
     RECT  74.052 124.169 74.142 124.259 ;
     RECT  7.632 124.141 8.586 124.331 ;
     RECT  34.776 123.521 37.797 124.339 ;
     RECT  38.628 123.521 43.197 124.339 ;
     RECT  74.88 123.485 75.597 124.375 ;
     RECT  2.304 124.061 6.786 124.405 ;
     RECT  74.88 124.375 75.834 124.411 ;
     RECT  2.268 124.405 6.786 124.445 ;
     RECT  9.36 124.061 9.378 124.529 ;
     RECT  74.124 124.259 74.142 124.681 ;
     RECT  74.88 124.411 75.906 124.681 ;
     RECT  0.144 124.603 0.162 124.733 ;
     RECT  94.215 104.387 94.497 124.771 ;
     RECT  2.415 124.445 6.786 124.951 ;
     RECT  94.032 124.771 94.497 125.131 ;
     RECT  95.76 124.807 95.778 125.131 ;
     RECT  94.032 125.131 95.778 125.177 ;
     RECT  2.415 124.951 6.894 125.179 ;
     RECT  7.668 124.331 8.586 125.179 ;
     RECT  74.124 124.681 75.978 125.221 ;
     RECT  2.415 125.179 8.586 125.275 ;
     RECT  95.76 125.177 95.778 125.309 ;
     RECT  94.032 125.177 94.734 125.323 ;
     RECT  93.924 125.323 94.734 125.339 ;
     RECT  74.124 125.221 76.05 125.347 ;
     RECT  2.304 125.275 8.586 125.405 ;
     RECT  2.304 125.405 6.858 125.411 ;
     RECT  89.82 125.371 89.838 125.411 ;
     RECT  90.72 125.347 90.738 125.419 ;
     RECT  91.515 105.161 91.797 125.419 ;
     RECT  74.088 125.347 76.05 125.455 ;
     RECT  7.815 125.405 8.586 125.491 ;
     RECT  7.815 125.491 8.766 125.581 ;
     RECT  73.908 125.455 76.05 125.609 ;
     RECT  7.815 125.581 8.874 125.717 ;
     RECT  92.88 125.383 92.898 125.725 ;
     RECT  93.924 125.339 94.662 125.725 ;
     RECT  5.115 125.411 6.858 125.753 ;
     RECT  90.72 125.419 91.797 125.761 ;
     RECT  92.88 125.725 94.662 125.761 ;
     RECT  90.72 125.761 94.662 125.851 ;
     RECT  29.415 2.413 29.697 125.995 ;
     RECT  83.415 99.689 83.697 125.995 ;
     RECT  73.98 125.609 76.05 126.031 ;
     RECT  83.415 125.995 84.33 126.031 ;
     RECT  6.696 125.753 6.858 126.059 ;
     RECT  2.304 125.411 4.302 126.139 ;
     RECT  5.115 125.753 5.958 126.139 ;
     RECT  90.216 125.851 94.662 126.139 ;
     RECT  29.088 125.995 29.697 126.149 ;
     RECT  83.415 126.031 84.474 126.149 ;
     RECT  90.216 126.139 95.166 126.149 ;
     RECT  83.415 126.149 84.33 126.185 ;
     RECT  73.98 126.031 76.338 126.229 ;
     RECT  0.108 124.987 0.126 126.235 ;
     RECT  2.304 126.139 5.958 126.257 ;
     RECT  88.815 99.959 89.097 126.265 ;
     RECT  90.288 126.149 95.166 126.265 ;
     RECT  73.98 126.229 76.662 126.301 ;
     RECT  2.304 126.257 5.886 126.317 ;
     RECT  0.108 126.235 0.162 126.329 ;
     RECT  9.396 126.265 9.414 126.419 ;
     RECT  83.415 126.185 83.826 126.419 ;
     RECT  72.615 106.093 72.897 126.421 ;
     RECT  73.98 126.301 77.274 126.421 ;
     RECT  72.615 126.421 77.274 126.427 ;
     RECT  78.015 103.469 78.297 126.427 ;
     RECT  90.288 126.265 95.238 126.491 ;
     RECT  97.488 125.845 97.506 126.491 ;
     RECT  10.515 119.129 10.797 126.523 ;
     RECT  18.615 2.413 18.897 126.523 ;
     RECT  34.776 124.339 43.197 126.523 ;
     RECT  6.804 126.059 6.858 126.535 ;
     RECT  90.612 126.491 95.238 126.557 ;
     RECT  90.684 126.557 95.238 126.563 ;
     RECT  6.804 126.535 7.074 126.571 ;
     RECT  7.815 125.717 8.622 126.571 ;
     RECT  96.3 125.419 96.318 126.571 ;
     RECT  6.804 126.571 8.982 126.689 ;
     RECT  2.415 126.317 5.886 126.701 ;
     RECT  3.42 126.701 5.886 126.749 ;
     RECT  10.515 126.523 10.854 126.749 ;
     RECT  18.615 126.523 18.954 126.749 ;
     RECT  22.788 126.523 22.806 126.749 ;
     RECT  34.74 126.523 43.197 126.749 ;
     RECT  90.684 126.563 92.214 126.833 ;
     RECT  3.744 126.749 5.886 126.959 ;
     RECT  6.804 126.689 8.694 126.959 ;
     RECT  6.804 126.959 8.478 126.967 ;
     RECT  80.715 100.841 80.997 126.967 ;
     RECT  6.768 126.967 8.478 126.995 ;
     RECT  72.615 126.427 78.297 126.995 ;
     RECT  96.3 126.571 96.93 127.031 ;
     RECT  96.912 127.031 96.93 127.067 ;
     RECT  0.144 126.329 0.162 127.085 ;
     RECT  6.768 126.995 8.298 127.103 ;
     RECT  91.116 126.833 92.214 127.103 ;
     RECT  4.032 126.959 5.886 127.111 ;
     RECT  45.615 106.093 45.897 127.187 ;
     RECT  48.315 105.971 48.597 127.187 ;
     RECT  51.015 106.093 51.297 127.187 ;
     RECT  53.715 106.093 53.997 127.187 ;
     RECT  56.415 106.093 56.697 127.187 ;
     RECT  59.115 106.093 59.397 127.187 ;
     RECT  61.815 106.093 62.097 127.187 ;
     RECT  64.515 110.525 64.797 127.187 ;
     RECT  67.215 106.093 67.497 127.187 ;
     RECT  69.915 106.093 70.197 127.187 ;
     RECT  72.615 126.995 73.638 127.187 ;
     RECT  4.032 127.111 5.994 127.229 ;
     RECT  6.768 127.103 6.786 127.229 ;
     RECT  73.476 127.187 73.638 127.229 ;
     RECT  74.664 126.995 78.297 127.229 ;
     RECT  80.715 126.967 81.054 127.229 ;
     RECT  86.115 99.869 86.397 127.237 ;
     RECT  4.032 127.229 5.814 127.265 ;
     RECT  73.476 127.229 73.494 127.265 ;
     RECT  0.108 127.147 0.126 127.277 ;
     RECT  93.024 126.563 95.238 127.277 ;
     RECT  86.115 127.237 86.67 127.373 ;
     RECT  34.776 126.749 43.197 127.381 ;
     RECT  93.456 127.277 95.238 127.381 ;
     RECT  4.032 127.265 5.706 127.421 ;
     RECT  45.615 127.187 45.705 127.457 ;
     RECT  48.315 127.187 48.405 127.457 ;
     RECT  51.015 127.187 51.105 127.457 ;
     RECT  53.715 127.187 53.805 127.457 ;
     RECT  56.415 127.187 56.505 127.457 ;
     RECT  59.115 127.187 59.205 127.457 ;
     RECT  61.815 127.187 61.905 127.457 ;
     RECT  64.515 127.187 64.605 127.457 ;
     RECT  67.215 127.187 67.305 127.457 ;
     RECT  69.915 127.187 70.005 127.457 ;
     RECT  72.615 127.187 72.705 127.457 ;
     RECT  4.896 127.421 5.706 127.499 ;
     RECT  34.776 127.381 43.362 127.499 ;
     RECT  93.456 127.381 95.778 127.499 ;
     RECT  7.776 127.103 8.298 127.565 ;
     RECT  4.896 127.499 5.397 127.571 ;
     RECT  34.776 127.499 43.074 127.607 ;
     RECT  4.032 127.421 4.05 127.679 ;
     RECT  7.815 127.565 8.298 127.679 ;
     RECT  93.456 127.499 94.554 128.183 ;
     RECT  93.456 128.183 94.497 128.345 ;
     RECT  86.115 127.373 86.397 128.857 ;
     RECT  88.815 126.265 89.19 128.885 ;
     RECT  86.115 128.857 86.634 128.993 ;
     RECT  91.188 127.103 92.214 129.001 ;
     RECT  74.844 127.229 78.297 129.155 ;
     RECT  90.972 129.001 92.214 129.199 ;
     RECT  90.972 129.199 92.43 129.235 ;
     RECT  90.972 129.235 92.538 129.271 ;
     RECT  34.815 127.607 43.074 129.451 ;
     RECT  34.815 129.451 43.11 129.6 ;
     RECT  74.844 129.155 75.942 129.6 ;
     RECT  95.76 127.499 95.778 129.731 ;
     RECT  2.415 126.701 2.697 129.811 ;
     RECT  5.115 127.571 5.397 129.811 ;
     RECT  34.815 129.6 75.942 129.811 ;
     RECT  2.268 129.811 3.006 129.929 ;
     RECT  30.78 129.811 30.798 129.929 ;
     RECT  34.668 129.811 75.942 129.965 ;
     RECT  2.268 129.929 2.697 130.061 ;
     RECT  7.815 127.679 8.097 130.081 ;
     RECT  4.572 129.811 5.397 130.315 ;
     RECT  7.056 130.045 7.074 130.315 ;
     RECT  4.572 130.315 5.634 130.351 ;
     RECT  76.968 129.155 78.297 130.459 ;
     RECT  80.715 127.229 80.997 130.507 ;
     RECT  3.42 130.267 3.438 130.513 ;
     RECT  90.972 129.271 92.574 130.621 ;
     RECT  93.492 128.345 94.497 130.621 ;
     RECT  34.776 129.965 75.942 130.651 ;
     RECT  76.968 130.459 78.678 130.651 ;
     RECT  6.912 130.315 7.074 130.711 ;
     RECT  7.815 130.081 8.298 130.711 ;
     RECT  83.415 126.419 83.697 130.747 ;
     RECT  86.115 128.993 86.397 130.747 ;
     RECT  0.144 130.171 0.162 130.781 ;
     RECT  90.972 130.621 94.497 130.819 ;
     RECT  90.54 130.819 94.497 130.847 ;
     RECT  4.464 130.351 5.706 130.855 ;
     RECT  34.776 130.651 78.678 130.855 ;
     RECT  86.115 130.747 86.67 130.891 ;
     RECT  2.304 130.061 2.697 130.981 ;
     RECT  3.42 130.513 3.546 130.981 ;
     RECT  6.912 130.711 8.298 130.981 ;
     RECT  82.98 130.747 83.697 130.981 ;
     RECT  9.144 130.891 9.162 131.009 ;
     RECT  90.54 130.847 90.666 131.009 ;
     RECT  82.98 130.981 84.366 131.017 ;
     RECT  2.304 130.981 3.618 131.053 ;
     RECT  34.704 130.855 78.678 131.069 ;
     RECT  2.268 131.053 3.618 131.081 ;
     RECT  4.464 130.855 5.958 131.125 ;
     RECT  6.912 130.981 8.37 131.125 ;
     RECT  82.98 131.017 84.69 131.153 ;
     RECT  2.268 131.081 2.79 131.213 ;
     RECT  91.515 130.847 94.497 131.279 ;
     RECT  85.788 130.891 86.67 131.287 ;
     RECT  91.515 131.279 93.186 131.315 ;
     RECT  3.852 131.125 8.37 131.357 ;
     RECT  85.788 131.287 86.706 131.423 ;
     RECT  82.98 131.153 84.618 131.431 ;
     RECT  2.415 131.213 2.79 131.459 ;
     RECT  95.472 129.811 95.49 131.549 ;
     RECT  82.908 131.431 84.618 131.585 ;
     RECT  90.648 131.009 90.666 131.585 ;
     RECT  82.98 131.585 84.618 131.621 ;
     RECT  85.788 131.423 86.67 131.629 ;
     RECT  3.996 131.357 8.37 131.657 ;
     RECT  82.044 131.629 82.062 131.693 ;
     RECT  94.215 131.279 94.497 131.701 ;
     RECT  3.996 131.657 5.814 131.729 ;
     RECT  80.64 130.507 80.997 131.791 ;
     RECT  83.415 131.621 84.618 131.981 ;
     RECT  0.108 131.755 0.126 131.999 ;
     RECT  3.996 131.729 5.397 132.089 ;
     RECT  6.732 131.657 8.37 132.089 ;
     RECT  7.815 132.089 8.37 132.091 ;
     RECT  4.5 132.089 5.397 132.125 ;
     RECT  80.64 131.791 81.486 132.125 ;
     RECT  94.215 131.701 95.058 132.125 ;
     RECT  83.415 131.981 84.402 132.221 ;
     RECT  7.815 132.091 8.406 132.241 ;
     RECT  34.815 131.069 78.678 132.403 ;
     RECT  91.515 131.315 92.574 132.427 ;
     RECT  85.752 131.629 86.67 132.439 ;
     RECT  13.215 76.379 13.497 132.511 ;
     RECT  7.815 132.241 8.586 132.539 ;
     RECT  85.752 132.439 86.706 132.539 ;
     RECT  34.776 132.403 78.678 132.737 ;
     RECT  76.932 132.737 78.678 132.745 ;
     RECT  91.116 132.427 92.574 132.797 ;
     RECT  76.932 132.745 78.93 132.893 ;
     RECT  34.776 132.737 76.086 133.015 ;
     RECT  76.968 132.893 78.93 133.169 ;
     RECT  34.74 133.015 76.086 133.555 ;
     RECT  4.68 132.125 5.397 133.619 ;
     RECT  34.416 133.555 76.086 133.853 ;
     RECT  76.968 133.169 78.75 133.979 ;
     RECT  12.564 132.511 13.497 134.159 ;
     RECT  34.776 133.853 76.086 134.249 ;
     RECT  91.515 132.797 92.574 134.293 ;
     RECT  6.732 132.089 6.75 134.357 ;
     RECT  77.112 133.979 78.75 134.393 ;
     RECT  30.78 134.329 30.798 134.429 ;
     RECT  34.815 134.249 76.086 134.621 ;
     RECT  42.264 134.621 76.086 134.717 ;
     RECT  42.264 134.717 42.354 134.813 ;
     RECT  77.112 134.393 78.354 134.813 ;
     RECT  77.256 134.813 78.354 134.825 ;
     RECT  42.3 134.813 42.354 134.909 ;
     RECT  43.092 134.717 76.086 135.005 ;
     RECT  42.336 134.909 42.354 135.101 ;
     RECT  34.815 134.621 41.31 135.211 ;
     RECT  34.776 135.211 41.31 135.643 ;
     RECT  43.2 135.005 76.086 135.931 ;
     RECT  43.2 135.931 76.41 136.021 ;
     RECT  80.64 132.125 80.997 136.409 ;
     RECT  42.732 136.021 76.41 136.561 ;
     RECT  34.704 135.643 41.31 136.687 ;
     RECT  34.596 136.687 41.31 136.751 ;
     RECT  34.596 136.751 40.914 136.781 ;
     RECT  42.192 136.561 76.41 136.829 ;
     RECT  34.815 136.781 40.914 136.949 ;
     RECT  77.256 134.825 78.297 137.021 ;
     RECT  88.815 128.885 89.097 137.065 ;
     RECT  94.215 132.125 94.497 137.065 ;
     RECT  77.544 137.021 78.297 137.117 ;
     RECT  82.656 137.065 82.674 137.219 ;
     RECT  88.815 137.065 89.838 137.219 ;
     RECT  42.192 136.829 75.192 137.641 ;
     RECT  85.752 132.539 86.397 137.669 ;
     RECT  34.815 136.949 40.878 137.911 ;
     RECT  41.616 137.641 75.192 137.911 ;
     RECT  77.58 137.117 78.297 138.136 ;
     RECT  91.515 134.293 93.042 138.541 ;
     RECT  94.14 137.065 94.497 138.721 ;
     RECT  97.488 138.379 97.506 138.919 ;
     RECT  76.068 136.829 76.41 138.941 ;
     RECT  96.912 138.919 97.506 138.989 ;
     RECT  91.188 138.541 93.042 138.991 ;
     RECT  88.815 137.219 89.766 139.081 ;
     RECT  77.544 138.136 78.297 139.099 ;
     RECT  88.815 139.081 90.306 139.133 ;
     RECT  97.488 138.989 97.506 139.133 ;
     RECT  77.4 139.099 78.297 139.153 ;
     RECT  94.068 138.721 94.497 139.189 ;
     RECT  86.115 137.669 86.397 139.225 ;
     RECT  91.044 138.991 93.042 139.225 ;
     RECT  94.068 139.189 94.554 139.225 ;
     RECT  34.815 137.911 75.192 139.291 ;
     RECT  76.068 138.941 76.086 139.291 ;
     RECT  91.044 139.225 94.554 139.351 ;
     RECT  77.22 139.153 78.297 139.387 ;
     RECT  95.76 139.243 95.778 139.387 ;
     RECT  90.648 139.351 94.662 139.459 ;
     RECT  95.76 139.387 96.354 139.459 ;
     RECT  34.815 139.291 76.086 139.487 ;
     RECT  98.244 139.483 98.262 139.495 ;
     RECT  98.172 139.495 98.262 139.523 ;
     RECT  98.172 139.523 98.19 139.565 ;
     RECT  34.815 139.487 35.262 139.649 ;
     RECT  36 139.487 76.086 139.649 ;
     RECT  36.036 139.649 76.086 139.771 ;
     RECT  76.968 139.387 78.297 139.771 ;
     RECT  88.815 139.133 89.766 140.071 ;
     RECT  90.648 139.459 96.354 140.071 ;
     RECT  97.488 140.107 97.506 140.189 ;
     RECT  86.115 139.225 86.67 140.341 ;
     RECT  86.115 140.341 86.742 140.54 ;
     RECT  36.036 139.771 78.297 140.587 ;
     RECT  88.815 140.071 96.354 140.611 ;
     RECT  35.892 140.587 78.297 140.621 ;
     RECT  86.115 140.54 86.706 140.639 ;
     RECT  88.815 140.611 96.93 140.729 ;
     RECT  35.892 140.621 36.774 141.035 ;
     RECT  90.648 140.729 96.93 141.071 ;
     RECT  90.648 141.071 96.354 141.149 ;
     RECT  35.892 141.035 36.594 141.179 ;
     RECT  34.815 139.649 35.097 141.355 ;
     RECT  35.892 141.179 36.486 141.355 ;
     RECT  95.76 141.149 96.354 141.437 ;
     RECT  34.815 141.355 36.486 141.539 ;
     RECT  88.815 140.729 89.766 141.583 ;
     RECT  90.648 141.149 95.022 141.583 ;
     RECT  95.76 141.437 95.922 141.809 ;
     RECT  95.76 141.809 95.778 141.881 ;
     RECT  35.892 141.539 36.486 141.917 ;
     RECT  97.488 141.259 97.506 141.961 ;
     RECT  96.912 141.961 97.506 142.013 ;
     RECT  86.115 140.639 86.397 142.051 ;
     RECT  88.815 141.583 95.022 142.123 ;
     RECT  84.636 136.525 84.654 142.259 ;
     RECT  86.115 142.051 86.742 142.259 ;
     RECT  88.815 142.123 95.238 142.691 ;
     RECT  96.3 142.699 96.318 142.736 ;
     RECT  90.324 142.691 95.238 142.843 ;
     RECT  88.815 142.691 89.514 142.889 ;
     RECT  90.324 142.843 95.922 142.889 ;
     RECT  86.115 142.259 86.67 143.033 ;
     RECT  97.452 142.013 97.506 143.131 ;
     RECT  96.912 143.131 97.506 143.339 ;
     RECT  90.324 142.889 95.814 143.429 ;
     RECT  91.224 143.429 95.814 143.465 ;
     RECT  97.488 143.339 97.506 143.537 ;
     RECT  37.515 140.621 78.297 143.699 ;
     RECT  91.224 143.465 95.706 144.041 ;
     RECT  42.444 143.699 78.297 144.509 ;
     RECT  77.22 144.509 78.297 146.435 ;
     RECT  42.444 144.509 76.194 146.904 ;
     RECT  91.224 144.041 95.022 147.083 ;
     RECT  94.176 147.083 95.022 147.101 ;
     RECT  37.515 143.699 41.598 147.119 ;
     RECT  70.704 146.904 70.722 147.197 ;
     RECT  91.224 147.083 93.402 147.209 ;
     RECT  42.444 146.904 43.146 147.245 ;
     RECT  91.224 147.209 93.186 147.245 ;
     RECT  75.168 146.904 76.194 147.281 ;
     RECT  37.515 147.119 41.562 147.353 ;
     RECT  75.168 147.281 76.122 147.479 ;
     RECT  75.168 147.479 76.086 147.515 ;
     RECT  94.176 147.101 94.497 147.659 ;
     RECT  91.224 147.245 92.322 147.749 ;
     RECT  42.48 147.245 43.146 147.785 ;
     RECT  93.168 147.245 93.186 147.785 ;
     RECT  38.52 147.353 41.562 147.821 ;
     RECT  91.224 147.749 92.178 147.821 ;
     RECT  38.52 147.821 41.526 147.893 ;
     RECT  91.224 147.821 91.998 147.893 ;
     RECT  38.52 147.893 41.346 147.929 ;
     RECT  77.22 146.435 77.274 147.929 ;
     RECT  41.328 147.929 41.346 148.289 ;
     RECT  91.515 147.893 91.998 148.289 ;
     RECT  77.256 147.929 77.274 148.469 ;
     RECT  42.696 147.785 43.146 148.514 ;
     RECT  42.732 148.514 43.146 148.559 ;
     RECT  50.004 148.531 50.022 148.945 ;
     RECT  50.76 148.486 50.778 148.945 ;
     RECT  90.324 143.429 90.342 148.973 ;
     RECT  48.672 148.441 48.69 148.981 ;
     RECT  76.068 147.515 76.086 149.009 ;
     RECT  48.672 148.981 48.798 149.023 ;
     RECT  50.004 148.945 50.778 149.023 ;
     RECT  75.168 147.515 75.258 149.023 ;
     RECT  48.315 149.023 48.798 149.099 ;
     RECT  50.004 149.023 51.105 149.099 ;
     RECT  75.168 149.023 75.597 149.135 ;
     RECT  50.724 149.099 51.105 149.279 ;
     RECT  42.915 148.559 43.146 149.293 ;
     RECT  45.615 149.023 45.705 149.293 ;
     RECT  51.015 149.279 51.105 149.293 ;
     RECT  53.715 149.023 53.805 149.293 ;
     RECT  56.415 149.023 56.505 149.293 ;
     RECT  59.115 149.023 59.205 149.293 ;
     RECT  61.815 149.023 61.905 149.293 ;
     RECT  64.515 149.023 64.605 149.293 ;
     RECT  67.215 149.023 67.305 149.293 ;
     RECT  69.915 149.023 70.005 149.293 ;
     RECT  72.615 149.023 72.705 149.293 ;
     RECT  75.24 149.135 75.597 149.369 ;
     RECT  37.515 147.353 37.797 156.703 ;
     RECT  38.52 147.929 40.497 156.703 ;
     RECT  37.515 156.703 40.497 156.731 ;
     RECT  37.515 156.731 38.574 161.905 ;
     RECT  39.456 156.731 40.497 161.905 ;
     RECT  37.515 161.905 40.497 165.883 ;
     RECT  37.116 165.883 40.497 166.451 ;
     RECT  37.296 166.451 40.497 166.649 ;
     RECT  37.515 166.649 40.497 167.729 ;
     RECT  37.515 167.729 39.042 167.873 ;
     RECT  2.415 131.459 2.697 168.227 ;
     RECT  5.115 133.619 5.397 168.227 ;
     RECT  7.815 132.539 8.097 168.227 ;
     RECT  10.515 126.749 10.797 168.227 ;
     RECT  13.215 134.159 13.497 168.227 ;
     RECT  15.915 2.413 16.197 168.227 ;
     RECT  18.615 126.749 18.897 168.227 ;
     RECT  21.315 119.117 21.597 168.227 ;
     RECT  24.015 118.859 24.297 168.227 ;
     RECT  26.715 118.925 26.997 168.227 ;
     RECT  29.415 126.149 29.697 168.227 ;
     RECT  32.115 2.413 32.397 168.227 ;
     RECT  34.815 141.539 35.097 168.227 ;
     RECT  40.215 167.729 40.497 168.227 ;
     RECT  42.915 149.293 43.197 168.227 ;
     RECT  45.615 149.293 45.897 168.227 ;
     RECT  48.315 149.099 48.597 168.227 ;
     RECT  51.015 149.293 51.297 168.227 ;
     RECT  53.715 149.293 53.997 168.227 ;
     RECT  56.415 149.293 56.697 168.227 ;
     RECT  59.115 149.293 59.397 168.227 ;
     RECT  61.815 149.293 62.097 168.227 ;
     RECT  64.515 149.293 64.797 168.227 ;
     RECT  67.215 149.293 67.497 168.227 ;
     RECT  69.915 149.293 70.197 168.227 ;
     RECT  72.615 149.293 72.897 168.227 ;
     RECT  75.315 149.369 75.597 168.227 ;
     RECT  78.015 146.435 78.297 168.227 ;
     RECT  80.715 136.409 80.997 168.227 ;
     RECT  83.415 132.221 83.697 168.227 ;
     RECT  86.115 143.033 86.397 168.227 ;
     RECT  88.815 142.889 89.097 168.227 ;
     RECT  91.515 148.289 91.797 168.227 ;
     RECT  94.215 147.659 94.497 168.227 ;
     RECT  2.415 168.227 2.505 168.497 ;
     RECT  5.115 168.227 5.205 168.497 ;
     RECT  7.815 168.227 7.905 168.497 ;
     RECT  10.515 168.227 10.605 168.497 ;
     RECT  13.215 168.227 13.305 168.497 ;
     RECT  15.915 168.227 16.005 168.497 ;
     RECT  18.615 168.227 18.705 168.497 ;
     RECT  21.315 168.227 21.405 168.497 ;
     RECT  24.015 168.227 24.105 168.497 ;
     RECT  26.715 168.227 26.805 168.497 ;
     RECT  29.415 168.227 29.505 168.497 ;
     RECT  32.115 168.227 32.205 168.497 ;
     RECT  34.815 168.227 34.905 168.497 ;
     RECT  37.515 167.873 39.006 168.497 ;
     RECT  40.215 168.227 40.305 168.497 ;
     RECT  42.915 168.227 43.005 168.497 ;
     RECT  45.615 168.227 45.705 168.497 ;
     RECT  48.315 168.227 48.405 168.497 ;
     RECT  51.015 168.227 51.105 168.497 ;
     RECT  53.715 168.227 53.805 168.497 ;
     RECT  56.415 168.227 56.505 168.497 ;
     RECT  59.115 168.227 59.205 168.497 ;
     RECT  61.815 168.227 61.905 168.497 ;
     RECT  64.515 168.227 64.605 168.497 ;
     RECT  67.215 168.227 67.305 168.497 ;
     RECT  69.915 168.227 70.005 168.497 ;
     RECT  72.615 168.227 72.705 168.497 ;
     RECT  75.315 168.227 75.405 168.497 ;
     RECT  78.015 168.227 78.105 168.497 ;
     RECT  80.715 168.227 80.805 168.497 ;
     RECT  83.415 168.227 83.505 168.497 ;
     RECT  86.115 168.227 86.205 168.497 ;
     RECT  88.815 168.227 88.905 168.497 ;
     RECT  91.515 168.227 91.605 168.497 ;
     RECT  94.215 168.227 94.305 168.497 ;
     RECT  38.052 168.497 39.006 170.347 ;
     RECT  37.836 170.347 39.006 170.609 ;
     RECT  37.908 170.609 39.006 170.621 ;
    LAYER M4 ;
     RECT  0.06 84.672 0.097 89.16 ;
     RECT  0.06 122.688 0.097 127.176 ;
     RECT  0.06 31.68 0.137 36.168 ;
     RECT  0.06 40.896 0.137 45.384 ;
     RECT  0.06 78.912 0.137 83.4 ;
     RECT  0.097 84.672 0.137 89.256 ;
     RECT  0.097 122.688 0.137 127.272 ;
     RECT  0.06 130.032 0.137 131.784 ;
     RECT  0.137 41.04 0.173 45.384 ;
     RECT  0.137 79.056 0.173 83.4 ;
     RECT  0.137 84.816 0.173 89.256 ;
     RECT  0.137 31.824 2.252 36.168 ;
     RECT  2.252 31.824 2.293 36.264 ;
     RECT  2.293 31.728 2.408 36.264 ;
     RECT  0.173 41.136 2.408 45.384 ;
     RECT  0.173 79.2 2.408 83.304 ;
     RECT  0.173 84.912 2.408 89.256 ;
     RECT  0.137 122.832 2.408 127.272 ;
     RECT  0.137 130.032 2.408 131.64 ;
     RECT  2.408 2.148 2.512 168.492 ;
     RECT  2.512 2.418 2.704 168.222 ;
     RECT  2.704 31.728 3.305 36.12 ;
     RECT  2.704 130.272 3.449 131.64 ;
     RECT  2.704 78.624 3.923 83.304 ;
     RECT  2.704 84.816 4.025 89.256 ;
     RECT  2.704 122.784 4.025 127.272 ;
     RECT  2.704 40.224 4.129 45.432 ;
     RECT  3.923 79.2 4.345 83.304 ;
     RECT  3.449 130.32 4.489 131.64 ;
     RECT  4.129 40.032 4.501 45.432 ;
     RECT  4.025 84.96 4.7 89.256 ;
     RECT  4.025 122.976 4.7 127.272 ;
     RECT  4.489 130.32 4.741 131.688 ;
     RECT  3.305 31.968 5.108 36.12 ;
     RECT  4.501 40.032 5.108 45.816 ;
     RECT  4.345 79.2 5.108 83.784 ;
     RECT  4.7 84.96 5.108 89.4 ;
     RECT  4.7 122.976 5.108 127.416 ;
     RECT  4.741 129.984 5.108 131.688 ;
     RECT  5.108 2.148 5.212 168.492 ;
     RECT  5.212 2.418 5.404 168.222 ;
     RECT  5.404 123.216 5.429 127.128 ;
     RECT  5.404 84.768 5.465 87.912 ;
     RECT  5.429 125.184 5.465 127.128 ;
     RECT  5.429 123.216 5.537 123.672 ;
     RECT  5.404 39.552 5.645 45.816 ;
     RECT  5.465 84.768 5.645 85.272 ;
     RECT  5.465 86.256 5.645 87.912 ;
     RECT  5.404 130.32 5.645 131.304 ;
     RECT  5.404 32.784 5.681 33.288 ;
     RECT  5.645 42.672 5.717 45.816 ;
     RECT  5.645 130.464 5.717 131.304 ;
     RECT  5.465 126.48 5.747 127.128 ;
     RECT  5.404 79.824 5.825 83.304 ;
     RECT  5.747 126.768 5.825 127.128 ;
     RECT  5.717 131.04 5.861 131.304 ;
     RECT  5.645 87.264 5.987 87.912 ;
     RECT  5.404 34.656 6.035 35.64 ;
     RECT  5.404 36.672 6.035 36.696 ;
     RECT  5.645 39.552 6.035 41.64 ;
     RECT  6.035 40.848 6.131 41.64 ;
     RECT  6.131 41.376 6.172 41.64 ;
     RECT  5.404 38.112 6.185 38.136 ;
     RECT  5.987 87.792 6.185 87.912 ;
     RECT  6.035 34.656 6.221 34.68 ;
     RECT  6.185 87.84 6.397 87.912 ;
     RECT  5.825 79.824 6.437 82.056 ;
     RECT  6.397 87.84 6.437 88.152 ;
     RECT  6.172 41.616 6.581 41.64 ;
     RECT  5.717 42.672 6.581 43.032 ;
     RECT  5.537 123.648 6.581 123.672 ;
     RECT  6.437 88.128 6.613 88.152 ;
     RECT  5.465 125.184 6.649 125.208 ;
     RECT  5.645 85.104 6.653 85.272 ;
     RECT  6.613 88.128 6.709 88.296 ;
     RECT  6.469 89.52 6.709 89.544 ;
     RECT  6.709 88.128 6.755 89.544 ;
     RECT  5.825 126.768 6.765 126.84 ;
     RECT  6.581 42.672 6.793 42.984 ;
     RECT  6.755 88.128 6.796 88.776 ;
     RECT  5.717 44.16 6.805 45.816 ;
     RECT  6.437 79.824 6.833 82.008 ;
     RECT  6.833 79.824 7.045 79.848 ;
     RECT  6.793 42.624 7.585 42.984 ;
     RECT  6.805 44.064 7.585 45.816 ;
     RECT  6.765 126.528 7.669 126.84 ;
     RECT  5.681 33.264 7.808 33.288 ;
     RECT  6.035 39.552 7.808 39.576 ;
     RECT  7.585 42.624 7.808 45.816 ;
     RECT  5.404 76.176 7.808 76.296 ;
     RECT  7.045 79.2 7.808 79.848 ;
     RECT  6.833 81.12 7.808 82.008 ;
     RECT  5.825 83.28 7.808 83.304 ;
     RECT  6.653 85.104 7.808 85.128 ;
     RECT  5.645 86.256 7.808 86.28 ;
     RECT  6.796 88.272 7.808 88.776 ;
     RECT  7.333 118.992 7.808 119.016 ;
     RECT  6.649 125.184 7.808 125.4 ;
     RECT  7.669 126.528 7.808 127.56 ;
     RECT  6.901 130.32 7.808 130.344 ;
     RECT  6.577 131.568 7.808 131.592 ;
     RECT  7.808 2.148 7.912 168.492 ;
     RECT  7.912 2.418 8.104 168.222 ;
     RECT  8.104 81.12 8.129 81.144 ;
     RECT  8.104 79.488 8.201 79.512 ;
     RECT  8.104 43.296 8.237 44.184 ;
     RECT  8.104 130.32 8.237 132.12 ;
     RECT  8.104 45.552 8.243 45.912 ;
     RECT  8.237 131.04 8.243 132.12 ;
     RECT  8.104 36.432 8.281 36.456 ;
     RECT  8.104 41.616 8.281 41.64 ;
     RECT  8.104 85.056 8.309 85.128 ;
     RECT  8.104 86.256 8.309 87 ;
     RECT  8.237 43.296 8.381 43.32 ;
     RECT  8.104 125.184 8.417 125.208 ;
     RECT  8.243 132.096 8.417 132.12 ;
     RECT  8.309 86.976 8.525 87 ;
     RECT  8.104 83.76 8.531 83.784 ;
     RECT  8.309 85.056 8.633 85.08 ;
     RECT  8.104 123.168 8.705 123.192 ;
     RECT  8.104 39.504 10.508 39.576 ;
     RECT  8.243 45.792 10.508 45.816 ;
     RECT  8.104 47.088 10.508 47.112 ;
     RECT  8.104 76.272 10.508 76.296 ;
     RECT  8.104 118.992 10.508 119.016 ;
     RECT  8.104 126.72 10.508 126.744 ;
     RECT  10.508 2.148 10.612 168.492 ;
     RECT  10.612 2.418 10.804 168.222 ;
     RECT  10.804 76.176 10.865 76.344 ;
     RECT  10.804 126.528 10.865 126.744 ;
     RECT  10.804 39.456 12.089 39.528 ;
     RECT  12.089 39.456 12.161 39.48 ;
     RECT  10.804 45.792 13.208 45.816 ;
     RECT  10.804 47.088 13.208 47.112 ;
     RECT  10.865 76.32 13.208 76.344 ;
     RECT  10.804 118.992 13.208 119.016 ;
     RECT  10.865 126.72 13.208 126.744 ;
     RECT  13.208 2.148 13.312 168.492 ;
     RECT  13.312 2.418 13.504 168.222 ;
     RECT  13.504 76.224 13.925 76.344 ;
     RECT  13.504 118.992 14.713 119.016 ;
     RECT  14.713 118.992 14.861 119.112 ;
     RECT  13.504 45.792 15.908 45.816 ;
     RECT  13.504 47.088 15.908 47.112 ;
     RECT  13.925 76.224 15.908 76.248 ;
     RECT  14.861 118.992 15.908 119.016 ;
     RECT  13.504 126.72 15.908 126.744 ;
     RECT  15.908 2.148 16.012 168.492 ;
     RECT  16.012 2.418 16.204 168.222 ;
     RECT  16.204 45.792 18.608 45.816 ;
     RECT  16.204 47.088 18.608 47.112 ;
     RECT  16.204 76.224 18.608 76.248 ;
     RECT  16.204 118.992 18.608 119.016 ;
     RECT  16.204 126.72 18.608 126.744 ;
     RECT  18.608 2.148 18.712 168.492 ;
     RECT  18.712 2.418 18.904 168.222 ;
     RECT  18.904 126.528 18.965 126.744 ;
     RECT  18.904 45.792 21.308 45.816 ;
     RECT  18.904 47.088 21.308 47.112 ;
     RECT  18.904 76.224 21.308 76.248 ;
     RECT  18.904 118.992 21.308 119.016 ;
     RECT  18.965 126.72 21.308 126.744 ;
     RECT  21.308 2.148 21.412 168.492 ;
     RECT  21.412 2.418 21.604 168.222 ;
     RECT  21.604 94.416 22.355 94.44 ;
     RECT  21.604 99.84 22.493 100.008 ;
     RECT  21.604 118.992 22.645 119.112 ;
     RECT  21.604 76.224 22.691 76.248 ;
     RECT  22.604 94.272 22.691 94.296 ;
     RECT  21.604 126.72 22.751 126.744 ;
     RECT  22.751 126.528 22.835 126.744 ;
     RECT  21.604 45.792 24.008 45.816 ;
     RECT  21.604 47.088 24.008 47.112 ;
     RECT  22.493 99.984 24.008 100.008 ;
     RECT  22.645 118.656 24.008 119.112 ;
     RECT  22.835 126.72 24.008 126.744 ;
     RECT  24.008 2.148 24.112 168.492 ;
     RECT  24.112 2.418 24.304 168.222 ;
     RECT  24.304 118.656 24.833 118.92 ;
     RECT  24.304 45.792 26.708 45.816 ;
     RECT  24.304 47.088 26.708 47.112 ;
     RECT  24.304 99.984 26.708 100.008 ;
     RECT  24.833 118.896 26.708 118.92 ;
     RECT  24.304 126.72 26.708 126.744 ;
     RECT  26.708 2.148 26.812 168.492 ;
     RECT  26.812 2.418 27.004 168.222 ;
     RECT  27.004 45.792 29.408 45.816 ;
     RECT  27.004 47.088 29.408 47.112 ;
     RECT  27.004 99.984 29.408 100.008 ;
     RECT  27.004 118.944 29.408 118.968 ;
     RECT  27.004 126.72 29.408 126.744 ;
     RECT  29.408 2.148 29.512 168.492 ;
     RECT  29.512 2.418 29.704 168.222 ;
     RECT  29.704 118.848 30.769 118.872 ;
     RECT  30.769 118.848 30.809 118.968 ;
     RECT  29.704 45.792 32.108 45.816 ;
     RECT  29.704 47.088 32.108 47.112 ;
     RECT  29.704 99.984 32.108 100.008 ;
     RECT  30.809 118.944 32.108 118.968 ;
     RECT  29.704 126.72 32.108 126.744 ;
     RECT  32.108 2.148 32.212 168.492 ;
     RECT  32.212 2.418 32.404 168.222 ;
     RECT  32.404 126.72 34.729 126.744 ;
     RECT  32.404 45.792 34.808 45.816 ;
     RECT  32.404 47.088 34.808 47.112 ;
     RECT  32.404 99.984 34.808 100.008 ;
     RECT  32.404 118.944 34.808 118.968 ;
     RECT  34.729 126.528 34.808 126.744 ;
     RECT  34.657 129.936 34.808 129.96 ;
     RECT  34.693 131.04 34.808 131.064 ;
     RECT  34.405 133.824 34.808 133.848 ;
     RECT  34.693 135.648 34.808 135.672 ;
     RECT  34.585 136.752 34.808 136.776 ;
     RECT  34.808 2.148 34.912 168.492 ;
     RECT  34.912 2.418 35.104 168.222 ;
     RECT  35.104 136.752 35.363 137.496 ;
     RECT  35.104 138.72 35.363 138.792 ;
     RECT  35.104 128.976 35.453 134.52 ;
     RECT  35.363 137.328 35.597 137.496 ;
     RECT  35.453 128.976 35.661 133.848 ;
     RECT  35.104 140.592 35.677 141.912 ;
     RECT  35.104 121.92 35.795 123.624 ;
     RECT  35.661 131.856 35.849 133.848 ;
     RECT  35.661 128.976 35.884 130.536 ;
     RECT  35.363 138.768 35.891 138.792 ;
     RECT  35.677 141.888 35.987 141.912 ;
     RECT  35.795 122.496 36.065 123.624 ;
     RECT  35.849 131.856 36.065 132.984 ;
     RECT  35.104 125.136 36.133 125.448 ;
     RECT  36.133 124.992 36.173 125.448 ;
     RECT  35.884 129.84 36.173 130.536 ;
     RECT  35.597 137.328 36.925 137.352 ;
     RECT  35.104 135.6 37.033 135.672 ;
     RECT  36.925 137.28 37.052 137.352 ;
     RECT  36.709 134.208 37.093 134.232 ;
     RECT  37.033 135.6 37.093 136.248 ;
     RECT  36.173 124.992 37.141 125.352 ;
     RECT  35.104 126.72 37.141 127.656 ;
     RECT  37.1 129.024 37.141 129.048 ;
     RECT  36.173 130.32 37.141 130.536 ;
     RECT  36.065 131.856 37.141 132.504 ;
     RECT  37.093 134.208 37.141 136.248 ;
     RECT  35.677 140.592 37.177 140.616 ;
     RECT  37.141 129.024 37.321 129.192 ;
     RECT  37.141 130.32 37.321 132.504 ;
     RECT  37.052 137.28 37.381 138.024 ;
     RECT  35.104 45.792 37.508 45.816 ;
     RECT  35.104 47.088 37.508 47.112 ;
     RECT  35.104 99.984 37.508 100.008 ;
     RECT  35.104 118.944 37.508 118.968 ;
     RECT  36.065 122.496 37.508 123.48 ;
     RECT  37.141 124.992 37.508 127.656 ;
     RECT  37.321 129.024 37.508 132.504 ;
     RECT  37.141 133.68 37.508 136.248 ;
     RECT  37.381 137.28 37.508 138.888 ;
     RECT  37.177 140.016 37.508 140.616 ;
     RECT  35.104 165.888 37.508 165.912 ;
     RECT  37.508 2.148 37.612 168.492 ;
     RECT  37.612 2.418 37.804 168.222 ;
     RECT  37.825 170.352 37.957 170.376 ;
     RECT  37.804 132.96 37.973 135.672 ;
     RECT  37.804 99.984 38.003 100.536 ;
     RECT  37.957 170.352 38.044 170.52 ;
     RECT  38.044 170.352 38.153 170.472 ;
     RECT  37.973 132.96 38.195 135.576 ;
     RECT  37.804 140.016 38.195 140.664 ;
     RECT  37.804 141.888 38.195 142.776 ;
     RECT  37.804 143.856 38.195 143.88 ;
     RECT  37.804 145.92 38.297 145.944 ;
     RECT  37.804 123.456 38.369 127.368 ;
     RECT  38.369 123.456 38.441 126.792 ;
     RECT  38.195 135.552 38.483 135.576 ;
     RECT  37.804 54.72 38.531 54.744 ;
     RECT  37.804 118.944 38.531 119.112 ;
     RECT  37.804 162.144 38.579 163.032 ;
     RECT  37.804 166.32 38.62 166.344 ;
     RECT  37.804 93.312 38.627 95.784 ;
     RECT  37.804 147.6 38.627 147.624 ;
     RECT  38.441 123.456 38.657 126.744 ;
     RECT  38.627 93.312 38.668 93.624 ;
     RECT  37.804 148.944 38.668 150.552 ;
     RECT  37.804 52.224 38.765 53.544 ;
     RECT  38.195 132.96 38.765 134.136 ;
     RECT  38.765 52.224 38.771 53.064 ;
     RECT  38.531 119.088 38.771 119.112 ;
     RECT  38.765 132.96 38.771 132.984 ;
     RECT  38.668 149.28 38.771 150.552 ;
     RECT  38.579 162.144 38.771 162.168 ;
     RECT  38.765 133.968 38.801 134.136 ;
     RECT  37.804 167.616 38.801 167.64 ;
     RECT  37.804 50.736 38.869 50.76 ;
     RECT  37.804 109.68 38.869 109.704 ;
     RECT  38.861 138.528 38.876 138.552 ;
     RECT  38.003 100.272 38.915 100.536 ;
     RECT  38.195 142.752 38.917 142.776 ;
     RECT  38.771 52.224 38.924 52.248 ;
     RECT  38.876 138.528 38.963 138.984 ;
     RECT  38.869 109.68 39.013 110.04 ;
     RECT  37.804 131.04 39.017 131.064 ;
     RECT  38.801 134.112 39.017 134.136 ;
     RECT  38.771 149.28 39.017 150.456 ;
     RECT  38.657 124.848 39.097 126.744 ;
     RECT  38.833 147.072 39.155 147.096 ;
     RECT  38.917 145.536 39.189 145.56 ;
     RECT  39.085 130.944 39.193 130.968 ;
     RECT  38.915 100.512 39.197 100.536 ;
     RECT  38.195 140.016 39.233 140.04 ;
     RECT  38.153 170.448 39.395 170.472 ;
     RECT  37.804 136.704 39.445 137.544 ;
     RECT  39.493 141.456 39.541 141.48 ;
     RECT  39.445 92.448 39.553 92.472 ;
     RECT  39.097 125.424 39.553 126.744 ;
     RECT  39.553 125.424 39.625 126.792 ;
     RECT  38.869 50.4 39.685 50.76 ;
     RECT  38.924 52.08 39.685 52.248 ;
     RECT  39.553 91.584 39.769 92.472 ;
     RECT  38.668 93.6 39.769 93.624 ;
     RECT  39.805 49.248 39.841 49.272 ;
     RECT  38.657 123.456 39.841 123.672 ;
     RECT  39.841 49.008 39.913 49.272 ;
     RECT  39.841 123.024 39.949 124.296 ;
     RECT  39.625 125.424 39.973 127.368 ;
     RECT  38.797 128.832 39.973 128.856 ;
     RECT  39.541 141.36 39.98 141.48 ;
     RECT  38.917 142.752 39.98 143.16 ;
     RECT  39.769 91.584 39.985 93.624 ;
     RECT  39.949 122.496 39.985 124.296 ;
     RECT  39.253 132.288 39.985 132.312 ;
     RECT  39.973 125.424 40.021 129.144 ;
     RECT  39.193 130.704 40.021 130.968 ;
     RECT  39.985 132.288 40.021 133.224 ;
     RECT  37.804 45.792 40.057 45.816 ;
     RECT  37.804 47.088 40.057 47.112 ;
     RECT  39.013 109.68 40.069 110.52 ;
     RECT  39.685 50.4 40.093 52.248 ;
     RECT  39.493 134.544 40.165 134.568 ;
     RECT  39.985 121.824 40.201 124.296 ;
     RECT  40.021 125.424 40.201 129.24 ;
     RECT  40.057 45.792 40.208 47.112 ;
     RECT  39.913 48.192 40.208 49.272 ;
     RECT  40.093 50.304 40.208 52.248 ;
     RECT  38.965 73.824 40.208 73.848 ;
     RECT  40.069 83.76 40.208 83.784 ;
     RECT  39.733 85.296 40.208 85.32 ;
     RECT  39.877 88.368 40.208 88.392 ;
     RECT  40.028 90.48 40.208 90.504 ;
     RECT  39.985 91.584 40.208 93.768 ;
     RECT  38.627 94.944 40.208 94.968 ;
     RECT  39.349 105.936 40.208 105.96 ;
     RECT  40.069 109.44 40.208 110.52 ;
     RECT  40.201 121.824 40.208 129.24 ;
     RECT  40.021 130.704 40.208 133.224 ;
     RECT  40.165 134.544 40.208 135.192 ;
     RECT  39.445 136.176 40.208 137.544 ;
     RECT  38.963 138.528 40.208 138.744 ;
     RECT  39.5 140.208 40.208 140.232 ;
     RECT  39.98 141.36 40.208 143.16 ;
     RECT  39.017 149.28 40.208 149.688 ;
     RECT  40.208 2.148 40.312 168.492 ;
     RECT  40.312 2.418 40.504 168.222 ;
     RECT  40.504 43.344 40.637 45.864 ;
     RECT  40.504 109.44 40.643 110.52 ;
     RECT  40.504 47.904 40.825 53.016 ;
     RECT  40.504 128.304 40.889 128.328 ;
     RECT  40.504 126.48 40.925 126.744 ;
     RECT  40.504 121.824 40.961 125.496 ;
     RECT  40.504 142.512 41.033 142.536 ;
     RECT  40.961 121.824 41.213 124.632 ;
     RECT  40.504 117.984 41.459 118.344 ;
     RECT  41.213 121.824 41.459 123.24 ;
     RECT  40.504 114.528 41.465 114.552 ;
     RECT  40.504 89.952 41.497 94.008 ;
     RECT  40.504 95.712 41.497 96.792 ;
     RECT  40.504 139.104 41.497 139.128 ;
     RECT  40.825 47.904 41.533 52.824 ;
     RECT  40.637 44.16 41.569 45.864 ;
     RECT  40.504 87.456 41.569 87.48 ;
     RECT  41.497 88.992 41.569 94.008 ;
     RECT  41.497 95.04 41.569 96.792 ;
     RECT  40.925 126.72 41.677 126.744 ;
     RECT  40.504 132.384 41.677 135.384 ;
     RECT  41.569 87.456 41.713 87.672 ;
     RECT  41.569 44.16 41.749 46.008 ;
     RECT  40.504 130.752 41.749 130.776 ;
     RECT  41.677 131.808 41.749 135.384 ;
     RECT  41.605 137.856 41.749 137.88 ;
     RECT  41.497 139.104 41.749 140.088 ;
     RECT  41.749 44.16 41.785 46.392 ;
     RECT  41.749 137.856 41.785 140.088 ;
     RECT  41.785 43.344 41.821 46.392 ;
     RECT  41.713 87.456 41.821 87.96 ;
     RECT  41.569 88.992 41.821 96.792 ;
     RECT  41.749 114 41.833 114.024 ;
     RECT  41.821 87.456 41.857 96.792 ;
     RECT  41.785 137.76 41.857 140.088 ;
     RECT  41.821 43.344 41.929 46.488 ;
     RECT  41.533 47.808 41.929 52.824 ;
     RECT  41.929 43.344 41.965 52.824 ;
     RECT  41.785 125.664 41.965 125.688 ;
     RECT  41.677 126.72 41.965 127.032 ;
     RECT  41.749 84.336 41.989 84.36 ;
     RECT  40.504 107.616 41.989 108.312 ;
     RECT  40.504 60.576 42.145 60.6 ;
     RECT  41.857 87.456 42.145 96.888 ;
     RECT  41.857 137.76 42.181 140.184 ;
     RECT  41.965 43.344 42.227 53.784 ;
     RECT  41.989 83.52 42.289 84.36 ;
     RECT  42.289 82.08 42.361 82.104 ;
     RECT  42.289 83.232 42.361 84.36 ;
     RECT  41.213 124.56 42.361 124.632 ;
     RECT  41.965 125.664 42.361 127.032 ;
     RECT  42.361 36.48 42.389 36.504 ;
     RECT  42.397 38.784 42.461 38.808 ;
     RECT  40.504 103.824 42.469 103.848 ;
     RECT  42.361 124.56 42.469 127.032 ;
     RECT  41.749 130.752 42.541 135.384 ;
     RECT  40.504 147.12 42.541 147.144 ;
     RECT  42.389 36.48 42.565 37.032 ;
     RECT  42.145 87.36 42.661 96.888 ;
     RECT  42.469 124.272 42.661 127.032 ;
     RECT  42.661 64.944 42.709 64.968 ;
     RECT  42.541 130.512 42.709 135.384 ;
     RECT  42.661 124.272 42.761 127.656 ;
     RECT  42.421 128.784 42.869 128.808 ;
     RECT  42.325 34.224 42.908 34.248 ;
     RECT  42.565 36.48 42.908 37.656 ;
     RECT  42.461 38.784 42.908 39.336 ;
     RECT  42.709 64.608 42.908 64.968 ;
     RECT  40.504 73.824 42.908 73.848 ;
     RECT  42.253 80.928 42.908 80.952 ;
     RECT  42.361 82.08 42.908 84.36 ;
     RECT  40.504 105.936 42.908 105.96 ;
     RECT  41.989 107.472 42.908 108.312 ;
     RECT  40.643 110.496 42.908 110.52 ;
     RECT  41.509 116.88 42.908 116.904 ;
     RECT  41.459 118.32 42.908 118.344 ;
     RECT  41.459 122.112 42.908 122.136 ;
     RECT  41.459 123.216 42.908 123.24 ;
     RECT  42.761 124.272 42.908 127.452 ;
     RECT  42.908 2.148 43.012 41.052 ;
     RECT  42.908 62.628 43.012 84.36 ;
     RECT  42.908 105.828 43.012 127.452 ;
     RECT  42.908 149.028 43.012 168.492 ;
     RECT  42.661 87.168 43.081 96.888 ;
     RECT  42.709 130.368 43.081 135.384 ;
     RECT  43.081 129.456 43.2 135.384 ;
     RECT  42.181 137.28 43.2 140.184 ;
     RECT  43.012 2.418 43.204 40.782 ;
     RECT  43.012 62.898 43.204 84.36 ;
     RECT  43.012 105.936 43.204 127.182 ;
     RECT  43.012 149.298 43.204 168.222 ;
     RECT  43.204 83.52 43.229 84.36 ;
     RECT  43.204 107.808 43.265 108.504 ;
     RECT  42.227 43.968 43.272 53.784 ;
     RECT  42.145 60.576 43.272 61.08 ;
     RECT  43.081 87.168 43.272 96.984 ;
     RECT  42.469 103.776 43.272 103.848 ;
     RECT  43.2 129.456 43.272 140.184 ;
     RECT  42.541 147.072 43.272 147.144 ;
     RECT  43.229 83.52 43.301 83.64 ;
     RECT  43.272 129.456 43.331 147.144 ;
     RECT  43.204 64.608 43.553 64.968 ;
     RECT  43.265 108.192 43.553 108.504 ;
     RECT  43.553 108.192 43.589 108.312 ;
     RECT  43.301 83.616 43.625 83.64 ;
     RECT  43.553 64.944 45.608 64.968 ;
     RECT  43.204 73.824 45.608 73.848 ;
     RECT  44.732 84.096 45.608 84.12 ;
     RECT  43.204 105.936 45.608 105.96 ;
     RECT  43.589 108.288 45.608 108.312 ;
     RECT  43.204 110.496 45.608 110.52 ;
     RECT  45.608 2.148 45.712 41.052 ;
     RECT  45.608 62.628 45.712 84.252 ;
     RECT  45.608 105.828 45.712 127.452 ;
     RECT  45.608 149.028 45.712 168.492 ;
     RECT  45.712 2.418 45.904 40.782 ;
     RECT  45.712 62.898 45.904 83.982 ;
     RECT  45.712 105.936 45.904 127.182 ;
     RECT  45.712 149.298 45.904 168.222 ;
     RECT  45.904 73.824 46.793 73.944 ;
     RECT  46.793 73.824 48.308 73.848 ;
     RECT  45.904 105.936 48.308 105.96 ;
     RECT  45.904 110.496 48.308 110.52 ;
     RECT  48.308 2.148 48.412 41.052 ;
     RECT  48.308 62.628 48.412 84.252 ;
     RECT  48.308 105.828 48.412 127.452 ;
     RECT  48.308 149.028 48.412 168.492 ;
     RECT  48.412 2.418 48.604 40.782 ;
     RECT  48.412 62.898 48.604 83.982 ;
     RECT  48.412 105.936 48.604 127.182 ;
     RECT  48.412 149.298 48.604 168.222 ;
     RECT  48.604 73.824 51.008 73.848 ;
     RECT  48.604 105.936 51.008 105.96 ;
     RECT  48.604 110.496 51.008 110.52 ;
     RECT  51.008 2.148 51.112 41.052 ;
     RECT  51.008 62.628 51.112 84.252 ;
     RECT  51.008 105.828 51.112 127.452 ;
     RECT  51.008 149.028 51.112 168.492 ;
     RECT  51.112 2.418 51.304 40.782 ;
     RECT  51.112 62.898 51.304 83.982 ;
     RECT  51.112 105.936 51.304 127.182 ;
     RECT  51.112 149.298 51.304 168.222 ;
     RECT  51.304 73.824 53.708 73.848 ;
     RECT  51.304 105.936 53.708 105.96 ;
     RECT  51.304 110.496 53.708 110.52 ;
     RECT  53.708 2.148 53.812 41.052 ;
     RECT  53.708 62.628 53.812 84.252 ;
     RECT  53.708 105.828 53.812 127.452 ;
     RECT  53.708 149.028 53.812 168.492 ;
     RECT  53.812 2.418 54.004 40.782 ;
     RECT  53.812 62.898 54.004 83.982 ;
     RECT  53.812 105.936 54.004 127.182 ;
     RECT  53.812 149.298 54.004 168.222 ;
     RECT  54.004 73.824 54.749 73.944 ;
     RECT  54.749 73.824 56.408 73.848 ;
     RECT  54.004 105.936 56.408 105.96 ;
     RECT  54.004 110.496 56.408 110.52 ;
     RECT  56.408 2.148 56.512 41.052 ;
     RECT  56.408 62.628 56.512 84.252 ;
     RECT  56.408 105.828 56.512 127.452 ;
     RECT  56.408 149.028 56.512 168.492 ;
     RECT  56.512 2.418 56.704 40.782 ;
     RECT  56.512 62.898 56.704 83.982 ;
     RECT  56.512 105.936 56.704 127.182 ;
     RECT  56.512 149.298 56.704 168.222 ;
     RECT  56.704 73.824 59.108 73.848 ;
     RECT  56.704 105.936 59.108 105.96 ;
     RECT  56.704 110.496 59.108 110.52 ;
     RECT  59.108 2.148 59.212 41.052 ;
     RECT  59.108 62.628 59.212 84.252 ;
     RECT  59.108 105.828 59.212 127.452 ;
     RECT  59.108 149.028 59.212 168.492 ;
     RECT  59.212 2.418 59.404 40.782 ;
     RECT  59.212 62.898 59.404 83.982 ;
     RECT  59.212 105.936 59.404 127.182 ;
     RECT  59.212 149.298 59.404 168.222 ;
     RECT  59.404 73.824 61.808 73.848 ;
     RECT  59.404 105.936 61.808 105.96 ;
     RECT  59.404 110.496 61.808 110.52 ;
     RECT  61.808 2.148 61.912 41.052 ;
     RECT  61.808 62.628 61.912 84.252 ;
     RECT  61.808 105.828 61.912 127.452 ;
     RECT  61.808 149.028 61.912 168.492 ;
     RECT  61.912 2.418 62.104 40.782 ;
     RECT  61.912 62.898 62.104 83.982 ;
     RECT  61.912 105.936 62.104 127.182 ;
     RECT  61.912 149.298 62.104 168.222 ;
     RECT  62.104 73.92 62.741 74.088 ;
     RECT  62.741 74.064 64.508 74.088 ;
     RECT  62.104 105.936 64.508 105.96 ;
     RECT  62.104 110.496 64.508 110.52 ;
     RECT  64.508 2.148 64.612 41.052 ;
     RECT  64.508 62.628 64.612 84.252 ;
     RECT  64.508 105.828 64.612 127.452 ;
     RECT  64.508 149.028 64.612 168.492 ;
     RECT  64.612 62.898 64.717 84.252 ;
     RECT  64.612 2.418 64.804 40.782 ;
     RECT  64.717 62.898 64.804 84.36 ;
     RECT  64.612 105.888 64.804 127.182 ;
     RECT  64.612 149.298 64.804 168.222 ;
     RECT  64.804 84.336 65.267 84.36 ;
     RECT  64.804 105.888 65.305 105.912 ;
     RECT  64.804 74.064 66.181 74.088 ;
     RECT  66.14 84.096 66.227 84.12 ;
     RECT  64.804 110.256 66.227 110.52 ;
     RECT  66.181 73.824 67.208 74.088 ;
     RECT  66.227 110.496 67.208 110.52 ;
     RECT  67.208 2.148 67.312 41.052 ;
     RECT  67.208 62.628 67.312 84.252 ;
     RECT  67.208 105.828 67.312 127.452 ;
     RECT  67.208 149.028 67.312 168.492 ;
     RECT  67.312 2.418 67.504 40.782 ;
     RECT  67.312 62.898 67.504 83.982 ;
     RECT  67.312 106.098 67.504 127.182 ;
     RECT  67.312 149.298 67.504 168.222 ;
     RECT  67.504 73.824 69.908 74.088 ;
     RECT  67.504 110.496 69.908 110.52 ;
     RECT  69.908 2.148 70.012 41.052 ;
     RECT  69.908 62.628 70.012 84.252 ;
     RECT  69.908 105.828 70.012 127.452 ;
     RECT  69.908 149.028 70.012 168.492 ;
     RECT  70.012 2.418 70.204 40.782 ;
     RECT  70.012 62.898 70.204 83.982 ;
     RECT  70.012 106.098 70.204 127.182 ;
     RECT  70.012 149.298 70.204 168.222 ;
     RECT  43.331 129.6 70.691 147.144 ;
     RECT  70.204 73.824 72.608 74.088 ;
     RECT  70.204 110.496 72.608 110.52 ;
     RECT  72.608 2.148 72.712 41.052 ;
     RECT  72.608 62.628 72.712 84.252 ;
     RECT  72.608 105.828 72.712 127.452 ;
     RECT  72.608 149.028 72.712 168.492 ;
     RECT  72.712 2.418 72.904 40.782 ;
     RECT  72.712 62.898 72.904 83.982 ;
     RECT  72.712 106.098 72.904 127.182 ;
     RECT  72.712 149.298 72.904 168.222 ;
     RECT  72.904 126.432 73.969 126.456 ;
     RECT  73.969 126.432 74.009 126.984 ;
     RECT  43.272 43.2 75.12 61.08 ;
     RECT  43.272 86.4 75.12 103.848 ;
     RECT  70.691 129.6 75.12 147.192 ;
     RECT  75.12 43.2 75.157 53.88 ;
     RECT  74.009 126.96 75.193 126.984 ;
     RECT  75.116 41.616 75.203 41.64 ;
     RECT  75.157 84.96 75.269 84.984 ;
     RECT  75.12 87.168 75.305 96.984 ;
     RECT  72.904 73.824 75.308 74.088 ;
     RECT  72.904 110.496 75.308 110.52 ;
     RECT  74.113 125.04 75.308 125.064 ;
     RECT  75.193 126.96 75.308 127.032 ;
     RECT  75.157 43.056 75.341 53.88 ;
     RECT  75.305 87.168 75.341 96.888 ;
     RECT  75.12 130.32 75.341 140.184 ;
     RECT  75.341 43.056 75.377 53.688 ;
     RECT  75.157 128.832 75.377 128.856 ;
     RECT  75.341 130.32 75.377 140.088 ;
     RECT  75.308 2.148 75.412 41.052 ;
     RECT  75.308 62.628 75.412 84.252 ;
     RECT  75.308 105.828 75.412 127.452 ;
     RECT  75.308 149.028 75.412 168.492 ;
     RECT  75.12 147.072 75.413 147.192 ;
     RECT  75.377 43.056 75.449 53.592 ;
     RECT  75.12 103.776 75.521 103.848 ;
     RECT  75.412 2.418 75.604 40.782 ;
     RECT  75.412 62.898 75.604 83.982 ;
     RECT  75.412 106.098 75.604 127.182 ;
     RECT  75.412 149.298 75.604 168.222 ;
     RECT  75.604 125.856 75.665 127.08 ;
     RECT  75.413 147.072 75.665 147.144 ;
     RECT  75.604 110.496 75.731 110.52 ;
     RECT  75.665 125.856 75.731 125.88 ;
     RECT  75.665 127.008 75.953 127.08 ;
     RECT  75.449 43.968 76.673 53.592 ;
     RECT  76.673 43.968 76.709 53.496 ;
     RECT  75.604 73.824 77.065 74.088 ;
     RECT  76.709 43.968 78.008 53.4 ;
     RECT  75.12 60.576 78.008 61.08 ;
     RECT  77.065 73.776 78.008 74.088 ;
     RECT  75.341 87.168 78.008 96.792 ;
     RECT  75.12 101.328 78.008 101.352 ;
     RECT  75.521 103.776 78.008 103.8 ;
     RECT  75.953 127.056 78.008 127.08 ;
     RECT  75.377 130.32 78.008 139.992 ;
     RECT  75.665 147.072 78.008 147.096 ;
     RECT  78.008 2.148 78.112 168.492 ;
     RECT  78.112 2.418 78.304 168.222 ;
     RECT  78.304 87.36 78.365 91.08 ;
     RECT  78.304 44.064 78.617 47.64 ;
     RECT  78.365 87.36 78.689 90.648 ;
     RECT  78.304 130.464 78.689 132.456 ;
     RECT  78.617 44.064 79.265 47.448 ;
     RECT  79.265 44.16 80.708 47.448 ;
     RECT  78.304 60.576 80.708 61.176 ;
     RECT  78.304 73.776 80.708 73.8 ;
     RECT  78.689 87.552 80.708 90.648 ;
     RECT  78.304 101.328 80.708 101.352 ;
     RECT  78.304 103.776 80.708 103.8 ;
     RECT  78.689 130.512 80.708 132.456 ;
     RECT  78.304 147.072 80.708 147.096 ;
     RECT  80.708 2.148 80.812 168.492 ;
     RECT  80.812 2.418 81.004 168.222 ;
     RECT  81.004 44.16 81.533 47.448 ;
     RECT  81.533 44.16 82.073 47.16 ;
     RECT  82.073 44.16 83.408 46.584 ;
     RECT  81.004 60.576 83.408 61.176 ;
     RECT  81.004 73.776 83.408 73.8 ;
     RECT  81.004 87.552 83.408 90.648 ;
     RECT  81.004 101.328 83.408 101.352 ;
     RECT  81.004 103.776 83.408 103.8 ;
     RECT  81.004 130.752 83.408 132.456 ;
     RECT  81.004 147.072 83.408 147.096 ;
     RECT  83.408 2.148 83.512 168.492 ;
     RECT  83.512 2.418 83.704 168.222 ;
     RECT  83.704 88.176 83.801 90.648 ;
     RECT  83.704 44.16 84.017 46.584 ;
     RECT  84.017 44.64 84.089 46.584 ;
     RECT  83.704 131.136 84.305 132.456 ;
     RECT  84.305 131.328 84.377 132.456 ;
     RECT  84.089 45.264 84.413 46.584 ;
     RECT  84.377 131.568 84.521 132.456 ;
     RECT  83.801 88.704 84.557 88.728 ;
     RECT  84.521 131.952 84.629 132.456 ;
     RECT  84.413 45.264 84.917 45.288 ;
     RECT  83.801 90.096 84.917 90.12 ;
     RECT  84.413 46.56 86.108 46.584 ;
     RECT  83.704 60.576 86.108 61.176 ;
     RECT  83.704 73.776 86.108 73.8 ;
     RECT  83.704 101.328 86.108 101.352 ;
     RECT  83.704 103.776 86.108 103.8 ;
     RECT  84.629 132.432 86.108 132.456 ;
     RECT  83.704 147.072 86.108 147.096 ;
     RECT  86.108 2.148 86.212 168.492 ;
     RECT  86.212 2.418 86.404 168.222 ;
     RECT  86.404 132.336 86.681 132.456 ;
     RECT  86.404 60.576 88.808 61.176 ;
     RECT  86.404 73.776 88.808 73.8 ;
     RECT  86.404 101.328 88.808 101.352 ;
     RECT  86.404 103.776 88.808 103.8 ;
     RECT  86.681 132.432 88.808 132.456 ;
     RECT  86.404 147.072 88.808 147.096 ;
     RECT  88.808 2.148 88.912 168.492 ;
     RECT  88.912 2.418 89.104 168.222 ;
     RECT  89.104 97.392 89.603 98.472 ;
     RECT  89.603 97.92 90.083 98.472 ;
     RECT  89.104 125.376 90.083 126.12 ;
     RECT  89.104 42.192 90.133 42.216 ;
     RECT  89.104 99.744 90.137 99.768 ;
     RECT  89.104 55.632 90.205 55.656 ;
     RECT  90.205 55.152 90.245 55.656 ;
     RECT  89.104 132.432 90.277 132.456 ;
     RECT  89.104 140.688 90.277 140.712 ;
     RECT  90.083 126.096 90.317 126.12 ;
     RECT  90.236 139.104 90.323 139.128 ;
     RECT  90.277 140.208 90.385 140.712 ;
     RECT  90.133 41.568 90.421 42.216 ;
     RECT  89.104 141.792 90.497 141.816 ;
     RECT  89.104 82.752 90.529 82.776 ;
     RECT  90.385 140.16 90.613 140.712 ;
     RECT  90.529 81.984 90.637 82.776 ;
     RECT  89.104 83.76 90.637 83.784 ;
     RECT  90.601 126.432 91.045 126.552 ;
     RECT  89.104 53.04 91.141 53.064 ;
     RECT  90.613 139.632 91.141 140.712 ;
     RECT  90.083 98.448 91.321 98.472 ;
     RECT  90.245 55.152 91.349 55.176 ;
     RECT  90.925 85.488 91.381 85.512 ;
     RECT  91.321 97.92 91.381 98.472 ;
     RECT  90.529 39.6 91.508 39.624 ;
     RECT  90.421 41.568 91.508 43.032 ;
     RECT  91.141 53.04 91.508 53.592 ;
     RECT  91.349 55.008 91.508 55.176 ;
     RECT  89.104 60.576 91.508 61.176 ;
     RECT  91.381 70.8 91.508 70.824 ;
     RECT  89.104 73.776 91.508 73.8 ;
     RECT  90.637 81.984 91.508 83.784 ;
     RECT  91.381 84.864 91.508 85.512 ;
     RECT  91.069 96.864 91.508 96.888 ;
     RECT  91.381 97.92 91.508 98.664 ;
     RECT  91.321 100.08 91.508 100.104 ;
     RECT  89.104 101.328 91.508 101.352 ;
     RECT  89.104 103.776 91.508 103.8 ;
     RECT  91.357 125.424 91.508 125.448 ;
     RECT  91.045 126.432 91.508 127.08 ;
     RECT  90.277 132.432 91.508 132.792 ;
     RECT  91.141 139.632 91.508 140.808 ;
     RECT  91.069 142.464 91.508 142.488 ;
     RECT  89.104 147.072 91.508 147.096 ;
     RECT  91.508 2.148 91.612 168.492 ;
     RECT  91.612 2.418 91.804 168.222 ;
     RECT  91.804 81.984 92.009 82.968 ;
     RECT  91.804 140.208 92.441 140.808 ;
     RECT  92.009 82.752 92.549 82.968 ;
     RECT  91.804 97.92 92.657 98.664 ;
     RECT  91.804 101.424 92.675 101.448 ;
     RECT  91.804 84.96 92.729 84.984 ;
     RECT  91.804 125.424 92.869 125.448 ;
     RECT  91.804 126.48 92.909 126.504 ;
     RECT  91.804 41.664 92.945 42.84 ;
     RECT  91.804 100.08 92.945 100.104 ;
     RECT  91.804 142.128 93.013 142.152 ;
     RECT  93.049 56.592 93.121 56.616 ;
     RECT  93.013 141.552 93.161 142.536 ;
     RECT  92.549 82.944 93.373 82.968 ;
     RECT  91.804 96.288 93.373 96.312 ;
     RECT  91.804 40.56 93.445 40.584 ;
     RECT  91.804 53.568 93.481 54.744 ;
     RECT  91.804 70.8 93.5 70.824 ;
     RECT  93.481 52.752 93.661 54.744 ;
     RECT  93.661 52.752 93.733 55.32 ;
     RECT  93.161 142.512 93.913 142.536 ;
     RECT  92.441 140.208 94.057 140.232 ;
     RECT  92.905 85.392 94.069 85.416 ;
     RECT  92.657 98.64 94.165 98.664 ;
     RECT  91.804 39.312 94.208 39.336 ;
     RECT  93.445 40.416 94.208 41.256 ;
     RECT  92.945 42.432 94.208 42.84 ;
     RECT  93.733 52.464 94.208 55.32 ;
     RECT  93.121 56.592 94.208 56.664 ;
     RECT  91.804 60.576 94.208 61.176 ;
     RECT  93.5 70.8 94.208 71.208 ;
     RECT  93.541 81.312 94.208 81.336 ;
     RECT  93.373 82.944 94.208 83.832 ;
     RECT  94.069 85.104 94.208 85.416 ;
     RECT  93.373 96.288 94.208 97.08 ;
     RECT  94.165 98.064 94.208 98.664 ;
     RECT  93.769 100.32 94.208 100.344 ;
     RECT  91.804 103.776 94.208 103.8 ;
     RECT  92.869 125.328 94.208 125.496 ;
     RECT  93.013 127.248 94.208 127.272 ;
     RECT  94.057 139.488 94.208 140.232 ;
     RECT  93.913 142.512 94.208 143.208 ;
     RECT  91.804 147.072 94.208 147.096 ;
     RECT  94.208 2.148 94.312 168.492 ;
     RECT  94.312 2.418 94.504 168.222 ;
     RECT  94.504 103.776 94.745 103.8 ;
     RECT  94.504 142.128 94.781 143.208 ;
     RECT  94.504 60.576 94.817 60.6 ;
     RECT  94.504 127.248 94.817 127.272 ;
     RECT  94.504 147.072 95.033 147.096 ;
     RECT  94.504 39.312 95.713 42.216 ;
     RECT  94.504 43.2 95.713 43.224 ;
     RECT  94.504 96.576 95.713 98.856 ;
     RECT  94.504 100.08 95.713 100.824 ;
     RECT  95.713 39.312 95.749 43.224 ;
     RECT  94.504 52.848 95.749 53.736 ;
     RECT  94.504 85.68 95.749 85.704 ;
     RECT  94.504 139.488 95.749 141.144 ;
     RECT  94.504 83.088 95.785 83.832 ;
     RECT  95.749 84.96 95.785 85.704 ;
     RECT  94.781 142.128 95.785 143.016 ;
     RECT  95.749 139.248 95.893 141.144 ;
     RECT  95.785 142.128 95.893 143.448 ;
     RECT  95.749 52.56 96.289 53.736 ;
     RECT  94.504 54.72 96.289 57.048 ;
     RECT  95.893 81.792 96.289 81.816 ;
     RECT  95.713 96.576 96.289 100.824 ;
     RECT  94.504 125.136 96.289 126.168 ;
     RECT  95.785 83.088 96.325 85.704 ;
     RECT  96.289 81.36 96.901 81.816 ;
     RECT  96.325 82.944 96.901 85.704 ;
     RECT  95.893 139.248 96.901 143.448 ;
     RECT  96.901 81.36 96.937 85.704 ;
     RECT  95.749 38.736 98.22 43.224 ;
     RECT  96.289 52.56 98.22 57.048 ;
     RECT  96.937 81.36 98.22 85.848 ;
     RECT  96.289 96.336 98.22 100.824 ;
     RECT  96.289 125.136 98.22 126.888 ;
     RECT  96.901 138.96 98.22 143.448 ;
     RECT  98.22 96.576 98.273 96.6 ;
     RECT  98.22 139.488 98.273 139.512 ;
    LAYER M5 ;
     RECT  2.4 2.137 2.52 2.151 ;
     RECT  5.1 2.137 5.22 2.151 ;
     RECT  7.8 2.137 7.92 2.151 ;
     RECT  10.5 2.137 10.62 2.151 ;
     RECT  13.2 2.137 13.32 2.151 ;
     RECT  15.9 2.137 16.02 2.151 ;
     RECT  18.6 2.137 18.72 2.151 ;
     RECT  21.3 2.137 21.42 2.151 ;
     RECT  24 2.137 24.12 2.151 ;
     RECT  26.7 2.137 26.82 2.151 ;
     RECT  29.4 2.137 29.52 2.151 ;
     RECT  32.1 2.137 32.22 2.151 ;
     RECT  34.8 2.137 34.92 2.151 ;
     RECT  37.5 2.137 37.62 2.151 ;
     RECT  40.2 2.137 40.32 2.151 ;
     RECT  42.9 2.137 43.02 2.151 ;
     RECT  45.6 2.137 45.72 2.151 ;
     RECT  48.3 2.137 48.42 2.151 ;
     RECT  51 2.137 51.12 2.151 ;
     RECT  53.7 2.137 53.82 2.151 ;
     RECT  56.4 2.137 56.52 2.151 ;
     RECT  59.1 2.137 59.22 2.151 ;
     RECT  61.8 2.137 61.92 2.151 ;
     RECT  64.5 2.137 64.62 2.151 ;
     RECT  67.2 2.137 67.32 2.151 ;
     RECT  69.9 2.137 70.02 2.151 ;
     RECT  72.6 2.137 72.72 2.151 ;
     RECT  75.3 2.137 75.42 2.151 ;
     RECT  78 2.137 78.12 2.151 ;
     RECT  80.7 2.137 80.82 2.151 ;
     RECT  83.4 2.137 83.52 2.151 ;
     RECT  86.1 2.137 86.22 2.151 ;
     RECT  88.8 2.137 88.92 2.151 ;
     RECT  91.5 2.137 91.62 2.151 ;
     RECT  94.2 2.137 94.32 2.151 ;
     RECT  2.4 2.151 2.712 32.101 ;
     RECT  42.9 2.151 43.212 34.213 ;
     RECT  5.1 2.151 5.412 35.605 ;
     RECT  2.4 32.101 3.336 36.085 ;
     RECT  2.304 36.085 3.336 36.275 ;
     RECT  7.8 2.151 8.112 36.421 ;
     RECT  5.1 35.605 6.024 38.101 ;
     RECT  5.1 38.101 6.12 40.213 ;
     RECT  2.4 36.275 3.336 40.259 ;
     RECT  91.5 2.151 91.812 41.557 ;
     RECT  75.3 2.151 75.612 41.605 ;
     RECT  7.8 36.421 8.232 41.651 ;
     RECT  4.512 40.213 6.12 41.699 ;
     RECT  91.2 41.557 91.812 41.699 ;
     RECT  2.4 40.259 2.712 42.709 ;
     RECT  94.2 2.151 94.512 42.709 ;
     RECT  5.1 41.699 6.12 42.949 ;
     RECT  7.8 41.651 8.112 42.949 ;
     RECT  75.168 41.605 75.612 43.091 ;
     RECT  5.1 42.949 8.112 43.285 ;
     RECT  42.336 34.213 43.212 43.333 ;
     RECT  2.4 42.709 3.432 43.523 ;
     RECT  5.1 43.285 8.232 44.099 ;
     RECT  42.192 43.333 43.212 44.149 ;
     RECT  40.2 2.151 40.512 44.245 ;
     RECT  41.568 44.149 43.212 44.245 ;
     RECT  5.1 44.099 6.024 44.965 ;
     RECT  4.512 44.965 6.024 45.827 ;
     RECT  40.2 44.245 43.212 46.307 ;
     RECT  42.576 46.307 43.212 46.787 ;
     RECT  7.8 44.099 8.232 47.123 ;
     RECT  40.2 46.307 41.592 50.389 ;
     RECT  39.696 50.389 41.592 51.395 ;
     RECT  37.5 2.151 37.812 52.213 ;
     RECT  38.976 52.069 39 52.213 ;
     RECT  93.744 42.709 94.512 52.499 ;
     RECT  37.5 52.213 39 54.755 ;
     RECT  94.2 52.499 94.512 56.629 ;
     RECT  42.672 46.787 43.212 64.837 ;
     RECT  45.6 2.151 45.912 64.933 ;
     RECT  38.976 54.755 39 73.859 ;
     RECT  5.1 45.827 6.024 76.165 ;
     RECT  5.1 76.165 6.264 76.307 ;
     RECT  7.8 47.123 8.112 79.189 ;
     RECT  7.056 79.189 8.112 79.859 ;
     RECT  3.888 78.613 3.912 79.955 ;
     RECT  42.672 64.837 43.32 80.917 ;
     RECT  5.1 76.307 5.976 80.965 ;
     RECT  5.1 80.965 6.072 81.155 ;
     RECT  40.2 51.395 41.592 82.069 ;
     RECT  42.624 80.917 43.32 82.069 ;
     RECT  93.552 56.629 94.512 82.979 ;
     RECT  40.2 82.069 43.32 83.651 ;
     RECT  5.1 81.155 5.976 83.749 ;
     RECT  7.8 79.859 8.112 83.749 ;
     RECT  40.2 83.651 43.212 83.749 ;
     RECT  64.5 2.151 64.812 84.325 ;
     RECT  66.192 73.813 66.216 84.325 ;
     RECT  7.8 83.749 8.52 85.091 ;
     RECT  94.08 82.979 94.512 85.139 ;
     RECT  4.368 83.749 5.976 86.723 ;
     RECT  5.1 86.723 5.976 87.299 ;
     RECT  5.1 87.299 5.412 87.829 ;
     RECT  2.4 43.523 2.712 87.877 ;
     RECT  2.304 87.877 2.712 88.019 ;
     RECT  78 2.151 78.312 88.453 ;
     RECT  78 88.453 78.696 88.739 ;
     RECT  78 88.739 78.312 89.269 ;
     RECT  4.752 87.829 5.412 89.411 ;
     RECT  77.52 89.269 78.312 89.459 ;
     RECT  6.72 88.117 6.744 89.555 ;
     RECT  37.5 54.755 37.812 93.301 ;
     RECT  21.3 2.151 21.612 94.405 ;
     RECT  22.656 76.213 22.68 94.405 ;
     RECT  88.8 2.151 89.112 97.381 ;
     RECT  88.8 97.381 89.592 97.909 ;
     RECT  94.2 85.139 94.512 98.437 ;
     RECT  88.8 97.909 90.072 98.483 ;
     RECT  91.392 41.699 91.812 98.675 ;
     RECT  21.3 94.405 22.68 99.875 ;
     RECT  94.2 98.437 95.064 100.211 ;
     RECT  37.5 93.301 38.616 100.261 ;
     RECT  75.3 43.091 75.612 101.317 ;
     RECT  91.5 98.675 91.812 101.413 ;
     RECT  64.5 84.325 66.216 105.923 ;
     RECT  37.5 100.261 38.904 105.925 ;
     RECT  40.08 83.749 43.212 105.925 ;
     RECT  44.784 64.933 45.912 108.323 ;
     RECT  37.5 105.925 43.212 108.469 ;
     RECT  66.192 105.923 66.216 110.291 ;
     RECT  37.5 108.469 43.32 114.035 ;
     RECT  22.656 99.875 22.68 118.691 ;
     RECT  7.8 85.091 8.112 118.981 ;
     RECT  34.8 2.151 35.112 121.909 ;
     RECT  37.5 114.035 41.592 122.147 ;
     RECT  37.5 122.147 41.448 122.771 ;
     RECT  34.8 121.909 35.784 123.589 ;
     RECT  42.72 114.035 43.32 124.261 ;
     RECT  91.5 101.413 92.664 125.317 ;
     RECT  88.8 98.483 89.112 125.365 ;
     RECT  91.5 125.317 92.904 125.459 ;
     RECT  88.8 125.365 90.072 126.131 ;
     RECT  37.5 122.771 41.016 126.229 ;
     RECT  91.5 125.459 91.812 126.421 ;
     RECT  2.4 88.019 2.712 126.469 ;
     RECT  5.1 89.411 5.412 126.469 ;
     RECT  7.344 118.981 8.112 126.517 ;
     RECT  90.72 126.421 91.812 126.563 ;
     RECT  22.8 126.517 22.824 126.755 ;
     RECT  2.4 126.469 3.096 126.803 ;
     RECT  6.816 126.517 8.112 126.803 ;
     RECT  42.48 124.261 43.32 126.949 ;
     RECT  78 89.459 78.312 127.045 ;
     RECT  5.1 126.469 5.736 127.139 ;
     RECT  5.1 127.139 5.412 127.381 ;
     RECT  42.288 126.949 43.32 129.491 ;
     RECT  4.752 127.381 5.412 130.019 ;
     RECT  7.68 126.803 8.112 130.355 ;
     RECT  7.8 130.355 8.112 131.029 ;
     RECT  7.8 131.029 8.232 132.131 ;
     RECT  77.472 127.045 78.312 132.371 ;
     RECT  75.3 101.317 75.72 132.467 ;
     RECT  91.056 126.563 91.812 132.757 ;
     RECT  42.288 129.491 43.212 133.475 ;
     RECT  37.152 126.229 41.016 133.715 ;
     RECT  42.432 133.475 43.212 134.147 ;
     RECT  37.392 133.715 41.016 135.061 ;
     RECT  34.8 123.589 35.88 135.683 ;
     RECT  37.104 135.061 41.016 138.035 ;
     RECT  34.8 135.683 35.64 138.757 ;
     RECT  37.392 138.035 41.016 140.243 ;
     RECT  34.8 138.757 35.88 140.627 ;
     RECT  90.288 132.757 91.812 140.723 ;
     RECT  91.152 140.723 91.812 140.819 ;
     RECT  34.8 140.627 35.64 141.877 ;
     RECT  37.5 140.243 41.016 142.547 ;
     RECT  93.024 141.541 93.048 142.547 ;
     RECT  34.8 141.877 35.976 165.923 ;
     RECT  37.5 142.547 40.512 166.355 ;
     RECT  2.4 126.803 2.712 168.489 ;
     RECT  5.1 130.019 5.412 168.489 ;
     RECT  7.8 132.131 8.112 168.489 ;
     RECT  10.5 2.151 10.812 168.489 ;
     RECT  13.2 2.151 13.512 168.489 ;
     RECT  15.9 2.151 16.212 168.489 ;
     RECT  18.6 2.151 18.912 168.489 ;
     RECT  21.3 99.875 21.612 168.489 ;
     RECT  24 2.151 24.312 168.489 ;
     RECT  26.7 2.151 27.012 168.489 ;
     RECT  29.4 2.151 29.712 168.489 ;
     RECT  32.1 2.151 32.412 168.489 ;
     RECT  34.8 165.923 35.112 168.489 ;
     RECT  39.36 166.355 40.512 168.489 ;
     RECT  42.9 134.147 43.212 168.489 ;
     RECT  45.6 108.323 45.912 168.489 ;
     RECT  48.3 2.151 48.612 168.489 ;
     RECT  51 2.151 51.312 168.489 ;
     RECT  53.7 2.151 54.012 168.489 ;
     RECT  56.4 2.151 56.712 168.489 ;
     RECT  59.1 2.151 59.412 168.489 ;
     RECT  61.8 2.151 62.112 168.489 ;
     RECT  64.5 105.923 64.812 168.489 ;
     RECT  67.2 2.151 67.512 168.489 ;
     RECT  69.9 2.151 70.212 168.489 ;
     RECT  72.6 2.151 72.912 168.489 ;
     RECT  75.3 132.467 75.612 168.489 ;
     RECT  78 132.371 78.312 168.489 ;
     RECT  80.7 2.151 81.012 168.489 ;
     RECT  83.4 2.151 83.712 168.489 ;
     RECT  86.1 2.151 86.412 168.489 ;
     RECT  88.8 126.131 89.112 168.489 ;
     RECT  91.5 140.819 91.812 168.489 ;
     RECT  94.2 100.211 94.512 168.489 ;
     RECT  2.4 168.489 2.52 168.503 ;
     RECT  5.1 168.489 5.22 168.503 ;
     RECT  7.8 168.489 7.92 168.503 ;
     RECT  10.5 168.489 10.62 168.503 ;
     RECT  13.2 168.489 13.32 168.503 ;
     RECT  15.9 168.489 16.02 168.503 ;
     RECT  18.6 168.489 18.72 168.503 ;
     RECT  21.3 168.489 21.42 168.503 ;
     RECT  24 168.489 24.12 168.503 ;
     RECT  26.7 168.489 26.82 168.503 ;
     RECT  29.4 168.489 29.52 168.503 ;
     RECT  32.1 168.489 32.22 168.503 ;
     RECT  34.8 168.489 34.92 168.503 ;
     RECT  37.5 166.355 37.992 168.503 ;
     RECT  39.36 168.489 40.32 168.503 ;
     RECT  42.9 168.489 43.02 168.503 ;
     RECT  45.6 168.489 45.72 168.503 ;
     RECT  48.3 168.489 48.42 168.503 ;
     RECT  51 168.489 51.12 168.503 ;
     RECT  53.7 168.489 53.82 168.503 ;
     RECT  56.4 168.489 56.52 168.503 ;
     RECT  59.1 168.489 59.22 168.503 ;
     RECT  61.8 168.489 61.92 168.503 ;
     RECT  64.5 168.489 64.62 168.503 ;
     RECT  67.2 168.489 67.32 168.503 ;
     RECT  69.9 168.489 70.02 168.503 ;
     RECT  72.6 168.489 72.72 168.503 ;
     RECT  75.3 168.489 75.42 168.503 ;
     RECT  78 168.489 78.12 168.503 ;
     RECT  80.7 168.489 80.82 168.503 ;
     RECT  83.4 168.489 83.52 168.503 ;
     RECT  86.1 168.489 86.22 168.503 ;
     RECT  88.8 168.489 88.92 168.503 ;
     RECT  91.5 168.489 91.62 168.503 ;
     RECT  94.2 168.489 94.32 168.503 ;
     RECT  39.36 168.503 39.384 170.483 ;
     RECT  37.968 168.503 37.992 170.531 ;
  END
END qfd_landh0d8sn_173_EW_98x171
END LIBRARY
